VERSION 5.8 ;
BUSBITCHARS "[]" ;
DIVIDERCHAR "/" ;
UNITS
    DATABASE MICRONS 1000 ;
END UNITS

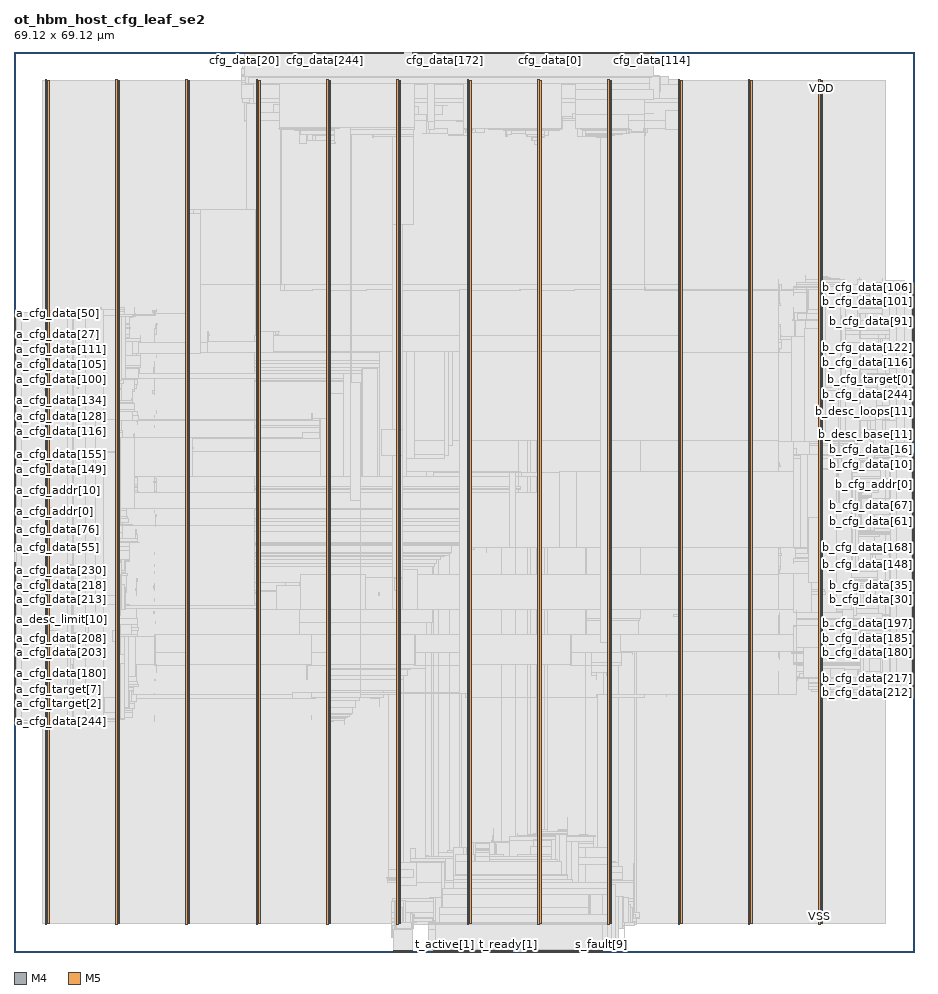
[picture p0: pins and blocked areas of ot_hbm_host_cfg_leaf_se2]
MACRO ot_hbm_host_cfg_leaf_se2
  FOREIGN ot_hbm_host_cfg_leaf_se2 0 0 ;
  CLASS BLOCK ;
  SIZE 69.12 BY 69.12 ;
  PIN a_cfg_addr[0]
    DIRECTION OUTPUT ;
    USE SIGNAL ;
    PORT
      LAYER M4 ;
        RECT  0 33.84 0.084 33.864 ;
    END
  END a_cfg_addr[0]
  PIN a_cfg_addr[10]
    DIRECTION OUTPUT ;
    USE SIGNAL ;
    PORT
      LAYER M4 ;
        RECT  0 34.8 0.084 34.824 ;
    END
  END a_cfg_addr[10]
  PIN a_cfg_addr[11]
    DIRECTION OUTPUT ;
    USE SIGNAL ;
    PORT
      LAYER M4 ;
        RECT  0 34.896 0.084 34.92 ;
    END
  END a_cfg_addr[11]
  PIN a_cfg_addr[1]
    DIRECTION OUTPUT ;
    USE SIGNAL ;
    PORT
      LAYER M4 ;
        RECT  0 33.936 0.084 33.96 ;
    END
  END a_cfg_addr[1]
  PIN a_cfg_addr[2]
    DIRECTION OUTPUT ;
    USE SIGNAL ;
    PORT
      LAYER M4 ;
        RECT  0 34.032 0.084 34.056 ;
    END
  END a_cfg_addr[2]
  PIN a_cfg_addr[3]
    DIRECTION OUTPUT ;
    USE SIGNAL ;
    PORT
      LAYER M4 ;
        RECT  0 34.128 0.084 34.152 ;
    END
  END a_cfg_addr[3]
  PIN a_cfg_addr[4]
    DIRECTION OUTPUT ;
    USE SIGNAL ;
    PORT
      LAYER M4 ;
        RECT  0 34.224 0.084 34.248 ;
    END
  END a_cfg_addr[4]
  PIN a_cfg_addr[5]
    DIRECTION OUTPUT ;
    USE SIGNAL ;
    PORT
      LAYER M4 ;
        RECT  0 34.32 0.084 34.344 ;
    END
  END a_cfg_addr[5]
  PIN a_cfg_addr[6]
    DIRECTION OUTPUT ;
    USE SIGNAL ;
    PORT
      LAYER M4 ;
        RECT  0 34.416 0.084 34.44 ;
    END
  END a_cfg_addr[6]
  PIN a_cfg_addr[7]
    DIRECTION OUTPUT ;
    USE SIGNAL ;
    PORT
      LAYER M4 ;
        RECT  0 34.512 0.084 34.536 ;
    END
  END a_cfg_addr[7]
  PIN a_cfg_addr[8]
    DIRECTION OUTPUT ;
    USE SIGNAL ;
    PORT
      LAYER M4 ;
        RECT  0 34.608 0.084 34.632 ;
    END
  END a_cfg_addr[8]
  PIN a_cfg_addr[9]
    DIRECTION OUTPUT ;
    USE SIGNAL ;
    PORT
      LAYER M4 ;
        RECT  0 34.704 0.084 34.728 ;
    END
  END a_cfg_addr[9]
  PIN a_cfg_data[0]
    DIRECTION OUTPUT ;
    USE SIGNAL ;
    PORT
      LAYER M4 ;
        RECT  0 34.992 0.084 35.016 ;
    END
  END a_cfg_data[0]
  PIN a_cfg_data[100]
    DIRECTION OUTPUT ;
    USE SIGNAL ;
    PORT
      LAYER M4 ;
        RECT  0 44.592 0.084 44.616 ;
    END
  END a_cfg_data[100]
  PIN a_cfg_data[101]
    DIRECTION OUTPUT ;
    USE SIGNAL ;
    PORT
      LAYER M4 ;
        RECT  0 44.688 0.084 44.712 ;
    END
  END a_cfg_data[101]
  PIN a_cfg_data[102]
    DIRECTION OUTPUT ;
    USE SIGNAL ;
    PORT
      LAYER M4 ;
        RECT  0 44.784 0.084 44.808 ;
    END
  END a_cfg_data[102]
  PIN a_cfg_data[103]
    DIRECTION OUTPUT ;
    USE SIGNAL ;
    PORT
      LAYER M4 ;
        RECT  0 44.88 0.084 44.904 ;
    END
  END a_cfg_data[103]
  PIN a_cfg_data[104]
    DIRECTION OUTPUT ;
    USE SIGNAL ;
    PORT
      LAYER M4 ;
        RECT  0 44.976 0.084 45 ;
    END
  END a_cfg_data[104]
  PIN a_cfg_data[105]
    DIRECTION OUTPUT ;
    USE SIGNAL ;
    PORT
      LAYER M4 ;
        RECT  0 45.072 0.084 45.096 ;
    END
  END a_cfg_data[105]
  PIN a_cfg_data[106]
    DIRECTION OUTPUT ;
    USE SIGNAL ;
    PORT
      LAYER M4 ;
        RECT  0 45.168 0.084 45.192 ;
    END
  END a_cfg_data[106]
  PIN a_cfg_data[107]
    DIRECTION OUTPUT ;
    USE SIGNAL ;
    PORT
      LAYER M4 ;
        RECT  0 45.264 0.084 45.288 ;
    END
  END a_cfg_data[107]
  PIN a_cfg_data[108]
    DIRECTION OUTPUT ;
    USE SIGNAL ;
    PORT
      LAYER M4 ;
        RECT  0 45.36 0.084 45.384 ;
    END
  END a_cfg_data[108]
  PIN a_cfg_data[109]
    DIRECTION OUTPUT ;
    USE SIGNAL ;
    PORT
      LAYER M4 ;
        RECT  0 45.456 0.084 45.48 ;
    END
  END a_cfg_data[109]
  PIN a_cfg_data[10]
    DIRECTION OUTPUT ;
    USE SIGNAL ;
    PORT
      LAYER M4 ;
        RECT  0 35.952 0.084 35.976 ;
    END
  END a_cfg_data[10]
  PIN a_cfg_data[110]
    DIRECTION OUTPUT ;
    USE SIGNAL ;
    PORT
      LAYER M4 ;
        RECT  0 45.552 0.084 45.576 ;
    END
  END a_cfg_data[110]
  PIN a_cfg_data[111]
    DIRECTION OUTPUT ;
    USE SIGNAL ;
    PORT
      LAYER M4 ;
        RECT  0 45.648 0.084 45.672 ;
    END
  END a_cfg_data[111]
  PIN a_cfg_data[112]
    DIRECTION OUTPUT ;
    USE SIGNAL ;
    PORT
      LAYER M4 ;
        RECT  0 45.744 0.084 45.768 ;
    END
  END a_cfg_data[112]
  PIN a_cfg_data[113]
    DIRECTION OUTPUT ;
    USE SIGNAL ;
    PORT
      LAYER M4 ;
        RECT  0 45.84 0.084 45.864 ;
    END
  END a_cfg_data[113]
  PIN a_cfg_data[114]
    DIRECTION OUTPUT ;
    USE SIGNAL ;
    PORT
      LAYER M4 ;
        RECT  0 45.936 0.084 45.96 ;
    END
  END a_cfg_data[114]
  PIN a_cfg_data[115]
    DIRECTION OUTPUT ;
    USE SIGNAL ;
    PORT
      LAYER M4 ;
        RECT  0 46.032 0.084 46.056 ;
    END
  END a_cfg_data[115]
  PIN a_cfg_data[116]
    DIRECTION OUTPUT ;
    USE SIGNAL ;
    PORT
      LAYER M4 ;
        RECT  0 39.984 0.084 40.008 ;
    END
  END a_cfg_data[116]
  PIN a_cfg_data[117]
    DIRECTION OUTPUT ;
    USE SIGNAL ;
    PORT
      LAYER M4 ;
        RECT  0 40.08 0.084 40.104 ;
    END
  END a_cfg_data[117]
  PIN a_cfg_data[118]
    DIRECTION OUTPUT ;
    USE SIGNAL ;
    PORT
      LAYER M4 ;
        RECT  0 40.176 0.084 40.2 ;
    END
  END a_cfg_data[118]
  PIN a_cfg_data[119]
    DIRECTION OUTPUT ;
    USE SIGNAL ;
    PORT
      LAYER M4 ;
        RECT  0 40.272 0.084 40.296 ;
    END
  END a_cfg_data[119]
  PIN a_cfg_data[11]
    DIRECTION OUTPUT ;
    USE SIGNAL ;
    PORT
      LAYER M4 ;
        RECT  0 36.048 0.084 36.072 ;
    END
  END a_cfg_data[11]
  PIN a_cfg_data[120]
    DIRECTION OUTPUT ;
    USE SIGNAL ;
    PORT
      LAYER M4 ;
        RECT  0 40.368 0.084 40.392 ;
    END
  END a_cfg_data[120]
  PIN a_cfg_data[121]
    DIRECTION OUTPUT ;
    USE SIGNAL ;
    PORT
      LAYER M4 ;
        RECT  0 40.464 0.084 40.488 ;
    END
  END a_cfg_data[121]
  PIN a_cfg_data[122]
    DIRECTION OUTPUT ;
    USE SIGNAL ;
    PORT
      LAYER M4 ;
        RECT  0 40.56 0.084 40.584 ;
    END
  END a_cfg_data[122]
  PIN a_cfg_data[123]
    DIRECTION OUTPUT ;
    USE SIGNAL ;
    PORT
      LAYER M4 ;
        RECT  0 40.656 0.084 40.68 ;
    END
  END a_cfg_data[123]
  PIN a_cfg_data[124]
    DIRECTION OUTPUT ;
    USE SIGNAL ;
    PORT
      LAYER M4 ;
        RECT  0 40.752 0.084 40.776 ;
    END
  END a_cfg_data[124]
  PIN a_cfg_data[125]
    DIRECTION OUTPUT ;
    USE SIGNAL ;
    PORT
      LAYER M4 ;
        RECT  0 40.848 0.084 40.872 ;
    END
  END a_cfg_data[125]
  PIN a_cfg_data[126]
    DIRECTION OUTPUT ;
    USE SIGNAL ;
    PORT
      LAYER M4 ;
        RECT  0 40.944 0.084 40.968 ;
    END
  END a_cfg_data[126]
  PIN a_cfg_data[127]
    DIRECTION OUTPUT ;
    USE SIGNAL ;
    PORT
      LAYER M4 ;
        RECT  0 41.04 0.084 41.064 ;
    END
  END a_cfg_data[127]
  PIN a_cfg_data[128]
    DIRECTION OUTPUT ;
    USE SIGNAL ;
    PORT
      LAYER M4 ;
        RECT  0 41.136 0.084 41.16 ;
    END
  END a_cfg_data[128]
  PIN a_cfg_data[129]
    DIRECTION OUTPUT ;
    USE SIGNAL ;
    PORT
      LAYER M4 ;
        RECT  0 41.232 0.084 41.256 ;
    END
  END a_cfg_data[129]
  PIN a_cfg_data[12]
    DIRECTION OUTPUT ;
    USE SIGNAL ;
    PORT
      LAYER M4 ;
        RECT  0 36.144 0.084 36.168 ;
    END
  END a_cfg_data[12]
  PIN a_cfg_data[130]
    DIRECTION OUTPUT ;
    USE SIGNAL ;
    PORT
      LAYER M4 ;
        RECT  0 41.328 0.084 41.352 ;
    END
  END a_cfg_data[130]
  PIN a_cfg_data[131]
    DIRECTION OUTPUT ;
    USE SIGNAL ;
    PORT
      LAYER M4 ;
        RECT  0 41.424 0.084 41.448 ;
    END
  END a_cfg_data[131]
  PIN a_cfg_data[132]
    DIRECTION OUTPUT ;
    USE SIGNAL ;
    PORT
      LAYER M4 ;
        RECT  0 41.52 0.084 41.544 ;
    END
  END a_cfg_data[132]
  PIN a_cfg_data[133]
    DIRECTION OUTPUT ;
    USE SIGNAL ;
    PORT
      LAYER M4 ;
        RECT  0 41.616 0.084 41.64 ;
    END
  END a_cfg_data[133]
  PIN a_cfg_data[134]
    DIRECTION OUTPUT ;
    USE SIGNAL ;
    PORT
      LAYER M4 ;
        RECT  0 41.712 0.084 41.736 ;
    END
  END a_cfg_data[134]
  PIN a_cfg_data[135]
    DIRECTION OUTPUT ;
    USE SIGNAL ;
    PORT
      LAYER M4 ;
        RECT  0 41.808 0.084 41.832 ;
    END
  END a_cfg_data[135]
  PIN a_cfg_data[136]
    DIRECTION OUTPUT ;
    USE SIGNAL ;
    PORT
      LAYER M4 ;
        RECT  0 41.904 0.084 41.928 ;
    END
  END a_cfg_data[136]
  PIN a_cfg_data[137]
    DIRECTION OUTPUT ;
    USE SIGNAL ;
    PORT
      LAYER M4 ;
        RECT  0 42 0.084 42.024 ;
    END
  END a_cfg_data[137]
  PIN a_cfg_data[138]
    DIRECTION OUTPUT ;
    USE SIGNAL ;
    PORT
      LAYER M4 ;
        RECT  0 42.096 0.084 42.12 ;
    END
  END a_cfg_data[138]
  PIN a_cfg_data[139]
    DIRECTION OUTPUT ;
    USE SIGNAL ;
    PORT
      LAYER M4 ;
        RECT  0 42.192 0.084 42.216 ;
    END
  END a_cfg_data[139]
  PIN a_cfg_data[13]
    DIRECTION OUTPUT ;
    USE SIGNAL ;
    PORT
      LAYER M4 ;
        RECT  0 36.24 0.084 36.264 ;
    END
  END a_cfg_data[13]
  PIN a_cfg_data[140]
    DIRECTION OUTPUT ;
    USE SIGNAL ;
    PORT
      LAYER M4 ;
        RECT  0 42.288 0.084 42.312 ;
    END
  END a_cfg_data[140]
  PIN a_cfg_data[141]
    DIRECTION OUTPUT ;
    USE SIGNAL ;
    PORT
      LAYER M4 ;
        RECT  0 42.384 0.084 42.408 ;
    END
  END a_cfg_data[141]
  PIN a_cfg_data[142]
    DIRECTION OUTPUT ;
    USE SIGNAL ;
    PORT
      LAYER M4 ;
        RECT  0 42.48 0.084 42.504 ;
    END
  END a_cfg_data[142]
  PIN a_cfg_data[143]
    DIRECTION OUTPUT ;
    USE SIGNAL ;
    PORT
      LAYER M4 ;
        RECT  0 42.576 0.084 42.6 ;
    END
  END a_cfg_data[143]
  PIN a_cfg_data[144]
    DIRECTION OUTPUT ;
    USE SIGNAL ;
    PORT
      LAYER M4 ;
        RECT  0 42.672 0.084 42.696 ;
    END
  END a_cfg_data[144]
  PIN a_cfg_data[145]
    DIRECTION OUTPUT ;
    USE SIGNAL ;
    PORT
      LAYER M4 ;
        RECT  0 42.768 0.084 42.792 ;
    END
  END a_cfg_data[145]
  PIN a_cfg_data[146]
    DIRECTION OUTPUT ;
    USE SIGNAL ;
    PORT
      LAYER M4 ;
        RECT  0 42.864 0.084 42.888 ;
    END
  END a_cfg_data[146]
  PIN a_cfg_data[147]
    DIRECTION OUTPUT ;
    USE SIGNAL ;
    PORT
      LAYER M4 ;
        RECT  0 42.96 0.084 42.984 ;
    END
  END a_cfg_data[147]
  PIN a_cfg_data[148]
    DIRECTION OUTPUT ;
    USE SIGNAL ;
    PORT
      LAYER M4 ;
        RECT  0 36.912 0.084 36.936 ;
    END
  END a_cfg_data[148]
  PIN a_cfg_data[149]
    DIRECTION OUTPUT ;
    USE SIGNAL ;
    PORT
      LAYER M4 ;
        RECT  0 37.008 0.084 37.032 ;
    END
  END a_cfg_data[149]
  PIN a_cfg_data[14]
    DIRECTION OUTPUT ;
    USE SIGNAL ;
    PORT
      LAYER M4 ;
        RECT  0 36.336 0.084 36.36 ;
    END
  END a_cfg_data[14]
  PIN a_cfg_data[150]
    DIRECTION OUTPUT ;
    USE SIGNAL ;
    PORT
      LAYER M4 ;
        RECT  0 37.104 0.084 37.128 ;
    END
  END a_cfg_data[150]
  PIN a_cfg_data[151]
    DIRECTION OUTPUT ;
    USE SIGNAL ;
    PORT
      LAYER M4 ;
        RECT  0 37.2 0.084 37.224 ;
    END
  END a_cfg_data[151]
  PIN a_cfg_data[152]
    DIRECTION OUTPUT ;
    USE SIGNAL ;
    PORT
      LAYER M4 ;
        RECT  0 37.296 0.084 37.32 ;
    END
  END a_cfg_data[152]
  PIN a_cfg_data[153]
    DIRECTION OUTPUT ;
    USE SIGNAL ;
    PORT
      LAYER M4 ;
        RECT  0 37.392 0.084 37.416 ;
    END
  END a_cfg_data[153]
  PIN a_cfg_data[154]
    DIRECTION OUTPUT ;
    USE SIGNAL ;
    PORT
      LAYER M4 ;
        RECT  0 37.488 0.084 37.512 ;
    END
  END a_cfg_data[154]
  PIN a_cfg_data[155]
    DIRECTION OUTPUT ;
    USE SIGNAL ;
    PORT
      LAYER M4 ;
        RECT  0 37.584 0.084 37.608 ;
    END
  END a_cfg_data[155]
  PIN a_cfg_data[156]
    DIRECTION OUTPUT ;
    USE SIGNAL ;
    PORT
      LAYER M4 ;
        RECT  0 37.68 0.084 37.704 ;
    END
  END a_cfg_data[156]
  PIN a_cfg_data[157]
    DIRECTION OUTPUT ;
    USE SIGNAL ;
    PORT
      LAYER M4 ;
        RECT  0 37.776 0.084 37.8 ;
    END
  END a_cfg_data[157]
  PIN a_cfg_data[158]
    DIRECTION OUTPUT ;
    USE SIGNAL ;
    PORT
      LAYER M4 ;
        RECT  0 37.872 0.084 37.896 ;
    END
  END a_cfg_data[158]
  PIN a_cfg_data[159]
    DIRECTION OUTPUT ;
    USE SIGNAL ;
    PORT
      LAYER M4 ;
        RECT  0 37.968 0.084 37.992 ;
    END
  END a_cfg_data[159]
  PIN a_cfg_data[15]
    DIRECTION OUTPUT ;
    USE SIGNAL ;
    PORT
      LAYER M4 ;
        RECT  0 36.432 0.084 36.456 ;
    END
  END a_cfg_data[15]
  PIN a_cfg_data[160]
    DIRECTION OUTPUT ;
    USE SIGNAL ;
    PORT
      LAYER M4 ;
        RECT  0 38.064 0.084 38.088 ;
    END
  END a_cfg_data[160]
  PIN a_cfg_data[161]
    DIRECTION OUTPUT ;
    USE SIGNAL ;
    PORT
      LAYER M4 ;
        RECT  0 38.16 0.084 38.184 ;
    END
  END a_cfg_data[161]
  PIN a_cfg_data[162]
    DIRECTION OUTPUT ;
    USE SIGNAL ;
    PORT
      LAYER M4 ;
        RECT  0 38.256 0.084 38.28 ;
    END
  END a_cfg_data[162]
  PIN a_cfg_data[163]
    DIRECTION OUTPUT ;
    USE SIGNAL ;
    PORT
      LAYER M4 ;
        RECT  0 38.352 0.084 38.376 ;
    END
  END a_cfg_data[163]
  PIN a_cfg_data[164]
    DIRECTION OUTPUT ;
    USE SIGNAL ;
    PORT
      LAYER M4 ;
        RECT  0 38.448 0.084 38.472 ;
    END
  END a_cfg_data[164]
  PIN a_cfg_data[165]
    DIRECTION OUTPUT ;
    USE SIGNAL ;
    PORT
      LAYER M4 ;
        RECT  0 38.544 0.084 38.568 ;
    END
  END a_cfg_data[165]
  PIN a_cfg_data[166]
    DIRECTION OUTPUT ;
    USE SIGNAL ;
    PORT
      LAYER M4 ;
        RECT  0 38.64 0.084 38.664 ;
    END
  END a_cfg_data[166]
  PIN a_cfg_data[167]
    DIRECTION OUTPUT ;
    USE SIGNAL ;
    PORT
      LAYER M4 ;
        RECT  0 38.736 0.084 38.76 ;
    END
  END a_cfg_data[167]
  PIN a_cfg_data[168]
    DIRECTION OUTPUT ;
    USE SIGNAL ;
    PORT
      LAYER M4 ;
        RECT  0 38.832 0.084 38.856 ;
    END
  END a_cfg_data[168]
  PIN a_cfg_data[169]
    DIRECTION OUTPUT ;
    USE SIGNAL ;
    PORT
      LAYER M4 ;
        RECT  0 38.928 0.084 38.952 ;
    END
  END a_cfg_data[169]
  PIN a_cfg_data[16]
    DIRECTION OUTPUT ;
    USE SIGNAL ;
    PORT
      LAYER M4 ;
        RECT  0 36.528 0.084 36.552 ;
    END
  END a_cfg_data[16]
  PIN a_cfg_data[170]
    DIRECTION OUTPUT ;
    USE SIGNAL ;
    PORT
      LAYER M4 ;
        RECT  0 39.024 0.084 39.048 ;
    END
  END a_cfg_data[170]
  PIN a_cfg_data[171]
    DIRECTION OUTPUT ;
    USE SIGNAL ;
    PORT
      LAYER M4 ;
        RECT  0 39.12 0.084 39.144 ;
    END
  END a_cfg_data[171]
  PIN a_cfg_data[172]
    DIRECTION OUTPUT ;
    USE SIGNAL ;
    PORT
      LAYER M4 ;
        RECT  0 39.216 0.084 39.24 ;
    END
  END a_cfg_data[172]
  PIN a_cfg_data[173]
    DIRECTION OUTPUT ;
    USE SIGNAL ;
    PORT
      LAYER M4 ;
        RECT  0 39.312 0.084 39.336 ;
    END
  END a_cfg_data[173]
  PIN a_cfg_data[174]
    DIRECTION OUTPUT ;
    USE SIGNAL ;
    PORT
      LAYER M4 ;
        RECT  0 39.408 0.084 39.432 ;
    END
  END a_cfg_data[174]
  PIN a_cfg_data[175]
    DIRECTION OUTPUT ;
    USE SIGNAL ;
    PORT
      LAYER M4 ;
        RECT  0 39.504 0.084 39.528 ;
    END
  END a_cfg_data[175]
  PIN a_cfg_data[176]
    DIRECTION OUTPUT ;
    USE SIGNAL ;
    PORT
      LAYER M4 ;
        RECT  0 39.6 0.084 39.624 ;
    END
  END a_cfg_data[176]
  PIN a_cfg_data[177]
    DIRECTION OUTPUT ;
    USE SIGNAL ;
    PORT
      LAYER M4 ;
        RECT  0 39.696 0.084 39.72 ;
    END
  END a_cfg_data[177]
  PIN a_cfg_data[178]
    DIRECTION OUTPUT ;
    USE SIGNAL ;
    PORT
      LAYER M4 ;
        RECT  0 39.792 0.084 39.816 ;
    END
  END a_cfg_data[178]
  PIN a_cfg_data[179]
    DIRECTION OUTPUT ;
    USE SIGNAL ;
    PORT
      LAYER M4 ;
        RECT  0 39.888 0.084 39.912 ;
    END
  END a_cfg_data[179]
  PIN a_cfg_data[17]
    DIRECTION OUTPUT ;
    USE SIGNAL ;
    PORT
      LAYER M4 ;
        RECT  0 36.624 0.084 36.648 ;
    END
  END a_cfg_data[17]
  PIN a_cfg_data[180]
    DIRECTION OUTPUT ;
    USE SIGNAL ;
    PORT
      LAYER M4 ;
        RECT  0 20.784 0.084 20.808 ;
    END
  END a_cfg_data[180]
  PIN a_cfg_data[181]
    DIRECTION OUTPUT ;
    USE SIGNAL ;
    PORT
      LAYER M4 ;
        RECT  0 20.88 0.084 20.904 ;
    END
  END a_cfg_data[181]
  PIN a_cfg_data[182]
    DIRECTION OUTPUT ;
    USE SIGNAL ;
    PORT
      LAYER M4 ;
        RECT  0 20.976 0.084 21 ;
    END
  END a_cfg_data[182]
  PIN a_cfg_data[183]
    DIRECTION OUTPUT ;
    USE SIGNAL ;
    PORT
      LAYER M4 ;
        RECT  0 21.072 0.084 21.096 ;
    END
  END a_cfg_data[183]
  PIN a_cfg_data[184]
    DIRECTION OUTPUT ;
    USE SIGNAL ;
    PORT
      LAYER M4 ;
        RECT  0 21.168 0.084 21.192 ;
    END
  END a_cfg_data[184]
  PIN a_cfg_data[185]
    DIRECTION OUTPUT ;
    USE SIGNAL ;
    PORT
      LAYER M4 ;
        RECT  0 21.264 0.084 21.288 ;
    END
  END a_cfg_data[185]
  PIN a_cfg_data[186]
    DIRECTION OUTPUT ;
    USE SIGNAL ;
    PORT
      LAYER M4 ;
        RECT  0 21.36 0.084 21.384 ;
    END
  END a_cfg_data[186]
  PIN a_cfg_data[187]
    DIRECTION OUTPUT ;
    USE SIGNAL ;
    PORT
      LAYER M4 ;
        RECT  0 21.456 0.084 21.48 ;
    END
  END a_cfg_data[187]
  PIN a_cfg_data[188]
    DIRECTION OUTPUT ;
    USE SIGNAL ;
    PORT
      LAYER M4 ;
        RECT  0 21.552 0.084 21.576 ;
    END
  END a_cfg_data[188]
  PIN a_cfg_data[189]
    DIRECTION OUTPUT ;
    USE SIGNAL ;
    PORT
      LAYER M4 ;
        RECT  0 21.648 0.084 21.672 ;
    END
  END a_cfg_data[189]
  PIN a_cfg_data[18]
    DIRECTION OUTPUT ;
    USE SIGNAL ;
    PORT
      LAYER M4 ;
        RECT  0 36.72 0.084 36.744 ;
    END
  END a_cfg_data[18]
  PIN a_cfg_data[190]
    DIRECTION OUTPUT ;
    USE SIGNAL ;
    PORT
      LAYER M4 ;
        RECT  0 21.744 0.084 21.768 ;
    END
  END a_cfg_data[190]
  PIN a_cfg_data[191]
    DIRECTION OUTPUT ;
    USE SIGNAL ;
    PORT
      LAYER M4 ;
        RECT  0 21.84 0.084 21.864 ;
    END
  END a_cfg_data[191]
  PIN a_cfg_data[192]
    DIRECTION OUTPUT ;
    USE SIGNAL ;
    PORT
      LAYER M4 ;
        RECT  0 21.936 0.084 21.96 ;
    END
  END a_cfg_data[192]
  PIN a_cfg_data[193]
    DIRECTION OUTPUT ;
    USE SIGNAL ;
    PORT
      LAYER M4 ;
        RECT  0 22.032 0.084 22.056 ;
    END
  END a_cfg_data[193]
  PIN a_cfg_data[194]
    DIRECTION OUTPUT ;
    USE SIGNAL ;
    PORT
      LAYER M4 ;
        RECT  0 22.128 0.084 22.152 ;
    END
  END a_cfg_data[194]
  PIN a_cfg_data[195]
    DIRECTION OUTPUT ;
    USE SIGNAL ;
    PORT
      LAYER M4 ;
        RECT  0 22.224 0.084 22.248 ;
    END
  END a_cfg_data[195]
  PIN a_cfg_data[196]
    DIRECTION OUTPUT ;
    USE SIGNAL ;
    PORT
      LAYER M4 ;
        RECT  0 22.32 0.084 22.344 ;
    END
  END a_cfg_data[196]
  PIN a_cfg_data[197]
    DIRECTION OUTPUT ;
    USE SIGNAL ;
    PORT
      LAYER M4 ;
        RECT  0 22.416 0.084 22.44 ;
    END
  END a_cfg_data[197]
  PIN a_cfg_data[198]
    DIRECTION OUTPUT ;
    USE SIGNAL ;
    PORT
      LAYER M4 ;
        RECT  0 22.512 0.084 22.536 ;
    END
  END a_cfg_data[198]
  PIN a_cfg_data[199]
    DIRECTION OUTPUT ;
    USE SIGNAL ;
    PORT
      LAYER M4 ;
        RECT  0 22.608 0.084 22.632 ;
    END
  END a_cfg_data[199]
  PIN a_cfg_data[19]
    DIRECTION OUTPUT ;
    USE SIGNAL ;
    PORT
      LAYER M4 ;
        RECT  0 36.816 0.084 36.84 ;
    END
  END a_cfg_data[19]
  PIN a_cfg_data[1]
    DIRECTION OUTPUT ;
    USE SIGNAL ;
    PORT
      LAYER M4 ;
        RECT  0 35.088 0.084 35.112 ;
    END
  END a_cfg_data[1]
  PIN a_cfg_data[200]
    DIRECTION OUTPUT ;
    USE SIGNAL ;
    PORT
      LAYER M4 ;
        RECT  0 22.704 0.084 22.728 ;
    END
  END a_cfg_data[200]
  PIN a_cfg_data[201]
    DIRECTION OUTPUT ;
    USE SIGNAL ;
    PORT
      LAYER M4 ;
        RECT  0 22.8 0.084 22.824 ;
    END
  END a_cfg_data[201]
  PIN a_cfg_data[202]
    DIRECTION OUTPUT ;
    USE SIGNAL ;
    PORT
      LAYER M4 ;
        RECT  0 22.896 0.084 22.92 ;
    END
  END a_cfg_data[202]
  PIN a_cfg_data[203]
    DIRECTION OUTPUT ;
    USE SIGNAL ;
    PORT
      LAYER M4 ;
        RECT  0 22.992 0.084 23.016 ;
    END
  END a_cfg_data[203]
  PIN a_cfg_data[204]
    DIRECTION OUTPUT ;
    USE SIGNAL ;
    PORT
      LAYER M4 ;
        RECT  0 23.088 0.084 23.112 ;
    END
  END a_cfg_data[204]
  PIN a_cfg_data[205]
    DIRECTION OUTPUT ;
    USE SIGNAL ;
    PORT
      LAYER M4 ;
        RECT  0 23.184 0.084 23.208 ;
    END
  END a_cfg_data[205]
  PIN a_cfg_data[206]
    DIRECTION OUTPUT ;
    USE SIGNAL ;
    PORT
      LAYER M4 ;
        RECT  0 23.28 0.084 23.304 ;
    END
  END a_cfg_data[206]
  PIN a_cfg_data[207]
    DIRECTION OUTPUT ;
    USE SIGNAL ;
    PORT
      LAYER M4 ;
        RECT  0 23.376 0.084 23.4 ;
    END
  END a_cfg_data[207]
  PIN a_cfg_data[208]
    DIRECTION OUTPUT ;
    USE SIGNAL ;
    PORT
      LAYER M4 ;
        RECT  0 23.472 0.084 23.496 ;
    END
  END a_cfg_data[208]
  PIN a_cfg_data[209]
    DIRECTION OUTPUT ;
    USE SIGNAL ;
    PORT
      LAYER M4 ;
        RECT  0 23.568 0.084 23.592 ;
    END
  END a_cfg_data[209]
  PIN a_cfg_data[20]
    DIRECTION OUTPUT ;
    USE SIGNAL ;
    PORT
      LAYER M4 ;
        RECT  0 46.128 0.084 46.152 ;
    END
  END a_cfg_data[20]
  PIN a_cfg_data[210]
    DIRECTION OUTPUT ;
    USE SIGNAL ;
    PORT
      LAYER M4 ;
        RECT  0 23.664 0.084 23.688 ;
    END
  END a_cfg_data[210]
  PIN a_cfg_data[211]
    DIRECTION OUTPUT ;
    USE SIGNAL ;
    PORT
      LAYER M4 ;
        RECT  0 23.76 0.084 23.784 ;
    END
  END a_cfg_data[211]
  PIN a_cfg_data[212]
    DIRECTION OUTPUT ;
    USE SIGNAL ;
    PORT
      LAYER M4 ;
        RECT  0 26.928 0.084 26.952 ;
    END
  END a_cfg_data[212]
  PIN a_cfg_data[213]
    DIRECTION OUTPUT ;
    USE SIGNAL ;
    PORT
      LAYER M4 ;
        RECT  0 27.024 0.084 27.048 ;
    END
  END a_cfg_data[213]
  PIN a_cfg_data[214]
    DIRECTION OUTPUT ;
    USE SIGNAL ;
    PORT
      LAYER M4 ;
        RECT  0 27.12 0.084 27.144 ;
    END
  END a_cfg_data[214]
  PIN a_cfg_data[215]
    DIRECTION OUTPUT ;
    USE SIGNAL ;
    PORT
      LAYER M4 ;
        RECT  0 27.216 0.084 27.24 ;
    END
  END a_cfg_data[215]
  PIN a_cfg_data[216]
    DIRECTION OUTPUT ;
    USE SIGNAL ;
    PORT
      LAYER M4 ;
        RECT  0 27.312 0.084 27.336 ;
    END
  END a_cfg_data[216]
  PIN a_cfg_data[217]
    DIRECTION OUTPUT ;
    USE SIGNAL ;
    PORT
      LAYER M4 ;
        RECT  0 27.408 0.084 27.432 ;
    END
  END a_cfg_data[217]
  PIN a_cfg_data[218]
    DIRECTION OUTPUT ;
    USE SIGNAL ;
    PORT
      LAYER M4 ;
        RECT  0 27.504 0.084 27.528 ;
    END
  END a_cfg_data[218]
  PIN a_cfg_data[219]
    DIRECTION OUTPUT ;
    USE SIGNAL ;
    PORT
      LAYER M4 ;
        RECT  0 27.6 0.084 27.624 ;
    END
  END a_cfg_data[219]
  PIN a_cfg_data[21]
    DIRECTION OUTPUT ;
    USE SIGNAL ;
    PORT
      LAYER M4 ;
        RECT  0 46.224 0.084 46.248 ;
    END
  END a_cfg_data[21]
  PIN a_cfg_data[220]
    DIRECTION OUTPUT ;
    USE SIGNAL ;
    PORT
      LAYER M4 ;
        RECT  0 27.696 0.084 27.72 ;
    END
  END a_cfg_data[220]
  PIN a_cfg_data[221]
    DIRECTION OUTPUT ;
    USE SIGNAL ;
    PORT
      LAYER M4 ;
        RECT  0 27.792 0.084 27.816 ;
    END
  END a_cfg_data[221]
  PIN a_cfg_data[222]
    DIRECTION OUTPUT ;
    USE SIGNAL ;
    PORT
      LAYER M4 ;
        RECT  0 27.888 0.084 27.912 ;
    END
  END a_cfg_data[222]
  PIN a_cfg_data[223]
    DIRECTION OUTPUT ;
    USE SIGNAL ;
    PORT
      LAYER M4 ;
        RECT  0 27.984 0.084 28.008 ;
    END
  END a_cfg_data[223]
  PIN a_cfg_data[224]
    DIRECTION OUTPUT ;
    USE SIGNAL ;
    PORT
      LAYER M4 ;
        RECT  0 28.08 0.084 28.104 ;
    END
  END a_cfg_data[224]
  PIN a_cfg_data[225]
    DIRECTION OUTPUT ;
    USE SIGNAL ;
    PORT
      LAYER M4 ;
        RECT  0 28.176 0.084 28.2 ;
    END
  END a_cfg_data[225]
  PIN a_cfg_data[226]
    DIRECTION OUTPUT ;
    USE SIGNAL ;
    PORT
      LAYER M4 ;
        RECT  0 28.272 0.084 28.296 ;
    END
  END a_cfg_data[226]
  PIN a_cfg_data[227]
    DIRECTION OUTPUT ;
    USE SIGNAL ;
    PORT
      LAYER M4 ;
        RECT  0 28.368 0.084 28.392 ;
    END
  END a_cfg_data[227]
  PIN a_cfg_data[228]
    DIRECTION OUTPUT ;
    USE SIGNAL ;
    PORT
      LAYER M4 ;
        RECT  0 28.464 0.084 28.488 ;
    END
  END a_cfg_data[228]
  PIN a_cfg_data[229]
    DIRECTION OUTPUT ;
    USE SIGNAL ;
    PORT
      LAYER M4 ;
        RECT  0 28.56 0.084 28.584 ;
    END
  END a_cfg_data[229]
  PIN a_cfg_data[22]
    DIRECTION OUTPUT ;
    USE SIGNAL ;
    PORT
      LAYER M4 ;
        RECT  0 46.32 0.084 46.344 ;
    END
  END a_cfg_data[22]
  PIN a_cfg_data[230]
    DIRECTION OUTPUT ;
    USE SIGNAL ;
    PORT
      LAYER M4 ;
        RECT  0 28.656 0.084 28.68 ;
    END
  END a_cfg_data[230]
  PIN a_cfg_data[231]
    DIRECTION OUTPUT ;
    USE SIGNAL ;
    PORT
      LAYER M4 ;
        RECT  0 28.752 0.084 28.776 ;
    END
  END a_cfg_data[231]
  PIN a_cfg_data[232]
    DIRECTION OUTPUT ;
    USE SIGNAL ;
    PORT
      LAYER M4 ;
        RECT  0 28.848 0.084 28.872 ;
    END
  END a_cfg_data[232]
  PIN a_cfg_data[233]
    DIRECTION OUTPUT ;
    USE SIGNAL ;
    PORT
      LAYER M4 ;
        RECT  0 28.944 0.084 28.968 ;
    END
  END a_cfg_data[233]
  PIN a_cfg_data[234]
    DIRECTION OUTPUT ;
    USE SIGNAL ;
    PORT
      LAYER M4 ;
        RECT  0 29.04 0.084 29.064 ;
    END
  END a_cfg_data[234]
  PIN a_cfg_data[235]
    DIRECTION OUTPUT ;
    USE SIGNAL ;
    PORT
      LAYER M4 ;
        RECT  0 29.136 0.084 29.16 ;
    END
  END a_cfg_data[235]
  PIN a_cfg_data[236]
    DIRECTION OUTPUT ;
    USE SIGNAL ;
    PORT
      LAYER M4 ;
        RECT  0 29.232 0.084 29.256 ;
    END
  END a_cfg_data[236]
  PIN a_cfg_data[237]
    DIRECTION OUTPUT ;
    USE SIGNAL ;
    PORT
      LAYER M4 ;
        RECT  0 29.328 0.084 29.352 ;
    END
  END a_cfg_data[237]
  PIN a_cfg_data[238]
    DIRECTION OUTPUT ;
    USE SIGNAL ;
    PORT
      LAYER M4 ;
        RECT  0 29.424 0.084 29.448 ;
    END
  END a_cfg_data[238]
  PIN a_cfg_data[239]
    DIRECTION OUTPUT ;
    USE SIGNAL ;
    PORT
      LAYER M4 ;
        RECT  0 29.52 0.084 29.544 ;
    END
  END a_cfg_data[239]
  PIN a_cfg_data[23]
    DIRECTION OUTPUT ;
    USE SIGNAL ;
    PORT
      LAYER M4 ;
        RECT  0 46.416 0.084 46.44 ;
    END
  END a_cfg_data[23]
  PIN a_cfg_data[240]
    DIRECTION OUTPUT ;
    USE SIGNAL ;
    PORT
      LAYER M4 ;
        RECT  0 29.616 0.084 29.64 ;
    END
  END a_cfg_data[240]
  PIN a_cfg_data[241]
    DIRECTION OUTPUT ;
    USE SIGNAL ;
    PORT
      LAYER M4 ;
        RECT  0 29.712 0.084 29.736 ;
    END
  END a_cfg_data[241]
  PIN a_cfg_data[242]
    DIRECTION OUTPUT ;
    USE SIGNAL ;
    PORT
      LAYER M4 ;
        RECT  0 29.808 0.084 29.832 ;
    END
  END a_cfg_data[242]
  PIN a_cfg_data[243]
    DIRECTION OUTPUT ;
    USE SIGNAL ;
    PORT
      LAYER M4 ;
        RECT  0 29.904 0.084 29.928 ;
    END
  END a_cfg_data[243]
  PIN a_cfg_data[244]
    DIRECTION OUTPUT ;
    USE SIGNAL ;
    PORT
      LAYER M4 ;
        RECT  0 17.712 0.084 17.736 ;
    END
  END a_cfg_data[244]
  PIN a_cfg_data[245]
    DIRECTION OUTPUT ;
    USE SIGNAL ;
    PORT
      LAYER M4 ;
        RECT  0 17.808 0.084 17.832 ;
    END
  END a_cfg_data[245]
  PIN a_cfg_data[246]
    DIRECTION OUTPUT ;
    USE SIGNAL ;
    PORT
      LAYER M4 ;
        RECT  0 17.904 0.084 17.928 ;
    END
  END a_cfg_data[246]
  PIN a_cfg_data[247]
    DIRECTION OUTPUT ;
    USE SIGNAL ;
    PORT
      LAYER M4 ;
        RECT  0 18 0.084 18.024 ;
    END
  END a_cfg_data[247]
  PIN a_cfg_data[248]
    DIRECTION OUTPUT ;
    USE SIGNAL ;
    PORT
      LAYER M4 ;
        RECT  0 18.096 0.084 18.12 ;
    END
  END a_cfg_data[248]
  PIN a_cfg_data[249]
    DIRECTION OUTPUT ;
    USE SIGNAL ;
    PORT
      LAYER M4 ;
        RECT  0 18.192 0.084 18.216 ;
    END
  END a_cfg_data[249]
  PIN a_cfg_data[24]
    DIRECTION OUTPUT ;
    USE SIGNAL ;
    PORT
      LAYER M4 ;
        RECT  0 46.512 0.084 46.536 ;
    END
  END a_cfg_data[24]
  PIN a_cfg_data[250]
    DIRECTION OUTPUT ;
    USE SIGNAL ;
    PORT
      LAYER M4 ;
        RECT  0 18.288 0.084 18.312 ;
    END
  END a_cfg_data[250]
  PIN a_cfg_data[251]
    DIRECTION OUTPUT ;
    USE SIGNAL ;
    PORT
      LAYER M4 ;
        RECT  0 18.384 0.084 18.408 ;
    END
  END a_cfg_data[251]
  PIN a_cfg_data[252]
    DIRECTION OUTPUT ;
    USE SIGNAL ;
    PORT
      LAYER M4 ;
        RECT  0 18.48 0.084 18.504 ;
    END
  END a_cfg_data[252]
  PIN a_cfg_data[253]
    DIRECTION OUTPUT ;
    USE SIGNAL ;
    PORT
      LAYER M4 ;
        RECT  0 18.576 0.084 18.6 ;
    END
  END a_cfg_data[253]
  PIN a_cfg_data[254]
    DIRECTION OUTPUT ;
    USE SIGNAL ;
    PORT
      LAYER M4 ;
        RECT  0 18.672 0.084 18.696 ;
    END
  END a_cfg_data[254]
  PIN a_cfg_data[255]
    DIRECTION OUTPUT ;
    USE SIGNAL ;
    PORT
      LAYER M4 ;
        RECT  0 18.768 0.084 18.792 ;
    END
  END a_cfg_data[255]
  PIN a_cfg_data[25]
    DIRECTION OUTPUT ;
    USE SIGNAL ;
    PORT
      LAYER M4 ;
        RECT  0 46.608 0.084 46.632 ;
    END
  END a_cfg_data[25]
  PIN a_cfg_data[26]
    DIRECTION OUTPUT ;
    USE SIGNAL ;
    PORT
      LAYER M4 ;
        RECT  0 46.704 0.084 46.728 ;
    END
  END a_cfg_data[26]
  PIN a_cfg_data[27]
    DIRECTION OUTPUT ;
    USE SIGNAL ;
    PORT
      LAYER M4 ;
        RECT  0 46.8 0.084 46.824 ;
    END
  END a_cfg_data[27]
  PIN a_cfg_data[28]
    DIRECTION OUTPUT ;
    USE SIGNAL ;
    PORT
      LAYER M4 ;
        RECT  0 46.896 0.084 46.92 ;
    END
  END a_cfg_data[28]
  PIN a_cfg_data[29]
    DIRECTION OUTPUT ;
    USE SIGNAL ;
    PORT
      LAYER M4 ;
        RECT  0 46.992 0.084 47.016 ;
    END
  END a_cfg_data[29]
  PIN a_cfg_data[2]
    DIRECTION OUTPUT ;
    USE SIGNAL ;
    PORT
      LAYER M4 ;
        RECT  0 35.184 0.084 35.208 ;
    END
  END a_cfg_data[2]
  PIN a_cfg_data[30]
    DIRECTION OUTPUT ;
    USE SIGNAL ;
    PORT
      LAYER M4 ;
        RECT  0 47.088 0.084 47.112 ;
    END
  END a_cfg_data[30]
  PIN a_cfg_data[31]
    DIRECTION OUTPUT ;
    USE SIGNAL ;
    PORT
      LAYER M4 ;
        RECT  0 47.184 0.084 47.208 ;
    END
  END a_cfg_data[31]
  PIN a_cfg_data[32]
    DIRECTION OUTPUT ;
    USE SIGNAL ;
    PORT
      LAYER M4 ;
        RECT  0 47.28 0.084 47.304 ;
    END
  END a_cfg_data[32]
  PIN a_cfg_data[33]
    DIRECTION OUTPUT ;
    USE SIGNAL ;
    PORT
      LAYER M4 ;
        RECT  0 47.376 0.084 47.4 ;
    END
  END a_cfg_data[33]
  PIN a_cfg_data[34]
    DIRECTION OUTPUT ;
    USE SIGNAL ;
    PORT
      LAYER M4 ;
        RECT  0 47.472 0.084 47.496 ;
    END
  END a_cfg_data[34]
  PIN a_cfg_data[35]
    DIRECTION OUTPUT ;
    USE SIGNAL ;
    PORT
      LAYER M4 ;
        RECT  0 47.568 0.084 47.592 ;
    END
  END a_cfg_data[35]
  PIN a_cfg_data[36]
    DIRECTION OUTPUT ;
    USE SIGNAL ;
    PORT
      LAYER M4 ;
        RECT  0 47.664 0.084 47.688 ;
    END
  END a_cfg_data[36]
  PIN a_cfg_data[37]
    DIRECTION OUTPUT ;
    USE SIGNAL ;
    PORT
      LAYER M4 ;
        RECT  0 47.76 0.084 47.784 ;
    END
  END a_cfg_data[37]
  PIN a_cfg_data[38]
    DIRECTION OUTPUT ;
    USE SIGNAL ;
    PORT
      LAYER M4 ;
        RECT  0 47.856 0.084 47.88 ;
    END
  END a_cfg_data[38]
  PIN a_cfg_data[39]
    DIRECTION OUTPUT ;
    USE SIGNAL ;
    PORT
      LAYER M4 ;
        RECT  0 47.952 0.084 47.976 ;
    END
  END a_cfg_data[39]
  PIN a_cfg_data[3]
    DIRECTION OUTPUT ;
    USE SIGNAL ;
    PORT
      LAYER M4 ;
        RECT  0 35.28 0.084 35.304 ;
    END
  END a_cfg_data[3]
  PIN a_cfg_data[40]
    DIRECTION OUTPUT ;
    USE SIGNAL ;
    PORT
      LAYER M4 ;
        RECT  0 48.048 0.084 48.072 ;
    END
  END a_cfg_data[40]
  PIN a_cfg_data[41]
    DIRECTION OUTPUT ;
    USE SIGNAL ;
    PORT
      LAYER M4 ;
        RECT  0 48.144 0.084 48.168 ;
    END
  END a_cfg_data[41]
  PIN a_cfg_data[42]
    DIRECTION OUTPUT ;
    USE SIGNAL ;
    PORT
      LAYER M4 ;
        RECT  0 48.24 0.084 48.264 ;
    END
  END a_cfg_data[42]
  PIN a_cfg_data[43]
    DIRECTION OUTPUT ;
    USE SIGNAL ;
    PORT
      LAYER M4 ;
        RECT  0 48.336 0.084 48.36 ;
    END
  END a_cfg_data[43]
  PIN a_cfg_data[44]
    DIRECTION OUTPUT ;
    USE SIGNAL ;
    PORT
      LAYER M4 ;
        RECT  0 48.432 0.084 48.456 ;
    END
  END a_cfg_data[44]
  PIN a_cfg_data[45]
    DIRECTION OUTPUT ;
    USE SIGNAL ;
    PORT
      LAYER M4 ;
        RECT  0 48.528 0.084 48.552 ;
    END
  END a_cfg_data[45]
  PIN a_cfg_data[46]
    DIRECTION OUTPUT ;
    USE SIGNAL ;
    PORT
      LAYER M4 ;
        RECT  0 48.624 0.084 48.648 ;
    END
  END a_cfg_data[46]
  PIN a_cfg_data[47]
    DIRECTION OUTPUT ;
    USE SIGNAL ;
    PORT
      LAYER M4 ;
        RECT  0 48.72 0.084 48.744 ;
    END
  END a_cfg_data[47]
  PIN a_cfg_data[48]
    DIRECTION OUTPUT ;
    USE SIGNAL ;
    PORT
      LAYER M4 ;
        RECT  0 48.816 0.084 48.84 ;
    END
  END a_cfg_data[48]
  PIN a_cfg_data[49]
    DIRECTION OUTPUT ;
    USE SIGNAL ;
    PORT
      LAYER M4 ;
        RECT  0 48.912 0.084 48.936 ;
    END
  END a_cfg_data[49]
  PIN a_cfg_data[4]
    DIRECTION OUTPUT ;
    USE SIGNAL ;
    PORT
      LAYER M4 ;
        RECT  0 35.376 0.084 35.4 ;
    END
  END a_cfg_data[4]
  PIN a_cfg_data[50]
    DIRECTION OUTPUT ;
    USE SIGNAL ;
    PORT
      LAYER M4 ;
        RECT  0 49.008 0.084 49.032 ;
    END
  END a_cfg_data[50]
  PIN a_cfg_data[51]
    DIRECTION OUTPUT ;
    USE SIGNAL ;
    PORT
      LAYER M4 ;
        RECT  0 49.104 0.084 49.128 ;
    END
  END a_cfg_data[51]
  PIN a_cfg_data[52]
    DIRECTION OUTPUT ;
    USE SIGNAL ;
    PORT
      LAYER M4 ;
        RECT  0 30.768 0.084 30.792 ;
    END
  END a_cfg_data[52]
  PIN a_cfg_data[53]
    DIRECTION OUTPUT ;
    USE SIGNAL ;
    PORT
      LAYER M4 ;
        RECT  0 30.864 0.084 30.888 ;
    END
  END a_cfg_data[53]
  PIN a_cfg_data[54]
    DIRECTION OUTPUT ;
    USE SIGNAL ;
    PORT
      LAYER M4 ;
        RECT  0 30.96 0.084 30.984 ;
    END
  END a_cfg_data[54]
  PIN a_cfg_data[55]
    DIRECTION OUTPUT ;
    USE SIGNAL ;
    PORT
      LAYER M4 ;
        RECT  0 31.056 0.084 31.08 ;
    END
  END a_cfg_data[55]
  PIN a_cfg_data[56]
    DIRECTION OUTPUT ;
    USE SIGNAL ;
    PORT
      LAYER M4 ;
        RECT  0 31.152 0.084 31.176 ;
    END
  END a_cfg_data[56]
  PIN a_cfg_data[57]
    DIRECTION OUTPUT ;
    USE SIGNAL ;
    PORT
      LAYER M4 ;
        RECT  0 31.248 0.084 31.272 ;
    END
  END a_cfg_data[57]
  PIN a_cfg_data[58]
    DIRECTION OUTPUT ;
    USE SIGNAL ;
    PORT
      LAYER M4 ;
        RECT  0 31.344 0.084 31.368 ;
    END
  END a_cfg_data[58]
  PIN a_cfg_data[59]
    DIRECTION OUTPUT ;
    USE SIGNAL ;
    PORT
      LAYER M4 ;
        RECT  0 31.44 0.084 31.464 ;
    END
  END a_cfg_data[59]
  PIN a_cfg_data[5]
    DIRECTION OUTPUT ;
    USE SIGNAL ;
    PORT
      LAYER M4 ;
        RECT  0 35.472 0.084 35.496 ;
    END
  END a_cfg_data[5]
  PIN a_cfg_data[60]
    DIRECTION OUTPUT ;
    USE SIGNAL ;
    PORT
      LAYER M4 ;
        RECT  0 31.536 0.084 31.56 ;
    END
  END a_cfg_data[60]
  PIN a_cfg_data[61]
    DIRECTION OUTPUT ;
    USE SIGNAL ;
    PORT
      LAYER M4 ;
        RECT  0 31.632 0.084 31.656 ;
    END
  END a_cfg_data[61]
  PIN a_cfg_data[62]
    DIRECTION OUTPUT ;
    USE SIGNAL ;
    PORT
      LAYER M4 ;
        RECT  0 31.728 0.084 31.752 ;
    END
  END a_cfg_data[62]
  PIN a_cfg_data[63]
    DIRECTION OUTPUT ;
    USE SIGNAL ;
    PORT
      LAYER M4 ;
        RECT  0 31.824 0.084 31.848 ;
    END
  END a_cfg_data[63]
  PIN a_cfg_data[64]
    DIRECTION OUTPUT ;
    USE SIGNAL ;
    PORT
      LAYER M4 ;
        RECT  0 31.92 0.084 31.944 ;
    END
  END a_cfg_data[64]
  PIN a_cfg_data[65]
    DIRECTION OUTPUT ;
    USE SIGNAL ;
    PORT
      LAYER M4 ;
        RECT  0 32.016 0.084 32.04 ;
    END
  END a_cfg_data[65]
  PIN a_cfg_data[66]
    DIRECTION OUTPUT ;
    USE SIGNAL ;
    PORT
      LAYER M4 ;
        RECT  0 32.112 0.084 32.136 ;
    END
  END a_cfg_data[66]
  PIN a_cfg_data[67]
    DIRECTION OUTPUT ;
    USE SIGNAL ;
    PORT
      LAYER M4 ;
        RECT  0 32.208 0.084 32.232 ;
    END
  END a_cfg_data[67]
  PIN a_cfg_data[68]
    DIRECTION OUTPUT ;
    USE SIGNAL ;
    PORT
      LAYER M4 ;
        RECT  0 32.304 0.084 32.328 ;
    END
  END a_cfg_data[68]
  PIN a_cfg_data[69]
    DIRECTION OUTPUT ;
    USE SIGNAL ;
    PORT
      LAYER M4 ;
        RECT  0 32.4 0.084 32.424 ;
    END
  END a_cfg_data[69]
  PIN a_cfg_data[6]
    DIRECTION OUTPUT ;
    USE SIGNAL ;
    PORT
      LAYER M4 ;
        RECT  0 35.568 0.084 35.592 ;
    END
  END a_cfg_data[6]
  PIN a_cfg_data[70]
    DIRECTION OUTPUT ;
    USE SIGNAL ;
    PORT
      LAYER M4 ;
        RECT  0 32.496 0.084 32.52 ;
    END
  END a_cfg_data[70]
  PIN a_cfg_data[71]
    DIRECTION OUTPUT ;
    USE SIGNAL ;
    PORT
      LAYER M4 ;
        RECT  0 32.592 0.084 32.616 ;
    END
  END a_cfg_data[71]
  PIN a_cfg_data[72]
    DIRECTION OUTPUT ;
    USE SIGNAL ;
    PORT
      LAYER M4 ;
        RECT  0 32.688 0.084 32.712 ;
    END
  END a_cfg_data[72]
  PIN a_cfg_data[73]
    DIRECTION OUTPUT ;
    USE SIGNAL ;
    PORT
      LAYER M4 ;
        RECT  0 32.784 0.084 32.808 ;
    END
  END a_cfg_data[73]
  PIN a_cfg_data[74]
    DIRECTION OUTPUT ;
    USE SIGNAL ;
    PORT
      LAYER M4 ;
        RECT  0 32.88 0.084 32.904 ;
    END
  END a_cfg_data[74]
  PIN a_cfg_data[75]
    DIRECTION OUTPUT ;
    USE SIGNAL ;
    PORT
      LAYER M4 ;
        RECT  0 32.976 0.084 33 ;
    END
  END a_cfg_data[75]
  PIN a_cfg_data[76]
    DIRECTION OUTPUT ;
    USE SIGNAL ;
    PORT
      LAYER M4 ;
        RECT  0 33.072 0.084 33.096 ;
    END
  END a_cfg_data[76]
  PIN a_cfg_data[77]
    DIRECTION OUTPUT ;
    USE SIGNAL ;
    PORT
      LAYER M4 ;
        RECT  0 33.168 0.084 33.192 ;
    END
  END a_cfg_data[77]
  PIN a_cfg_data[78]
    DIRECTION OUTPUT ;
    USE SIGNAL ;
    PORT
      LAYER M4 ;
        RECT  0 33.264 0.084 33.288 ;
    END
  END a_cfg_data[78]
  PIN a_cfg_data[79]
    DIRECTION OUTPUT ;
    USE SIGNAL ;
    PORT
      LAYER M4 ;
        RECT  0 33.36 0.084 33.384 ;
    END
  END a_cfg_data[79]
  PIN a_cfg_data[7]
    DIRECTION OUTPUT ;
    USE SIGNAL ;
    PORT
      LAYER M4 ;
        RECT  0 35.664 0.084 35.688 ;
    END
  END a_cfg_data[7]
  PIN a_cfg_data[80]
    DIRECTION OUTPUT ;
    USE SIGNAL ;
    PORT
      LAYER M4 ;
        RECT  0 33.456 0.084 33.48 ;
    END
  END a_cfg_data[80]
  PIN a_cfg_data[81]
    DIRECTION OUTPUT ;
    USE SIGNAL ;
    PORT
      LAYER M4 ;
        RECT  0 33.552 0.084 33.576 ;
    END
  END a_cfg_data[81]
  PIN a_cfg_data[82]
    DIRECTION OUTPUT ;
    USE SIGNAL ;
    PORT
      LAYER M4 ;
        RECT  0 33.648 0.084 33.672 ;
    END
  END a_cfg_data[82]
  PIN a_cfg_data[83]
    DIRECTION OUTPUT ;
    USE SIGNAL ;
    PORT
      LAYER M4 ;
        RECT  0 33.744 0.084 33.768 ;
    END
  END a_cfg_data[83]
  PIN a_cfg_data[84]
    DIRECTION OUTPUT ;
    USE SIGNAL ;
    PORT
      LAYER M4 ;
        RECT  0 43.056 0.084 43.08 ;
    END
  END a_cfg_data[84]
  PIN a_cfg_data[85]
    DIRECTION OUTPUT ;
    USE SIGNAL ;
    PORT
      LAYER M4 ;
        RECT  0 43.152 0.084 43.176 ;
    END
  END a_cfg_data[85]
  PIN a_cfg_data[86]
    DIRECTION OUTPUT ;
    USE SIGNAL ;
    PORT
      LAYER M4 ;
        RECT  0 43.248 0.084 43.272 ;
    END
  END a_cfg_data[86]
  PIN a_cfg_data[87]
    DIRECTION OUTPUT ;
    USE SIGNAL ;
    PORT
      LAYER M4 ;
        RECT  0 43.344 0.084 43.368 ;
    END
  END a_cfg_data[87]
  PIN a_cfg_data[88]
    DIRECTION OUTPUT ;
    USE SIGNAL ;
    PORT
      LAYER M4 ;
        RECT  0 43.44 0.084 43.464 ;
    END
  END a_cfg_data[88]
  PIN a_cfg_data[89]
    DIRECTION OUTPUT ;
    USE SIGNAL ;
    PORT
      LAYER M4 ;
        RECT  0 43.536 0.084 43.56 ;
    END
  END a_cfg_data[89]
  PIN a_cfg_data[8]
    DIRECTION OUTPUT ;
    USE SIGNAL ;
    PORT
      LAYER M4 ;
        RECT  0 35.76 0.084 35.784 ;
    END
  END a_cfg_data[8]
  PIN a_cfg_data[90]
    DIRECTION OUTPUT ;
    USE SIGNAL ;
    PORT
      LAYER M4 ;
        RECT  0 43.632 0.084 43.656 ;
    END
  END a_cfg_data[90]
  PIN a_cfg_data[91]
    DIRECTION OUTPUT ;
    USE SIGNAL ;
    PORT
      LAYER M4 ;
        RECT  0 43.728 0.084 43.752 ;
    END
  END a_cfg_data[91]
  PIN a_cfg_data[92]
    DIRECTION OUTPUT ;
    USE SIGNAL ;
    PORT
      LAYER M4 ;
        RECT  0 43.824 0.084 43.848 ;
    END
  END a_cfg_data[92]
  PIN a_cfg_data[93]
    DIRECTION OUTPUT ;
    USE SIGNAL ;
    PORT
      LAYER M4 ;
        RECT  0 43.92 0.084 43.944 ;
    END
  END a_cfg_data[93]
  PIN a_cfg_data[94]
    DIRECTION OUTPUT ;
    USE SIGNAL ;
    PORT
      LAYER M4 ;
        RECT  0 44.016 0.084 44.04 ;
    END
  END a_cfg_data[94]
  PIN a_cfg_data[95]
    DIRECTION OUTPUT ;
    USE SIGNAL ;
    PORT
      LAYER M4 ;
        RECT  0 44.112 0.084 44.136 ;
    END
  END a_cfg_data[95]
  PIN a_cfg_data[96]
    DIRECTION OUTPUT ;
    USE SIGNAL ;
    PORT
      LAYER M4 ;
        RECT  0 44.208 0.084 44.232 ;
    END
  END a_cfg_data[96]
  PIN a_cfg_data[97]
    DIRECTION OUTPUT ;
    USE SIGNAL ;
    PORT
      LAYER M4 ;
        RECT  0 44.304 0.084 44.328 ;
    END
  END a_cfg_data[97]
  PIN a_cfg_data[98]
    DIRECTION OUTPUT ;
    USE SIGNAL ;
    PORT
      LAYER M4 ;
        RECT  0 44.4 0.084 44.424 ;
    END
  END a_cfg_data[98]
  PIN a_cfg_data[99]
    DIRECTION OUTPUT ;
    USE SIGNAL ;
    PORT
      LAYER M4 ;
        RECT  0 44.496 0.084 44.52 ;
    END
  END a_cfg_data[99]
  PIN a_cfg_data[9]
    DIRECTION OUTPUT ;
    USE SIGNAL ;
    PORT
      LAYER M4 ;
        RECT  0 35.856 0.084 35.88 ;
    END
  END a_cfg_data[9]
  PIN a_cfg_target[0]
    DIRECTION OUTPUT ;
    USE SIGNAL ;
    PORT
      LAYER M4 ;
        RECT  0 18.864 0.084 18.888 ;
    END
  END a_cfg_target[0]
  PIN a_cfg_target[1]
    DIRECTION OUTPUT ;
    USE SIGNAL ;
    PORT
      LAYER M4 ;
        RECT  0 18.96 0.084 18.984 ;
    END
  END a_cfg_target[1]
  PIN a_cfg_target[2]
    DIRECTION OUTPUT ;
    USE SIGNAL ;
    PORT
      LAYER M4 ;
        RECT  0 19.056 0.084 19.08 ;
    END
  END a_cfg_target[2]
  PIN a_cfg_target[3]
    DIRECTION OUTPUT ;
    USE SIGNAL ;
    PORT
      LAYER M4 ;
        RECT  0 19.152 0.084 19.176 ;
    END
  END a_cfg_target[3]
  PIN a_cfg_target[4]
    DIRECTION OUTPUT ;
    USE SIGNAL ;
    PORT
      LAYER M4 ;
        RECT  0 19.248 0.084 19.272 ;
    END
  END a_cfg_target[4]
  PIN a_cfg_target[5]
    DIRECTION OUTPUT ;
    USE SIGNAL ;
    PORT
      LAYER M4 ;
        RECT  0 19.344 0.084 19.368 ;
    END
  END a_cfg_target[5]
  PIN a_cfg_target[6]
    DIRECTION OUTPUT ;
    USE SIGNAL ;
    PORT
      LAYER M4 ;
        RECT  0 19.44 0.084 19.464 ;
    END
  END a_cfg_target[6]
  PIN a_cfg_target[7]
    DIRECTION OUTPUT ;
    USE SIGNAL ;
    PORT
      LAYER M4 ;
        RECT  0 19.536 0.084 19.56 ;
    END
  END a_cfg_target[7]
  PIN a_cfg_v
    DIRECTION OUTPUT ;
    USE SIGNAL ;
    PORT
      LAYER M4 ;
        RECT  0 19.632 0.084 19.656 ;
    END
  END a_cfg_v
  PIN a_desc_base[0]
    DIRECTION OUTPUT ;
    USE SIGNAL ;
    PORT
      LAYER M4 ;
        RECT  0 19.728 0.084 19.752 ;
    END
  END a_desc_base[0]
  PIN a_desc_base[10]
    DIRECTION OUTPUT ;
    USE SIGNAL ;
    PORT
      LAYER M4 ;
        RECT  0 20.688 0.084 20.712 ;
    END
  END a_desc_base[10]
  PIN a_desc_base[11]
    DIRECTION OUTPUT ;
    USE SIGNAL ;
    PORT
      LAYER M4 ;
        RECT  0 23.856 0.084 23.88 ;
    END
  END a_desc_base[11]
  PIN a_desc_base[1]
    DIRECTION OUTPUT ;
    USE SIGNAL ;
    PORT
      LAYER M4 ;
        RECT  0 19.824 0.084 19.848 ;
    END
  END a_desc_base[1]
  PIN a_desc_base[2]
    DIRECTION OUTPUT ;
    USE SIGNAL ;
    PORT
      LAYER M4 ;
        RECT  0 19.92 0.084 19.944 ;
    END
  END a_desc_base[2]
  PIN a_desc_base[3]
    DIRECTION OUTPUT ;
    USE SIGNAL ;
    PORT
      LAYER M4 ;
        RECT  0 20.016 0.084 20.04 ;
    END
  END a_desc_base[3]
  PIN a_desc_base[4]
    DIRECTION OUTPUT ;
    USE SIGNAL ;
    PORT
      LAYER M4 ;
        RECT  0 20.112 0.084 20.136 ;
    END
  END a_desc_base[4]
  PIN a_desc_base[5]
    DIRECTION OUTPUT ;
    USE SIGNAL ;
    PORT
      LAYER M4 ;
        RECT  0 20.208 0.084 20.232 ;
    END
  END a_desc_base[5]
  PIN a_desc_base[6]
    DIRECTION OUTPUT ;
    USE SIGNAL ;
    PORT
      LAYER M4 ;
        RECT  0 20.304 0.084 20.328 ;
    END
  END a_desc_base[6]
  PIN a_desc_base[7]
    DIRECTION OUTPUT ;
    USE SIGNAL ;
    PORT
      LAYER M4 ;
        RECT  0 20.4 0.084 20.424 ;
    END
  END a_desc_base[7]
  PIN a_desc_base[8]
    DIRECTION OUTPUT ;
    USE SIGNAL ;
    PORT
      LAYER M4 ;
        RECT  0 20.496 0.084 20.52 ;
    END
  END a_desc_base[8]
  PIN a_desc_base[9]
    DIRECTION OUTPUT ;
    USE SIGNAL ;
    PORT
      LAYER M4 ;
        RECT  0 20.592 0.084 20.616 ;
    END
  END a_desc_base[9]
  PIN a_desc_limit[0]
    DIRECTION OUTPUT ;
    USE SIGNAL ;
    PORT
      LAYER M4 ;
        RECT  0 23.952 0.084 23.976 ;
    END
  END a_desc_limit[0]
  PIN a_desc_limit[10]
    DIRECTION OUTPUT ;
    USE SIGNAL ;
    PORT
      LAYER M4 ;
        RECT  0 24.912 0.084 24.936 ;
    END
  END a_desc_limit[10]
  PIN a_desc_limit[11]
    DIRECTION OUTPUT ;
    USE SIGNAL ;
    PORT
      LAYER M4 ;
        RECT  0 25.008 0.084 25.032 ;
    END
  END a_desc_limit[11]
  PIN a_desc_limit[12]
    DIRECTION OUTPUT ;
    USE SIGNAL ;
    PORT
      LAYER M4 ;
        RECT  0 25.104 0.084 25.128 ;
    END
  END a_desc_limit[12]
  PIN a_desc_limit[1]
    DIRECTION OUTPUT ;
    USE SIGNAL ;
    PORT
      LAYER M4 ;
        RECT  0 24.048 0.084 24.072 ;
    END
  END a_desc_limit[1]
  PIN a_desc_limit[2]
    DIRECTION OUTPUT ;
    USE SIGNAL ;
    PORT
      LAYER M4 ;
        RECT  0 24.144 0.084 24.168 ;
    END
  END a_desc_limit[2]
  PIN a_desc_limit[3]
    DIRECTION OUTPUT ;
    USE SIGNAL ;
    PORT
      LAYER M4 ;
        RECT  0 24.24 0.084 24.264 ;
    END
  END a_desc_limit[3]
  PIN a_desc_limit[4]
    DIRECTION OUTPUT ;
    USE SIGNAL ;
    PORT
      LAYER M4 ;
        RECT  0 24.336 0.084 24.36 ;
    END
  END a_desc_limit[4]
  PIN a_desc_limit[5]
    DIRECTION OUTPUT ;
    USE SIGNAL ;
    PORT
      LAYER M4 ;
        RECT  0 24.432 0.084 24.456 ;
    END
  END a_desc_limit[5]
  PIN a_desc_limit[6]
    DIRECTION OUTPUT ;
    USE SIGNAL ;
    PORT
      LAYER M4 ;
        RECT  0 24.528 0.084 24.552 ;
    END
  END a_desc_limit[6]
  PIN a_desc_limit[7]
    DIRECTION OUTPUT ;
    USE SIGNAL ;
    PORT
      LAYER M4 ;
        RECT  0 24.624 0.084 24.648 ;
    END
  END a_desc_limit[7]
  PIN a_desc_limit[8]
    DIRECTION OUTPUT ;
    USE SIGNAL ;
    PORT
      LAYER M4 ;
        RECT  0 24.72 0.084 24.744 ;
    END
  END a_desc_limit[8]
  PIN a_desc_limit[9]
    DIRECTION OUTPUT ;
    USE SIGNAL ;
    PORT
      LAYER M4 ;
        RECT  0 24.816 0.084 24.84 ;
    END
  END a_desc_limit[9]
  PIN a_desc_loops[0]
    DIRECTION OUTPUT ;
    USE SIGNAL ;
    PORT
      LAYER M4 ;
        RECT  0 25.2 0.084 25.224 ;
    END
  END a_desc_loops[0]
  PIN a_desc_loops[10]
    DIRECTION OUTPUT ;
    USE SIGNAL ;
    PORT
      LAYER M4 ;
        RECT  0 26.16 0.084 26.184 ;
    END
  END a_desc_loops[10]
  PIN a_desc_loops[11]
    DIRECTION OUTPUT ;
    USE SIGNAL ;
    PORT
      LAYER M4 ;
        RECT  0 26.256 0.084 26.28 ;
    END
  END a_desc_loops[11]
  PIN a_desc_loops[12]
    DIRECTION OUTPUT ;
    USE SIGNAL ;
    PORT
      LAYER M4 ;
        RECT  0 26.352 0.084 26.376 ;
    END
  END a_desc_loops[12]
  PIN a_desc_loops[13]
    DIRECTION OUTPUT ;
    USE SIGNAL ;
    PORT
      LAYER M4 ;
        RECT  0 26.448 0.084 26.472 ;
    END
  END a_desc_loops[13]
  PIN a_desc_loops[14]
    DIRECTION OUTPUT ;
    USE SIGNAL ;
    PORT
      LAYER M4 ;
        RECT  0 26.544 0.084 26.568 ;
    END
  END a_desc_loops[14]
  PIN a_desc_loops[15]
    DIRECTION OUTPUT ;
    USE SIGNAL ;
    PORT
      LAYER M4 ;
        RECT  0 26.64 0.084 26.664 ;
    END
  END a_desc_loops[15]
  PIN a_desc_loops[1]
    DIRECTION OUTPUT ;
    USE SIGNAL ;
    PORT
      LAYER M4 ;
        RECT  0 25.296 0.084 25.32 ;
    END
  END a_desc_loops[1]
  PIN a_desc_loops[2]
    DIRECTION OUTPUT ;
    USE SIGNAL ;
    PORT
      LAYER M4 ;
        RECT  0 25.392 0.084 25.416 ;
    END
  END a_desc_loops[2]
  PIN a_desc_loops[3]
    DIRECTION OUTPUT ;
    USE SIGNAL ;
    PORT
      LAYER M4 ;
        RECT  0 25.488 0.084 25.512 ;
    END
  END a_desc_loops[3]
  PIN a_desc_loops[4]
    DIRECTION OUTPUT ;
    USE SIGNAL ;
    PORT
      LAYER M4 ;
        RECT  0 25.584 0.084 25.608 ;
    END
  END a_desc_loops[4]
  PIN a_desc_loops[5]
    DIRECTION OUTPUT ;
    USE SIGNAL ;
    PORT
      LAYER M4 ;
        RECT  0 25.68 0.084 25.704 ;
    END
  END a_desc_loops[5]
  PIN a_desc_loops[6]
    DIRECTION OUTPUT ;
    USE SIGNAL ;
    PORT
      LAYER M4 ;
        RECT  0 25.776 0.084 25.8 ;
    END
  END a_desc_loops[6]
  PIN a_desc_loops[7]
    DIRECTION OUTPUT ;
    USE SIGNAL ;
    PORT
      LAYER M4 ;
        RECT  0 25.872 0.084 25.896 ;
    END
  END a_desc_loops[7]
  PIN a_desc_loops[8]
    DIRECTION OUTPUT ;
    USE SIGNAL ;
    PORT
      LAYER M4 ;
        RECT  0 25.968 0.084 25.992 ;
    END
  END a_desc_loops[8]
  PIN a_desc_loops[9]
    DIRECTION OUTPUT ;
    USE SIGNAL ;
    PORT
      LAYER M4 ;
        RECT  0 26.064 0.084 26.088 ;
    END
  END a_desc_loops[9]
  PIN a_desc_v
    DIRECTION OUTPUT ;
    USE SIGNAL ;
    PORT
      LAYER M4 ;
        RECT  0 26.736 0.084 26.76 ;
    END
  END a_desc_v
  PIN a_launch_v
    DIRECTION OUTPUT ;
    USE SIGNAL ;
    PORT
      LAYER M4 ;
        RECT  0 26.832 0.084 26.856 ;
    END
  END a_launch_v
  PIN b_cfg_addr[0]
    DIRECTION OUTPUT ;
    USE SIGNAL ;
    PORT
      LAYER M4 ;
        RECT  69.036 35.28 69.12 35.304 ;
    END
  END b_cfg_addr[0]
  PIN b_cfg_addr[10]
    DIRECTION OUTPUT ;
    USE SIGNAL ;
    PORT
      LAYER M4 ;
        RECT  69.036 36.24 69.12 36.264 ;
    END
  END b_cfg_addr[10]
  PIN b_cfg_addr[11]
    DIRECTION OUTPUT ;
    USE SIGNAL ;
    PORT
      LAYER M4 ;
        RECT  69.036 36.336 69.12 36.36 ;
    END
  END b_cfg_addr[11]
  PIN b_cfg_addr[1]
    DIRECTION OUTPUT ;
    USE SIGNAL ;
    PORT
      LAYER M4 ;
        RECT  69.036 35.376 69.12 35.4 ;
    END
  END b_cfg_addr[1]
  PIN b_cfg_addr[2]
    DIRECTION OUTPUT ;
    USE SIGNAL ;
    PORT
      LAYER M4 ;
        RECT  69.036 35.472 69.12 35.496 ;
    END
  END b_cfg_addr[2]
  PIN b_cfg_addr[3]
    DIRECTION OUTPUT ;
    USE SIGNAL ;
    PORT
      LAYER M4 ;
        RECT  69.036 35.568 69.12 35.592 ;
    END
  END b_cfg_addr[3]
  PIN b_cfg_addr[4]
    DIRECTION OUTPUT ;
    USE SIGNAL ;
    PORT
      LAYER M4 ;
        RECT  69.036 35.664 69.12 35.688 ;
    END
  END b_cfg_addr[4]
  PIN b_cfg_addr[5]
    DIRECTION OUTPUT ;
    USE SIGNAL ;
    PORT
      LAYER M4 ;
        RECT  69.036 35.76 69.12 35.784 ;
    END
  END b_cfg_addr[5]
  PIN b_cfg_addr[6]
    DIRECTION OUTPUT ;
    USE SIGNAL ;
    PORT
      LAYER M4 ;
        RECT  69.036 35.856 69.12 35.88 ;
    END
  END b_cfg_addr[6]
  PIN b_cfg_addr[7]
    DIRECTION OUTPUT ;
    USE SIGNAL ;
    PORT
      LAYER M4 ;
        RECT  69.036 35.952 69.12 35.976 ;
    END
  END b_cfg_addr[7]
  PIN b_cfg_addr[8]
    DIRECTION OUTPUT ;
    USE SIGNAL ;
    PORT
      LAYER M4 ;
        RECT  69.036 36.048 69.12 36.072 ;
    END
  END b_cfg_addr[8]
  PIN b_cfg_addr[9]
    DIRECTION OUTPUT ;
    USE SIGNAL ;
    PORT
      LAYER M4 ;
        RECT  69.036 36.144 69.12 36.168 ;
    END
  END b_cfg_addr[9]
  PIN b_cfg_data[0]
    DIRECTION OUTPUT ;
    USE SIGNAL ;
    PORT
      LAYER M4 ;
        RECT  69.036 36.432 69.12 36.456 ;
    END
  END b_cfg_data[0]
  PIN b_cfg_data[100]
    DIRECTION OUTPUT ;
    USE SIGNAL ;
    PORT
      LAYER M4 ;
        RECT  69.036 49.872 69.12 49.896 ;
    END
  END b_cfg_data[100]
  PIN b_cfg_data[101]
    DIRECTION OUTPUT ;
    USE SIGNAL ;
    PORT
      LAYER M4 ;
        RECT  69.036 49.968 69.12 49.992 ;
    END
  END b_cfg_data[101]
  PIN b_cfg_data[102]
    DIRECTION OUTPUT ;
    USE SIGNAL ;
    PORT
      LAYER M4 ;
        RECT  69.036 50.064 69.12 50.088 ;
    END
  END b_cfg_data[102]
  PIN b_cfg_data[103]
    DIRECTION OUTPUT ;
    USE SIGNAL ;
    PORT
      LAYER M4 ;
        RECT  69.036 50.16 69.12 50.184 ;
    END
  END b_cfg_data[103]
  PIN b_cfg_data[104]
    DIRECTION OUTPUT ;
    USE SIGNAL ;
    PORT
      LAYER M4 ;
        RECT  69.036 50.256 69.12 50.28 ;
    END
  END b_cfg_data[104]
  PIN b_cfg_data[105]
    DIRECTION OUTPUT ;
    USE SIGNAL ;
    PORT
      LAYER M4 ;
        RECT  69.036 50.352 69.12 50.376 ;
    END
  END b_cfg_data[105]
  PIN b_cfg_data[106]
    DIRECTION OUTPUT ;
    USE SIGNAL ;
    PORT
      LAYER M4 ;
        RECT  69.036 50.448 69.12 50.472 ;
    END
  END b_cfg_data[106]
  PIN b_cfg_data[107]
    DIRECTION OUTPUT ;
    USE SIGNAL ;
    PORT
      LAYER M4 ;
        RECT  69.036 50.544 69.12 50.568 ;
    END
  END b_cfg_data[107]
  PIN b_cfg_data[108]
    DIRECTION OUTPUT ;
    USE SIGNAL ;
    PORT
      LAYER M4 ;
        RECT  69.036 50.64 69.12 50.664 ;
    END
  END b_cfg_data[108]
  PIN b_cfg_data[109]
    DIRECTION OUTPUT ;
    USE SIGNAL ;
    PORT
      LAYER M4 ;
        RECT  69.036 50.736 69.12 50.76 ;
    END
  END b_cfg_data[109]
  PIN b_cfg_data[10]
    DIRECTION OUTPUT ;
    USE SIGNAL ;
    PORT
      LAYER M4 ;
        RECT  69.036 37.392 69.12 37.416 ;
    END
  END b_cfg_data[10]
  PIN b_cfg_data[110]
    DIRECTION OUTPUT ;
    USE SIGNAL ;
    PORT
      LAYER M4 ;
        RECT  69.036 50.832 69.12 50.856 ;
    END
  END b_cfg_data[110]
  PIN b_cfg_data[111]
    DIRECTION OUTPUT ;
    USE SIGNAL ;
    PORT
      LAYER M4 ;
        RECT  69.036 50.928 69.12 50.952 ;
    END
  END b_cfg_data[111]
  PIN b_cfg_data[112]
    DIRECTION OUTPUT ;
    USE SIGNAL ;
    PORT
      LAYER M4 ;
        RECT  69.036 51.024 69.12 51.048 ;
    END
  END b_cfg_data[112]
  PIN b_cfg_data[113]
    DIRECTION OUTPUT ;
    USE SIGNAL ;
    PORT
      LAYER M4 ;
        RECT  69.036 51.12 69.12 51.144 ;
    END
  END b_cfg_data[113]
  PIN b_cfg_data[114]
    DIRECTION OUTPUT ;
    USE SIGNAL ;
    PORT
      LAYER M4 ;
        RECT  69.036 51.216 69.12 51.24 ;
    END
  END b_cfg_data[114]
  PIN b_cfg_data[115]
    DIRECTION OUTPUT ;
    USE SIGNAL ;
    PORT
      LAYER M4 ;
        RECT  69.036 51.312 69.12 51.336 ;
    END
  END b_cfg_data[115]
  PIN b_cfg_data[116]
    DIRECTION OUTPUT ;
    USE SIGNAL ;
    PORT
      LAYER M4 ;
        RECT  69.036 45.264 69.12 45.288 ;
    END
  END b_cfg_data[116]
  PIN b_cfg_data[117]
    DIRECTION OUTPUT ;
    USE SIGNAL ;
    PORT
      LAYER M4 ;
        RECT  69.036 45.36 69.12 45.384 ;
    END
  END b_cfg_data[117]
  PIN b_cfg_data[118]
    DIRECTION OUTPUT ;
    USE SIGNAL ;
    PORT
      LAYER M4 ;
        RECT  69.036 45.456 69.12 45.48 ;
    END
  END b_cfg_data[118]
  PIN b_cfg_data[119]
    DIRECTION OUTPUT ;
    USE SIGNAL ;
    PORT
      LAYER M4 ;
        RECT  69.036 45.552 69.12 45.576 ;
    END
  END b_cfg_data[119]
  PIN b_cfg_data[11]
    DIRECTION OUTPUT ;
    USE SIGNAL ;
    PORT
      LAYER M4 ;
        RECT  69.036 37.488 69.12 37.512 ;
    END
  END b_cfg_data[11]
  PIN b_cfg_data[120]
    DIRECTION OUTPUT ;
    USE SIGNAL ;
    PORT
      LAYER M4 ;
        RECT  69.036 45.648 69.12 45.672 ;
    END
  END b_cfg_data[120]
  PIN b_cfg_data[121]
    DIRECTION OUTPUT ;
    USE SIGNAL ;
    PORT
      LAYER M4 ;
        RECT  69.036 45.744 69.12 45.768 ;
    END
  END b_cfg_data[121]
  PIN b_cfg_data[122]
    DIRECTION OUTPUT ;
    USE SIGNAL ;
    PORT
      LAYER M4 ;
        RECT  69.036 45.84 69.12 45.864 ;
    END
  END b_cfg_data[122]
  PIN b_cfg_data[123]
    DIRECTION OUTPUT ;
    USE SIGNAL ;
    PORT
      LAYER M4 ;
        RECT  69.036 45.936 69.12 45.96 ;
    END
  END b_cfg_data[123]
  PIN b_cfg_data[124]
    DIRECTION OUTPUT ;
    USE SIGNAL ;
    PORT
      LAYER M4 ;
        RECT  69.036 46.032 69.12 46.056 ;
    END
  END b_cfg_data[124]
  PIN b_cfg_data[125]
    DIRECTION OUTPUT ;
    USE SIGNAL ;
    PORT
      LAYER M4 ;
        RECT  69.036 46.128 69.12 46.152 ;
    END
  END b_cfg_data[125]
  PIN b_cfg_data[126]
    DIRECTION OUTPUT ;
    USE SIGNAL ;
    PORT
      LAYER M4 ;
        RECT  69.036 46.224 69.12 46.248 ;
    END
  END b_cfg_data[126]
  PIN b_cfg_data[127]
    DIRECTION OUTPUT ;
    USE SIGNAL ;
    PORT
      LAYER M4 ;
        RECT  69.036 46.32 69.12 46.344 ;
    END
  END b_cfg_data[127]
  PIN b_cfg_data[128]
    DIRECTION OUTPUT ;
    USE SIGNAL ;
    PORT
      LAYER M4 ;
        RECT  69.036 46.416 69.12 46.44 ;
    END
  END b_cfg_data[128]
  PIN b_cfg_data[129]
    DIRECTION OUTPUT ;
    USE SIGNAL ;
    PORT
      LAYER M4 ;
        RECT  69.036 46.512 69.12 46.536 ;
    END
  END b_cfg_data[129]
  PIN b_cfg_data[12]
    DIRECTION OUTPUT ;
    USE SIGNAL ;
    PORT
      LAYER M4 ;
        RECT  69.036 37.584 69.12 37.608 ;
    END
  END b_cfg_data[12]
  PIN b_cfg_data[130]
    DIRECTION OUTPUT ;
    USE SIGNAL ;
    PORT
      LAYER M4 ;
        RECT  69.036 46.608 69.12 46.632 ;
    END
  END b_cfg_data[130]
  PIN b_cfg_data[131]
    DIRECTION OUTPUT ;
    USE SIGNAL ;
    PORT
      LAYER M4 ;
        RECT  69.036 46.704 69.12 46.728 ;
    END
  END b_cfg_data[131]
  PIN b_cfg_data[132]
    DIRECTION OUTPUT ;
    USE SIGNAL ;
    PORT
      LAYER M4 ;
        RECT  69.036 46.8 69.12 46.824 ;
    END
  END b_cfg_data[132]
  PIN b_cfg_data[133]
    DIRECTION OUTPUT ;
    USE SIGNAL ;
    PORT
      LAYER M4 ;
        RECT  69.036 46.896 69.12 46.92 ;
    END
  END b_cfg_data[133]
  PIN b_cfg_data[134]
    DIRECTION OUTPUT ;
    USE SIGNAL ;
    PORT
      LAYER M4 ;
        RECT  69.036 46.992 69.12 47.016 ;
    END
  END b_cfg_data[134]
  PIN b_cfg_data[135]
    DIRECTION OUTPUT ;
    USE SIGNAL ;
    PORT
      LAYER M4 ;
        RECT  69.036 47.088 69.12 47.112 ;
    END
  END b_cfg_data[135]
  PIN b_cfg_data[136]
    DIRECTION OUTPUT ;
    USE SIGNAL ;
    PORT
      LAYER M4 ;
        RECT  69.036 47.184 69.12 47.208 ;
    END
  END b_cfg_data[136]
  PIN b_cfg_data[137]
    DIRECTION OUTPUT ;
    USE SIGNAL ;
    PORT
      LAYER M4 ;
        RECT  69.036 47.28 69.12 47.304 ;
    END
  END b_cfg_data[137]
  PIN b_cfg_data[138]
    DIRECTION OUTPUT ;
    USE SIGNAL ;
    PORT
      LAYER M4 ;
        RECT  69.036 47.376 69.12 47.4 ;
    END
  END b_cfg_data[138]
  PIN b_cfg_data[139]
    DIRECTION OUTPUT ;
    USE SIGNAL ;
    PORT
      LAYER M4 ;
        RECT  69.036 47.472 69.12 47.496 ;
    END
  END b_cfg_data[139]
  PIN b_cfg_data[13]
    DIRECTION OUTPUT ;
    USE SIGNAL ;
    PORT
      LAYER M4 ;
        RECT  69.036 37.68 69.12 37.704 ;
    END
  END b_cfg_data[13]
  PIN b_cfg_data[140]
    DIRECTION OUTPUT ;
    USE SIGNAL ;
    PORT
      LAYER M4 ;
        RECT  69.036 47.568 69.12 47.592 ;
    END
  END b_cfg_data[140]
  PIN b_cfg_data[141]
    DIRECTION OUTPUT ;
    USE SIGNAL ;
    PORT
      LAYER M4 ;
        RECT  69.036 47.664 69.12 47.688 ;
    END
  END b_cfg_data[141]
  PIN b_cfg_data[142]
    DIRECTION OUTPUT ;
    USE SIGNAL ;
    PORT
      LAYER M4 ;
        RECT  69.036 47.76 69.12 47.784 ;
    END
  END b_cfg_data[142]
  PIN b_cfg_data[143]
    DIRECTION OUTPUT ;
    USE SIGNAL ;
    PORT
      LAYER M4 ;
        RECT  69.036 47.856 69.12 47.88 ;
    END
  END b_cfg_data[143]
  PIN b_cfg_data[144]
    DIRECTION OUTPUT ;
    USE SIGNAL ;
    PORT
      LAYER M4 ;
        RECT  69.036 47.952 69.12 47.976 ;
    END
  END b_cfg_data[144]
  PIN b_cfg_data[145]
    DIRECTION OUTPUT ;
    USE SIGNAL ;
    PORT
      LAYER M4 ;
        RECT  69.036 48.048 69.12 48.072 ;
    END
  END b_cfg_data[145]
  PIN b_cfg_data[146]
    DIRECTION OUTPUT ;
    USE SIGNAL ;
    PORT
      LAYER M4 ;
        RECT  69.036 48.144 69.12 48.168 ;
    END
  END b_cfg_data[146]
  PIN b_cfg_data[147]
    DIRECTION OUTPUT ;
    USE SIGNAL ;
    PORT
      LAYER M4 ;
        RECT  69.036 48.24 69.12 48.264 ;
    END
  END b_cfg_data[147]
  PIN b_cfg_data[148]
    DIRECTION OUTPUT ;
    USE SIGNAL ;
    PORT
      LAYER M4 ;
        RECT  69.036 29.136 69.12 29.16 ;
    END
  END b_cfg_data[148]
  PIN b_cfg_data[149]
    DIRECTION OUTPUT ;
    USE SIGNAL ;
    PORT
      LAYER M4 ;
        RECT  69.036 29.232 69.12 29.256 ;
    END
  END b_cfg_data[149]
  PIN b_cfg_data[14]
    DIRECTION OUTPUT ;
    USE SIGNAL ;
    PORT
      LAYER M4 ;
        RECT  69.036 37.776 69.12 37.8 ;
    END
  END b_cfg_data[14]
  PIN b_cfg_data[150]
    DIRECTION OUTPUT ;
    USE SIGNAL ;
    PORT
      LAYER M4 ;
        RECT  69.036 29.328 69.12 29.352 ;
    END
  END b_cfg_data[150]
  PIN b_cfg_data[151]
    DIRECTION OUTPUT ;
    USE SIGNAL ;
    PORT
      LAYER M4 ;
        RECT  69.036 29.424 69.12 29.448 ;
    END
  END b_cfg_data[151]
  PIN b_cfg_data[152]
    DIRECTION OUTPUT ;
    USE SIGNAL ;
    PORT
      LAYER M4 ;
        RECT  69.036 29.52 69.12 29.544 ;
    END
  END b_cfg_data[152]
  PIN b_cfg_data[153]
    DIRECTION OUTPUT ;
    USE SIGNAL ;
    PORT
      LAYER M4 ;
        RECT  69.036 29.616 69.12 29.64 ;
    END
  END b_cfg_data[153]
  PIN b_cfg_data[154]
    DIRECTION OUTPUT ;
    USE SIGNAL ;
    PORT
      LAYER M4 ;
        RECT  69.036 29.712 69.12 29.736 ;
    END
  END b_cfg_data[154]
  PIN b_cfg_data[155]
    DIRECTION OUTPUT ;
    USE SIGNAL ;
    PORT
      LAYER M4 ;
        RECT  69.036 29.808 69.12 29.832 ;
    END
  END b_cfg_data[155]
  PIN b_cfg_data[156]
    DIRECTION OUTPUT ;
    USE SIGNAL ;
    PORT
      LAYER M4 ;
        RECT  69.036 29.904 69.12 29.928 ;
    END
  END b_cfg_data[156]
  PIN b_cfg_data[157]
    DIRECTION OUTPUT ;
    USE SIGNAL ;
    PORT
      LAYER M4 ;
        RECT  69.036 30 69.12 30.024 ;
    END
  END b_cfg_data[157]
  PIN b_cfg_data[158]
    DIRECTION OUTPUT ;
    USE SIGNAL ;
    PORT
      LAYER M4 ;
        RECT  69.036 30.096 69.12 30.12 ;
    END
  END b_cfg_data[158]
  PIN b_cfg_data[159]
    DIRECTION OUTPUT ;
    USE SIGNAL ;
    PORT
      LAYER M4 ;
        RECT  69.036 30.192 69.12 30.216 ;
    END
  END b_cfg_data[159]
  PIN b_cfg_data[15]
    DIRECTION OUTPUT ;
    USE SIGNAL ;
    PORT
      LAYER M4 ;
        RECT  69.036 37.872 69.12 37.896 ;
    END
  END b_cfg_data[15]
  PIN b_cfg_data[160]
    DIRECTION OUTPUT ;
    USE SIGNAL ;
    PORT
      LAYER M4 ;
        RECT  69.036 30.288 69.12 30.312 ;
    END
  END b_cfg_data[160]
  PIN b_cfg_data[161]
    DIRECTION OUTPUT ;
    USE SIGNAL ;
    PORT
      LAYER M4 ;
        RECT  69.036 30.384 69.12 30.408 ;
    END
  END b_cfg_data[161]
  PIN b_cfg_data[162]
    DIRECTION OUTPUT ;
    USE SIGNAL ;
    PORT
      LAYER M4 ;
        RECT  69.036 30.48 69.12 30.504 ;
    END
  END b_cfg_data[162]
  PIN b_cfg_data[163]
    DIRECTION OUTPUT ;
    USE SIGNAL ;
    PORT
      LAYER M4 ;
        RECT  69.036 30.576 69.12 30.6 ;
    END
  END b_cfg_data[163]
  PIN b_cfg_data[164]
    DIRECTION OUTPUT ;
    USE SIGNAL ;
    PORT
      LAYER M4 ;
        RECT  69.036 30.672 69.12 30.696 ;
    END
  END b_cfg_data[164]
  PIN b_cfg_data[165]
    DIRECTION OUTPUT ;
    USE SIGNAL ;
    PORT
      LAYER M4 ;
        RECT  69.036 30.768 69.12 30.792 ;
    END
  END b_cfg_data[165]
  PIN b_cfg_data[166]
    DIRECTION OUTPUT ;
    USE SIGNAL ;
    PORT
      LAYER M4 ;
        RECT  69.036 30.864 69.12 30.888 ;
    END
  END b_cfg_data[166]
  PIN b_cfg_data[167]
    DIRECTION OUTPUT ;
    USE SIGNAL ;
    PORT
      LAYER M4 ;
        RECT  69.036 30.96 69.12 30.984 ;
    END
  END b_cfg_data[167]
  PIN b_cfg_data[168]
    DIRECTION OUTPUT ;
    USE SIGNAL ;
    PORT
      LAYER M4 ;
        RECT  69.036 31.056 69.12 31.08 ;
    END
  END b_cfg_data[168]
  PIN b_cfg_data[169]
    DIRECTION OUTPUT ;
    USE SIGNAL ;
    PORT
      LAYER M4 ;
        RECT  69.036 31.152 69.12 31.176 ;
    END
  END b_cfg_data[169]
  PIN b_cfg_data[16]
    DIRECTION OUTPUT ;
    USE SIGNAL ;
    PORT
      LAYER M4 ;
        RECT  69.036 37.968 69.12 37.992 ;
    END
  END b_cfg_data[16]
  PIN b_cfg_data[170]
    DIRECTION OUTPUT ;
    USE SIGNAL ;
    PORT
      LAYER M4 ;
        RECT  69.036 31.248 69.12 31.272 ;
    END
  END b_cfg_data[170]
  PIN b_cfg_data[171]
    DIRECTION OUTPUT ;
    USE SIGNAL ;
    PORT
      LAYER M4 ;
        RECT  69.036 31.344 69.12 31.368 ;
    END
  END b_cfg_data[171]
  PIN b_cfg_data[172]
    DIRECTION OUTPUT ;
    USE SIGNAL ;
    PORT
      LAYER M4 ;
        RECT  69.036 31.44 69.12 31.464 ;
    END
  END b_cfg_data[172]
  PIN b_cfg_data[173]
    DIRECTION OUTPUT ;
    USE SIGNAL ;
    PORT
      LAYER M4 ;
        RECT  69.036 31.536 69.12 31.56 ;
    END
  END b_cfg_data[173]
  PIN b_cfg_data[174]
    DIRECTION OUTPUT ;
    USE SIGNAL ;
    PORT
      LAYER M4 ;
        RECT  69.036 31.632 69.12 31.656 ;
    END
  END b_cfg_data[174]
  PIN b_cfg_data[175]
    DIRECTION OUTPUT ;
    USE SIGNAL ;
    PORT
      LAYER M4 ;
        RECT  69.036 31.728 69.12 31.752 ;
    END
  END b_cfg_data[175]
  PIN b_cfg_data[176]
    DIRECTION OUTPUT ;
    USE SIGNAL ;
    PORT
      LAYER M4 ;
        RECT  69.036 31.824 69.12 31.848 ;
    END
  END b_cfg_data[176]
  PIN b_cfg_data[177]
    DIRECTION OUTPUT ;
    USE SIGNAL ;
    PORT
      LAYER M4 ;
        RECT  69.036 31.92 69.12 31.944 ;
    END
  END b_cfg_data[177]
  PIN b_cfg_data[178]
    DIRECTION OUTPUT ;
    USE SIGNAL ;
    PORT
      LAYER M4 ;
        RECT  69.036 32.016 69.12 32.04 ;
    END
  END b_cfg_data[178]
  PIN b_cfg_data[179]
    DIRECTION OUTPUT ;
    USE SIGNAL ;
    PORT
      LAYER M4 ;
        RECT  69.036 32.112 69.12 32.136 ;
    END
  END b_cfg_data[179]
  PIN b_cfg_data[17]
    DIRECTION OUTPUT ;
    USE SIGNAL ;
    PORT
      LAYER M4 ;
        RECT  69.036 38.064 69.12 38.088 ;
    END
  END b_cfg_data[17]
  PIN b_cfg_data[180]
    DIRECTION OUTPUT ;
    USE SIGNAL ;
    PORT
      LAYER M4 ;
        RECT  69.036 22.992 69.12 23.016 ;
    END
  END b_cfg_data[180]
  PIN b_cfg_data[181]
    DIRECTION OUTPUT ;
    USE SIGNAL ;
    PORT
      LAYER M4 ;
        RECT  69.036 23.088 69.12 23.112 ;
    END
  END b_cfg_data[181]
  PIN b_cfg_data[182]
    DIRECTION OUTPUT ;
    USE SIGNAL ;
    PORT
      LAYER M4 ;
        RECT  69.036 23.184 69.12 23.208 ;
    END
  END b_cfg_data[182]
  PIN b_cfg_data[183]
    DIRECTION OUTPUT ;
    USE SIGNAL ;
    PORT
      LAYER M4 ;
        RECT  69.036 23.28 69.12 23.304 ;
    END
  END b_cfg_data[183]
  PIN b_cfg_data[184]
    DIRECTION OUTPUT ;
    USE SIGNAL ;
    PORT
      LAYER M4 ;
        RECT  69.036 23.376 69.12 23.4 ;
    END
  END b_cfg_data[184]
  PIN b_cfg_data[185]
    DIRECTION OUTPUT ;
    USE SIGNAL ;
    PORT
      LAYER M4 ;
        RECT  69.036 23.472 69.12 23.496 ;
    END
  END b_cfg_data[185]
  PIN b_cfg_data[186]
    DIRECTION OUTPUT ;
    USE SIGNAL ;
    PORT
      LAYER M4 ;
        RECT  69.036 23.568 69.12 23.592 ;
    END
  END b_cfg_data[186]
  PIN b_cfg_data[187]
    DIRECTION OUTPUT ;
    USE SIGNAL ;
    PORT
      LAYER M4 ;
        RECT  69.036 23.664 69.12 23.688 ;
    END
  END b_cfg_data[187]
  PIN b_cfg_data[188]
    DIRECTION OUTPUT ;
    USE SIGNAL ;
    PORT
      LAYER M4 ;
        RECT  69.036 23.76 69.12 23.784 ;
    END
  END b_cfg_data[188]
  PIN b_cfg_data[189]
    DIRECTION OUTPUT ;
    USE SIGNAL ;
    PORT
      LAYER M4 ;
        RECT  69.036 23.856 69.12 23.88 ;
    END
  END b_cfg_data[189]
  PIN b_cfg_data[18]
    DIRECTION OUTPUT ;
    USE SIGNAL ;
    PORT
      LAYER M4 ;
        RECT  69.036 38.16 69.12 38.184 ;
    END
  END b_cfg_data[18]
  PIN b_cfg_data[190]
    DIRECTION OUTPUT ;
    USE SIGNAL ;
    PORT
      LAYER M4 ;
        RECT  69.036 23.952 69.12 23.976 ;
    END
  END b_cfg_data[190]
  PIN b_cfg_data[191]
    DIRECTION OUTPUT ;
    USE SIGNAL ;
    PORT
      LAYER M4 ;
        RECT  69.036 24.048 69.12 24.072 ;
    END
  END b_cfg_data[191]
  PIN b_cfg_data[192]
    DIRECTION OUTPUT ;
    USE SIGNAL ;
    PORT
      LAYER M4 ;
        RECT  69.036 24.144 69.12 24.168 ;
    END
  END b_cfg_data[192]
  PIN b_cfg_data[193]
    DIRECTION OUTPUT ;
    USE SIGNAL ;
    PORT
      LAYER M4 ;
        RECT  69.036 24.24 69.12 24.264 ;
    END
  END b_cfg_data[193]
  PIN b_cfg_data[194]
    DIRECTION OUTPUT ;
    USE SIGNAL ;
    PORT
      LAYER M4 ;
        RECT  69.036 24.336 69.12 24.36 ;
    END
  END b_cfg_data[194]
  PIN b_cfg_data[195]
    DIRECTION OUTPUT ;
    USE SIGNAL ;
    PORT
      LAYER M4 ;
        RECT  69.036 24.432 69.12 24.456 ;
    END
  END b_cfg_data[195]
  PIN b_cfg_data[196]
    DIRECTION OUTPUT ;
    USE SIGNAL ;
    PORT
      LAYER M4 ;
        RECT  69.036 24.528 69.12 24.552 ;
    END
  END b_cfg_data[196]
  PIN b_cfg_data[197]
    DIRECTION OUTPUT ;
    USE SIGNAL ;
    PORT
      LAYER M4 ;
        RECT  69.036 24.624 69.12 24.648 ;
    END
  END b_cfg_data[197]
  PIN b_cfg_data[198]
    DIRECTION OUTPUT ;
    USE SIGNAL ;
    PORT
      LAYER M4 ;
        RECT  69.036 24.72 69.12 24.744 ;
    END
  END b_cfg_data[198]
  PIN b_cfg_data[199]
    DIRECTION OUTPUT ;
    USE SIGNAL ;
    PORT
      LAYER M4 ;
        RECT  69.036 24.816 69.12 24.84 ;
    END
  END b_cfg_data[199]
  PIN b_cfg_data[19]
    DIRECTION OUTPUT ;
    USE SIGNAL ;
    PORT
      LAYER M4 ;
        RECT  69.036 38.256 69.12 38.28 ;
    END
  END b_cfg_data[19]
  PIN b_cfg_data[1]
    DIRECTION OUTPUT ;
    USE SIGNAL ;
    PORT
      LAYER M4 ;
        RECT  69.036 36.528 69.12 36.552 ;
    END
  END b_cfg_data[1]
  PIN b_cfg_data[200]
    DIRECTION OUTPUT ;
    USE SIGNAL ;
    PORT
      LAYER M4 ;
        RECT  69.036 24.912 69.12 24.936 ;
    END
  END b_cfg_data[200]
  PIN b_cfg_data[201]
    DIRECTION OUTPUT ;
    USE SIGNAL ;
    PORT
      LAYER M4 ;
        RECT  69.036 25.008 69.12 25.032 ;
    END
  END b_cfg_data[201]
  PIN b_cfg_data[202]
    DIRECTION OUTPUT ;
    USE SIGNAL ;
    PORT
      LAYER M4 ;
        RECT  69.036 25.104 69.12 25.128 ;
    END
  END b_cfg_data[202]
  PIN b_cfg_data[203]
    DIRECTION OUTPUT ;
    USE SIGNAL ;
    PORT
      LAYER M4 ;
        RECT  69.036 25.2 69.12 25.224 ;
    END
  END b_cfg_data[203]
  PIN b_cfg_data[204]
    DIRECTION OUTPUT ;
    USE SIGNAL ;
    PORT
      LAYER M4 ;
        RECT  69.036 25.296 69.12 25.32 ;
    END
  END b_cfg_data[204]
  PIN b_cfg_data[205]
    DIRECTION OUTPUT ;
    USE SIGNAL ;
    PORT
      LAYER M4 ;
        RECT  69.036 25.392 69.12 25.416 ;
    END
  END b_cfg_data[205]
  PIN b_cfg_data[206]
    DIRECTION OUTPUT ;
    USE SIGNAL ;
    PORT
      LAYER M4 ;
        RECT  69.036 25.488 69.12 25.512 ;
    END
  END b_cfg_data[206]
  PIN b_cfg_data[207]
    DIRECTION OUTPUT ;
    USE SIGNAL ;
    PORT
      LAYER M4 ;
        RECT  69.036 25.584 69.12 25.608 ;
    END
  END b_cfg_data[207]
  PIN b_cfg_data[208]
    DIRECTION OUTPUT ;
    USE SIGNAL ;
    PORT
      LAYER M4 ;
        RECT  69.036 25.68 69.12 25.704 ;
    END
  END b_cfg_data[208]
  PIN b_cfg_data[209]
    DIRECTION OUTPUT ;
    USE SIGNAL ;
    PORT
      LAYER M4 ;
        RECT  69.036 25.776 69.12 25.8 ;
    END
  END b_cfg_data[209]
  PIN b_cfg_data[20]
    DIRECTION OUTPUT ;
    USE SIGNAL ;
    PORT
      LAYER M4 ;
        RECT  69.036 26.064 69.12 26.088 ;
    END
  END b_cfg_data[20]
  PIN b_cfg_data[210]
    DIRECTION OUTPUT ;
    USE SIGNAL ;
    PORT
      LAYER M4 ;
        RECT  69.036 25.872 69.12 25.896 ;
    END
  END b_cfg_data[210]
  PIN b_cfg_data[211]
    DIRECTION OUTPUT ;
    USE SIGNAL ;
    PORT
      LAYER M4 ;
        RECT  69.036 25.968 69.12 25.992 ;
    END
  END b_cfg_data[211]
  PIN b_cfg_data[212]
    DIRECTION OUTPUT ;
    USE SIGNAL ;
    PORT
      LAYER M4 ;
        RECT  69.036 19.92 69.12 19.944 ;
    END
  END b_cfg_data[212]
  PIN b_cfg_data[213]
    DIRECTION OUTPUT ;
    USE SIGNAL ;
    PORT
      LAYER M4 ;
        RECT  69.036 20.016 69.12 20.04 ;
    END
  END b_cfg_data[213]
  PIN b_cfg_data[214]
    DIRECTION OUTPUT ;
    USE SIGNAL ;
    PORT
      LAYER M4 ;
        RECT  69.036 20.112 69.12 20.136 ;
    END
  END b_cfg_data[214]
  PIN b_cfg_data[215]
    DIRECTION OUTPUT ;
    USE SIGNAL ;
    PORT
      LAYER M4 ;
        RECT  69.036 20.208 69.12 20.232 ;
    END
  END b_cfg_data[215]
  PIN b_cfg_data[216]
    DIRECTION OUTPUT ;
    USE SIGNAL ;
    PORT
      LAYER M4 ;
        RECT  69.036 20.304 69.12 20.328 ;
    END
  END b_cfg_data[216]
  PIN b_cfg_data[217]
    DIRECTION OUTPUT ;
    USE SIGNAL ;
    PORT
      LAYER M4 ;
        RECT  69.036 20.4 69.12 20.424 ;
    END
  END b_cfg_data[217]
  PIN b_cfg_data[218]
    DIRECTION OUTPUT ;
    USE SIGNAL ;
    PORT
      LAYER M4 ;
        RECT  69.036 20.496 69.12 20.52 ;
    END
  END b_cfg_data[218]
  PIN b_cfg_data[219]
    DIRECTION OUTPUT ;
    USE SIGNAL ;
    PORT
      LAYER M4 ;
        RECT  69.036 20.592 69.12 20.616 ;
    END
  END b_cfg_data[219]
  PIN b_cfg_data[21]
    DIRECTION OUTPUT ;
    USE SIGNAL ;
    PORT
      LAYER M4 ;
        RECT  69.036 26.16 69.12 26.184 ;
    END
  END b_cfg_data[21]
  PIN b_cfg_data[220]
    DIRECTION OUTPUT ;
    USE SIGNAL ;
    PORT
      LAYER M4 ;
        RECT  69.036 20.688 69.12 20.712 ;
    END
  END b_cfg_data[220]
  PIN b_cfg_data[221]
    DIRECTION OUTPUT ;
    USE SIGNAL ;
    PORT
      LAYER M4 ;
        RECT  69.036 20.784 69.12 20.808 ;
    END
  END b_cfg_data[221]
  PIN b_cfg_data[222]
    DIRECTION OUTPUT ;
    USE SIGNAL ;
    PORT
      LAYER M4 ;
        RECT  69.036 20.88 69.12 20.904 ;
    END
  END b_cfg_data[222]
  PIN b_cfg_data[223]
    DIRECTION OUTPUT ;
    USE SIGNAL ;
    PORT
      LAYER M4 ;
        RECT  69.036 20.976 69.12 21 ;
    END
  END b_cfg_data[223]
  PIN b_cfg_data[224]
    DIRECTION OUTPUT ;
    USE SIGNAL ;
    PORT
      LAYER M4 ;
        RECT  69.036 21.072 69.12 21.096 ;
    END
  END b_cfg_data[224]
  PIN b_cfg_data[225]
    DIRECTION OUTPUT ;
    USE SIGNAL ;
    PORT
      LAYER M4 ;
        RECT  69.036 21.168 69.12 21.192 ;
    END
  END b_cfg_data[225]
  PIN b_cfg_data[226]
    DIRECTION OUTPUT ;
    USE SIGNAL ;
    PORT
      LAYER M4 ;
        RECT  69.036 21.264 69.12 21.288 ;
    END
  END b_cfg_data[226]
  PIN b_cfg_data[227]
    DIRECTION OUTPUT ;
    USE SIGNAL ;
    PORT
      LAYER M4 ;
        RECT  69.036 21.36 69.12 21.384 ;
    END
  END b_cfg_data[227]
  PIN b_cfg_data[228]
    DIRECTION OUTPUT ;
    USE SIGNAL ;
    PORT
      LAYER M4 ;
        RECT  69.036 21.456 69.12 21.48 ;
    END
  END b_cfg_data[228]
  PIN b_cfg_data[229]
    DIRECTION OUTPUT ;
    USE SIGNAL ;
    PORT
      LAYER M4 ;
        RECT  69.036 21.552 69.12 21.576 ;
    END
  END b_cfg_data[229]
  PIN b_cfg_data[22]
    DIRECTION OUTPUT ;
    USE SIGNAL ;
    PORT
      LAYER M4 ;
        RECT  69.036 26.256 69.12 26.28 ;
    END
  END b_cfg_data[22]
  PIN b_cfg_data[230]
    DIRECTION OUTPUT ;
    USE SIGNAL ;
    PORT
      LAYER M4 ;
        RECT  69.036 21.648 69.12 21.672 ;
    END
  END b_cfg_data[230]
  PIN b_cfg_data[231]
    DIRECTION OUTPUT ;
    USE SIGNAL ;
    PORT
      LAYER M4 ;
        RECT  69.036 21.744 69.12 21.768 ;
    END
  END b_cfg_data[231]
  PIN b_cfg_data[232]
    DIRECTION OUTPUT ;
    USE SIGNAL ;
    PORT
      LAYER M4 ;
        RECT  69.036 21.84 69.12 21.864 ;
    END
  END b_cfg_data[232]
  PIN b_cfg_data[233]
    DIRECTION OUTPUT ;
    USE SIGNAL ;
    PORT
      LAYER M4 ;
        RECT  69.036 21.936 69.12 21.96 ;
    END
  END b_cfg_data[233]
  PIN b_cfg_data[234]
    DIRECTION OUTPUT ;
    USE SIGNAL ;
    PORT
      LAYER M4 ;
        RECT  69.036 22.032 69.12 22.056 ;
    END
  END b_cfg_data[234]
  PIN b_cfg_data[235]
    DIRECTION OUTPUT ;
    USE SIGNAL ;
    PORT
      LAYER M4 ;
        RECT  69.036 22.128 69.12 22.152 ;
    END
  END b_cfg_data[235]
  PIN b_cfg_data[236]
    DIRECTION OUTPUT ;
    USE SIGNAL ;
    PORT
      LAYER M4 ;
        RECT  69.036 22.224 69.12 22.248 ;
    END
  END b_cfg_data[236]
  PIN b_cfg_data[237]
    DIRECTION OUTPUT ;
    USE SIGNAL ;
    PORT
      LAYER M4 ;
        RECT  69.036 22.32 69.12 22.344 ;
    END
  END b_cfg_data[237]
  PIN b_cfg_data[238]
    DIRECTION OUTPUT ;
    USE SIGNAL ;
    PORT
      LAYER M4 ;
        RECT  69.036 22.416 69.12 22.44 ;
    END
  END b_cfg_data[238]
  PIN b_cfg_data[239]
    DIRECTION OUTPUT ;
    USE SIGNAL ;
    PORT
      LAYER M4 ;
        RECT  69.036 22.512 69.12 22.536 ;
    END
  END b_cfg_data[239]
  PIN b_cfg_data[23]
    DIRECTION OUTPUT ;
    USE SIGNAL ;
    PORT
      LAYER M4 ;
        RECT  69.036 26.352 69.12 26.376 ;
    END
  END b_cfg_data[23]
  PIN b_cfg_data[240]
    DIRECTION OUTPUT ;
    USE SIGNAL ;
    PORT
      LAYER M4 ;
        RECT  69.036 22.608 69.12 22.632 ;
    END
  END b_cfg_data[240]
  PIN b_cfg_data[241]
    DIRECTION OUTPUT ;
    USE SIGNAL ;
    PORT
      LAYER M4 ;
        RECT  69.036 22.704 69.12 22.728 ;
    END
  END b_cfg_data[241]
  PIN b_cfg_data[242]
    DIRECTION OUTPUT ;
    USE SIGNAL ;
    PORT
      LAYER M4 ;
        RECT  69.036 22.8 69.12 22.824 ;
    END
  END b_cfg_data[242]
  PIN b_cfg_data[243]
    DIRECTION OUTPUT ;
    USE SIGNAL ;
    PORT
      LAYER M4 ;
        RECT  69.036 22.896 69.12 22.92 ;
    END
  END b_cfg_data[243]
  PIN b_cfg_data[244]
    DIRECTION OUTPUT ;
    USE SIGNAL ;
    PORT
      LAYER M4 ;
        RECT  69.036 42.192 69.12 42.216 ;
    END
  END b_cfg_data[244]
  PIN b_cfg_data[245]
    DIRECTION OUTPUT ;
    USE SIGNAL ;
    PORT
      LAYER M4 ;
        RECT  69.036 42.288 69.12 42.312 ;
    END
  END b_cfg_data[245]
  PIN b_cfg_data[246]
    DIRECTION OUTPUT ;
    USE SIGNAL ;
    PORT
      LAYER M4 ;
        RECT  69.036 42.384 69.12 42.408 ;
    END
  END b_cfg_data[246]
  PIN b_cfg_data[247]
    DIRECTION OUTPUT ;
    USE SIGNAL ;
    PORT
      LAYER M4 ;
        RECT  69.036 42.48 69.12 42.504 ;
    END
  END b_cfg_data[247]
  PIN b_cfg_data[248]
    DIRECTION OUTPUT ;
    USE SIGNAL ;
    PORT
      LAYER M4 ;
        RECT  69.036 42.576 69.12 42.6 ;
    END
  END b_cfg_data[248]
  PIN b_cfg_data[249]
    DIRECTION OUTPUT ;
    USE SIGNAL ;
    PORT
      LAYER M4 ;
        RECT  69.036 42.672 69.12 42.696 ;
    END
  END b_cfg_data[249]
  PIN b_cfg_data[24]
    DIRECTION OUTPUT ;
    USE SIGNAL ;
    PORT
      LAYER M4 ;
        RECT  69.036 26.448 69.12 26.472 ;
    END
  END b_cfg_data[24]
  PIN b_cfg_data[250]
    DIRECTION OUTPUT ;
    USE SIGNAL ;
    PORT
      LAYER M4 ;
        RECT  69.036 42.768 69.12 42.792 ;
    END
  END b_cfg_data[250]
  PIN b_cfg_data[251]
    DIRECTION OUTPUT ;
    USE SIGNAL ;
    PORT
      LAYER M4 ;
        RECT  69.036 42.864 69.12 42.888 ;
    END
  END b_cfg_data[251]
  PIN b_cfg_data[252]
    DIRECTION OUTPUT ;
    USE SIGNAL ;
    PORT
      LAYER M4 ;
        RECT  69.036 42.96 69.12 42.984 ;
    END
  END b_cfg_data[252]
  PIN b_cfg_data[253]
    DIRECTION OUTPUT ;
    USE SIGNAL ;
    PORT
      LAYER M4 ;
        RECT  69.036 43.056 69.12 43.08 ;
    END
  END b_cfg_data[253]
  PIN b_cfg_data[254]
    DIRECTION OUTPUT ;
    USE SIGNAL ;
    PORT
      LAYER M4 ;
        RECT  69.036 43.152 69.12 43.176 ;
    END
  END b_cfg_data[254]
  PIN b_cfg_data[255]
    DIRECTION OUTPUT ;
    USE SIGNAL ;
    PORT
      LAYER M4 ;
        RECT  69.036 43.248 69.12 43.272 ;
    END
  END b_cfg_data[255]
  PIN b_cfg_data[25]
    DIRECTION OUTPUT ;
    USE SIGNAL ;
    PORT
      LAYER M4 ;
        RECT  69.036 26.544 69.12 26.568 ;
    END
  END b_cfg_data[25]
  PIN b_cfg_data[26]
    DIRECTION OUTPUT ;
    USE SIGNAL ;
    PORT
      LAYER M4 ;
        RECT  69.036 26.64 69.12 26.664 ;
    END
  END b_cfg_data[26]
  PIN b_cfg_data[27]
    DIRECTION OUTPUT ;
    USE SIGNAL ;
    PORT
      LAYER M4 ;
        RECT  69.036 26.736 69.12 26.76 ;
    END
  END b_cfg_data[27]
  PIN b_cfg_data[28]
    DIRECTION OUTPUT ;
    USE SIGNAL ;
    PORT
      LAYER M4 ;
        RECT  69.036 26.832 69.12 26.856 ;
    END
  END b_cfg_data[28]
  PIN b_cfg_data[29]
    DIRECTION OUTPUT ;
    USE SIGNAL ;
    PORT
      LAYER M4 ;
        RECT  69.036 26.928 69.12 26.952 ;
    END
  END b_cfg_data[29]
  PIN b_cfg_data[2]
    DIRECTION OUTPUT ;
    USE SIGNAL ;
    PORT
      LAYER M4 ;
        RECT  69.036 36.624 69.12 36.648 ;
    END
  END b_cfg_data[2]
  PIN b_cfg_data[30]
    DIRECTION OUTPUT ;
    USE SIGNAL ;
    PORT
      LAYER M4 ;
        RECT  69.036 27.024 69.12 27.048 ;
    END
  END b_cfg_data[30]
  PIN b_cfg_data[31]
    DIRECTION OUTPUT ;
    USE SIGNAL ;
    PORT
      LAYER M4 ;
        RECT  69.036 27.12 69.12 27.144 ;
    END
  END b_cfg_data[31]
  PIN b_cfg_data[32]
    DIRECTION OUTPUT ;
    USE SIGNAL ;
    PORT
      LAYER M4 ;
        RECT  69.036 27.216 69.12 27.24 ;
    END
  END b_cfg_data[32]
  PIN b_cfg_data[33]
    DIRECTION OUTPUT ;
    USE SIGNAL ;
    PORT
      LAYER M4 ;
        RECT  69.036 27.312 69.12 27.336 ;
    END
  END b_cfg_data[33]
  PIN b_cfg_data[34]
    DIRECTION OUTPUT ;
    USE SIGNAL ;
    PORT
      LAYER M4 ;
        RECT  69.036 27.408 69.12 27.432 ;
    END
  END b_cfg_data[34]
  PIN b_cfg_data[35]
    DIRECTION OUTPUT ;
    USE SIGNAL ;
    PORT
      LAYER M4 ;
        RECT  69.036 27.504 69.12 27.528 ;
    END
  END b_cfg_data[35]
  PIN b_cfg_data[36]
    DIRECTION OUTPUT ;
    USE SIGNAL ;
    PORT
      LAYER M4 ;
        RECT  69.036 27.6 69.12 27.624 ;
    END
  END b_cfg_data[36]
  PIN b_cfg_data[37]
    DIRECTION OUTPUT ;
    USE SIGNAL ;
    PORT
      LAYER M4 ;
        RECT  69.036 27.696 69.12 27.72 ;
    END
  END b_cfg_data[37]
  PIN b_cfg_data[38]
    DIRECTION OUTPUT ;
    USE SIGNAL ;
    PORT
      LAYER M4 ;
        RECT  69.036 27.792 69.12 27.816 ;
    END
  END b_cfg_data[38]
  PIN b_cfg_data[39]
    DIRECTION OUTPUT ;
    USE SIGNAL ;
    PORT
      LAYER M4 ;
        RECT  69.036 27.888 69.12 27.912 ;
    END
  END b_cfg_data[39]
  PIN b_cfg_data[3]
    DIRECTION OUTPUT ;
    USE SIGNAL ;
    PORT
      LAYER M4 ;
        RECT  69.036 36.72 69.12 36.744 ;
    END
  END b_cfg_data[3]
  PIN b_cfg_data[40]
    DIRECTION OUTPUT ;
    USE SIGNAL ;
    PORT
      LAYER M4 ;
        RECT  69.036 27.984 69.12 28.008 ;
    END
  END b_cfg_data[40]
  PIN b_cfg_data[41]
    DIRECTION OUTPUT ;
    USE SIGNAL ;
    PORT
      LAYER M4 ;
        RECT  69.036 28.08 69.12 28.104 ;
    END
  END b_cfg_data[41]
  PIN b_cfg_data[42]
    DIRECTION OUTPUT ;
    USE SIGNAL ;
    PORT
      LAYER M4 ;
        RECT  69.036 28.176 69.12 28.2 ;
    END
  END b_cfg_data[42]
  PIN b_cfg_data[43]
    DIRECTION OUTPUT ;
    USE SIGNAL ;
    PORT
      LAYER M4 ;
        RECT  69.036 28.272 69.12 28.296 ;
    END
  END b_cfg_data[43]
  PIN b_cfg_data[44]
    DIRECTION OUTPUT ;
    USE SIGNAL ;
    PORT
      LAYER M4 ;
        RECT  69.036 28.368 69.12 28.392 ;
    END
  END b_cfg_data[44]
  PIN b_cfg_data[45]
    DIRECTION OUTPUT ;
    USE SIGNAL ;
    PORT
      LAYER M4 ;
        RECT  69.036 28.464 69.12 28.488 ;
    END
  END b_cfg_data[45]
  PIN b_cfg_data[46]
    DIRECTION OUTPUT ;
    USE SIGNAL ;
    PORT
      LAYER M4 ;
        RECT  69.036 28.56 69.12 28.584 ;
    END
  END b_cfg_data[46]
  PIN b_cfg_data[47]
    DIRECTION OUTPUT ;
    USE SIGNAL ;
    PORT
      LAYER M4 ;
        RECT  69.036 28.656 69.12 28.68 ;
    END
  END b_cfg_data[47]
  PIN b_cfg_data[48]
    DIRECTION OUTPUT ;
    USE SIGNAL ;
    PORT
      LAYER M4 ;
        RECT  69.036 28.752 69.12 28.776 ;
    END
  END b_cfg_data[48]
  PIN b_cfg_data[49]
    DIRECTION OUTPUT ;
    USE SIGNAL ;
    PORT
      LAYER M4 ;
        RECT  69.036 28.848 69.12 28.872 ;
    END
  END b_cfg_data[49]
  PIN b_cfg_data[4]
    DIRECTION OUTPUT ;
    USE SIGNAL ;
    PORT
      LAYER M4 ;
        RECT  69.036 36.816 69.12 36.84 ;
    END
  END b_cfg_data[4]
  PIN b_cfg_data[50]
    DIRECTION OUTPUT ;
    USE SIGNAL ;
    PORT
      LAYER M4 ;
        RECT  69.036 28.944 69.12 28.968 ;
    END
  END b_cfg_data[50]
  PIN b_cfg_data[51]
    DIRECTION OUTPUT ;
    USE SIGNAL ;
    PORT
      LAYER M4 ;
        RECT  69.036 29.04 69.12 29.064 ;
    END
  END b_cfg_data[51]
  PIN b_cfg_data[52]
    DIRECTION OUTPUT ;
    USE SIGNAL ;
    PORT
      LAYER M4 ;
        RECT  69.036 32.208 69.12 32.232 ;
    END
  END b_cfg_data[52]
  PIN b_cfg_data[53]
    DIRECTION OUTPUT ;
    USE SIGNAL ;
    PORT
      LAYER M4 ;
        RECT  69.036 32.304 69.12 32.328 ;
    END
  END b_cfg_data[53]
  PIN b_cfg_data[54]
    DIRECTION OUTPUT ;
    USE SIGNAL ;
    PORT
      LAYER M4 ;
        RECT  69.036 32.4 69.12 32.424 ;
    END
  END b_cfg_data[54]
  PIN b_cfg_data[55]
    DIRECTION OUTPUT ;
    USE SIGNAL ;
    PORT
      LAYER M4 ;
        RECT  69.036 32.496 69.12 32.52 ;
    END
  END b_cfg_data[55]
  PIN b_cfg_data[56]
    DIRECTION OUTPUT ;
    USE SIGNAL ;
    PORT
      LAYER M4 ;
        RECT  69.036 32.592 69.12 32.616 ;
    END
  END b_cfg_data[56]
  PIN b_cfg_data[57]
    DIRECTION OUTPUT ;
    USE SIGNAL ;
    PORT
      LAYER M4 ;
        RECT  69.036 32.688 69.12 32.712 ;
    END
  END b_cfg_data[57]
  PIN b_cfg_data[58]
    DIRECTION OUTPUT ;
    USE SIGNAL ;
    PORT
      LAYER M4 ;
        RECT  69.036 32.784 69.12 32.808 ;
    END
  END b_cfg_data[58]
  PIN b_cfg_data[59]
    DIRECTION OUTPUT ;
    USE SIGNAL ;
    PORT
      LAYER M4 ;
        RECT  69.036 32.88 69.12 32.904 ;
    END
  END b_cfg_data[59]
  PIN b_cfg_data[5]
    DIRECTION OUTPUT ;
    USE SIGNAL ;
    PORT
      LAYER M4 ;
        RECT  69.036 36.912 69.12 36.936 ;
    END
  END b_cfg_data[5]
  PIN b_cfg_data[60]
    DIRECTION OUTPUT ;
    USE SIGNAL ;
    PORT
      LAYER M4 ;
        RECT  69.036 32.976 69.12 33 ;
    END
  END b_cfg_data[60]
  PIN b_cfg_data[61]
    DIRECTION OUTPUT ;
    USE SIGNAL ;
    PORT
      LAYER M4 ;
        RECT  69.036 33.072 69.12 33.096 ;
    END
  END b_cfg_data[61]
  PIN b_cfg_data[62]
    DIRECTION OUTPUT ;
    USE SIGNAL ;
    PORT
      LAYER M4 ;
        RECT  69.036 33.168 69.12 33.192 ;
    END
  END b_cfg_data[62]
  PIN b_cfg_data[63]
    DIRECTION OUTPUT ;
    USE SIGNAL ;
    PORT
      LAYER M4 ;
        RECT  69.036 33.264 69.12 33.288 ;
    END
  END b_cfg_data[63]
  PIN b_cfg_data[64]
    DIRECTION OUTPUT ;
    USE SIGNAL ;
    PORT
      LAYER M4 ;
        RECT  69.036 33.36 69.12 33.384 ;
    END
  END b_cfg_data[64]
  PIN b_cfg_data[65]
    DIRECTION OUTPUT ;
    USE SIGNAL ;
    PORT
      LAYER M4 ;
        RECT  69.036 33.456 69.12 33.48 ;
    END
  END b_cfg_data[65]
  PIN b_cfg_data[66]
    DIRECTION OUTPUT ;
    USE SIGNAL ;
    PORT
      LAYER M4 ;
        RECT  69.036 33.552 69.12 33.576 ;
    END
  END b_cfg_data[66]
  PIN b_cfg_data[67]
    DIRECTION OUTPUT ;
    USE SIGNAL ;
    PORT
      LAYER M4 ;
        RECT  69.036 33.648 69.12 33.672 ;
    END
  END b_cfg_data[67]
  PIN b_cfg_data[68]
    DIRECTION OUTPUT ;
    USE SIGNAL ;
    PORT
      LAYER M4 ;
        RECT  69.036 33.744 69.12 33.768 ;
    END
  END b_cfg_data[68]
  PIN b_cfg_data[69]
    DIRECTION OUTPUT ;
    USE SIGNAL ;
    PORT
      LAYER M4 ;
        RECT  69.036 33.84 69.12 33.864 ;
    END
  END b_cfg_data[69]
  PIN b_cfg_data[6]
    DIRECTION OUTPUT ;
    USE SIGNAL ;
    PORT
      LAYER M4 ;
        RECT  69.036 37.008 69.12 37.032 ;
    END
  END b_cfg_data[6]
  PIN b_cfg_data[70]
    DIRECTION OUTPUT ;
    USE SIGNAL ;
    PORT
      LAYER M4 ;
        RECT  69.036 33.936 69.12 33.96 ;
    END
  END b_cfg_data[70]
  PIN b_cfg_data[71]
    DIRECTION OUTPUT ;
    USE SIGNAL ;
    PORT
      LAYER M4 ;
        RECT  69.036 34.032 69.12 34.056 ;
    END
  END b_cfg_data[71]
  PIN b_cfg_data[72]
    DIRECTION OUTPUT ;
    USE SIGNAL ;
    PORT
      LAYER M4 ;
        RECT  69.036 34.128 69.12 34.152 ;
    END
  END b_cfg_data[72]
  PIN b_cfg_data[73]
    DIRECTION OUTPUT ;
    USE SIGNAL ;
    PORT
      LAYER M4 ;
        RECT  69.036 34.224 69.12 34.248 ;
    END
  END b_cfg_data[73]
  PIN b_cfg_data[74]
    DIRECTION OUTPUT ;
    USE SIGNAL ;
    PORT
      LAYER M4 ;
        RECT  69.036 34.32 69.12 34.344 ;
    END
  END b_cfg_data[74]
  PIN b_cfg_data[75]
    DIRECTION OUTPUT ;
    USE SIGNAL ;
    PORT
      LAYER M4 ;
        RECT  69.036 34.416 69.12 34.44 ;
    END
  END b_cfg_data[75]
  PIN b_cfg_data[76]
    DIRECTION OUTPUT ;
    USE SIGNAL ;
    PORT
      LAYER M4 ;
        RECT  69.036 34.512 69.12 34.536 ;
    END
  END b_cfg_data[76]
  PIN b_cfg_data[77]
    DIRECTION OUTPUT ;
    USE SIGNAL ;
    PORT
      LAYER M4 ;
        RECT  69.036 34.608 69.12 34.632 ;
    END
  END b_cfg_data[77]
  PIN b_cfg_data[78]
    DIRECTION OUTPUT ;
    USE SIGNAL ;
    PORT
      LAYER M4 ;
        RECT  69.036 34.704 69.12 34.728 ;
    END
  END b_cfg_data[78]
  PIN b_cfg_data[79]
    DIRECTION OUTPUT ;
    USE SIGNAL ;
    PORT
      LAYER M4 ;
        RECT  69.036 34.8 69.12 34.824 ;
    END
  END b_cfg_data[79]
  PIN b_cfg_data[7]
    DIRECTION OUTPUT ;
    USE SIGNAL ;
    PORT
      LAYER M4 ;
        RECT  69.036 37.104 69.12 37.128 ;
    END
  END b_cfg_data[7]
  PIN b_cfg_data[80]
    DIRECTION OUTPUT ;
    USE SIGNAL ;
    PORT
      LAYER M4 ;
        RECT  69.036 34.896 69.12 34.92 ;
    END
  END b_cfg_data[80]
  PIN b_cfg_data[81]
    DIRECTION OUTPUT ;
    USE SIGNAL ;
    PORT
      LAYER M4 ;
        RECT  69.036 34.992 69.12 35.016 ;
    END
  END b_cfg_data[81]
  PIN b_cfg_data[82]
    DIRECTION OUTPUT ;
    USE SIGNAL ;
    PORT
      LAYER M4 ;
        RECT  69.036 35.088 69.12 35.112 ;
    END
  END b_cfg_data[82]
  PIN b_cfg_data[83]
    DIRECTION OUTPUT ;
    USE SIGNAL ;
    PORT
      LAYER M4 ;
        RECT  69.036 35.184 69.12 35.208 ;
    END
  END b_cfg_data[83]
  PIN b_cfg_data[84]
    DIRECTION OUTPUT ;
    USE SIGNAL ;
    PORT
      LAYER M4 ;
        RECT  69.036 48.336 69.12 48.36 ;
    END
  END b_cfg_data[84]
  PIN b_cfg_data[85]
    DIRECTION OUTPUT ;
    USE SIGNAL ;
    PORT
      LAYER M4 ;
        RECT  69.036 48.432 69.12 48.456 ;
    END
  END b_cfg_data[85]
  PIN b_cfg_data[86]
    DIRECTION OUTPUT ;
    USE SIGNAL ;
    PORT
      LAYER M4 ;
        RECT  69.036 48.528 69.12 48.552 ;
    END
  END b_cfg_data[86]
  PIN b_cfg_data[87]
    DIRECTION OUTPUT ;
    USE SIGNAL ;
    PORT
      LAYER M4 ;
        RECT  69.036 48.624 69.12 48.648 ;
    END
  END b_cfg_data[87]
  PIN b_cfg_data[88]
    DIRECTION OUTPUT ;
    USE SIGNAL ;
    PORT
      LAYER M4 ;
        RECT  69.036 48.72 69.12 48.744 ;
    END
  END b_cfg_data[88]
  PIN b_cfg_data[89]
    DIRECTION OUTPUT ;
    USE SIGNAL ;
    PORT
      LAYER M4 ;
        RECT  69.036 48.816 69.12 48.84 ;
    END
  END b_cfg_data[89]
  PIN b_cfg_data[8]
    DIRECTION OUTPUT ;
    USE SIGNAL ;
    PORT
      LAYER M4 ;
        RECT  69.036 37.2 69.12 37.224 ;
    END
  END b_cfg_data[8]
  PIN b_cfg_data[90]
    DIRECTION OUTPUT ;
    USE SIGNAL ;
    PORT
      LAYER M4 ;
        RECT  69.036 48.912 69.12 48.936 ;
    END
  END b_cfg_data[90]
  PIN b_cfg_data[91]
    DIRECTION OUTPUT ;
    USE SIGNAL ;
    PORT
      LAYER M4 ;
        RECT  69.036 49.008 69.12 49.032 ;
    END
  END b_cfg_data[91]
  PIN b_cfg_data[92]
    DIRECTION OUTPUT ;
    USE SIGNAL ;
    PORT
      LAYER M4 ;
        RECT  69.036 49.104 69.12 49.128 ;
    END
  END b_cfg_data[92]
  PIN b_cfg_data[93]
    DIRECTION OUTPUT ;
    USE SIGNAL ;
    PORT
      LAYER M4 ;
        RECT  69.036 49.2 69.12 49.224 ;
    END
  END b_cfg_data[93]
  PIN b_cfg_data[94]
    DIRECTION OUTPUT ;
    USE SIGNAL ;
    PORT
      LAYER M4 ;
        RECT  69.036 49.296 69.12 49.32 ;
    END
  END b_cfg_data[94]
  PIN b_cfg_data[95]
    DIRECTION OUTPUT ;
    USE SIGNAL ;
    PORT
      LAYER M4 ;
        RECT  69.036 49.392 69.12 49.416 ;
    END
  END b_cfg_data[95]
  PIN b_cfg_data[96]
    DIRECTION OUTPUT ;
    USE SIGNAL ;
    PORT
      LAYER M4 ;
        RECT  69.036 49.488 69.12 49.512 ;
    END
  END b_cfg_data[96]
  PIN b_cfg_data[97]
    DIRECTION OUTPUT ;
    USE SIGNAL ;
    PORT
      LAYER M4 ;
        RECT  69.036 49.584 69.12 49.608 ;
    END
  END b_cfg_data[97]
  PIN b_cfg_data[98]
    DIRECTION OUTPUT ;
    USE SIGNAL ;
    PORT
      LAYER M4 ;
        RECT  69.036 49.68 69.12 49.704 ;
    END
  END b_cfg_data[98]
  PIN b_cfg_data[99]
    DIRECTION OUTPUT ;
    USE SIGNAL ;
    PORT
      LAYER M4 ;
        RECT  69.036 49.776 69.12 49.8 ;
    END
  END b_cfg_data[99]
  PIN b_cfg_data[9]
    DIRECTION OUTPUT ;
    USE SIGNAL ;
    PORT
      LAYER M4 ;
        RECT  69.036 37.296 69.12 37.32 ;
    END
  END b_cfg_data[9]
  PIN b_cfg_target[0]
    DIRECTION OUTPUT ;
    USE SIGNAL ;
    PORT
      LAYER M4 ;
        RECT  69.036 43.344 69.12 43.368 ;
    END
  END b_cfg_target[0]
  PIN b_cfg_target[1]
    DIRECTION OUTPUT ;
    USE SIGNAL ;
    PORT
      LAYER M4 ;
        RECT  69.036 43.44 69.12 43.464 ;
    END
  END b_cfg_target[1]
  PIN b_cfg_target[2]
    DIRECTION OUTPUT ;
    USE SIGNAL ;
    PORT
      LAYER M4 ;
        RECT  69.036 43.536 69.12 43.56 ;
    END
  END b_cfg_target[2]
  PIN b_cfg_target[3]
    DIRECTION OUTPUT ;
    USE SIGNAL ;
    PORT
      LAYER M4 ;
        RECT  69.036 43.632 69.12 43.656 ;
    END
  END b_cfg_target[3]
  PIN b_cfg_target[4]
    DIRECTION OUTPUT ;
    USE SIGNAL ;
    PORT
      LAYER M4 ;
        RECT  69.036 43.728 69.12 43.752 ;
    END
  END b_cfg_target[4]
  PIN b_cfg_target[5]
    DIRECTION OUTPUT ;
    USE SIGNAL ;
    PORT
      LAYER M4 ;
        RECT  69.036 43.824 69.12 43.848 ;
    END
  END b_cfg_target[5]
  PIN b_cfg_target[6]
    DIRECTION OUTPUT ;
    USE SIGNAL ;
    PORT
      LAYER M4 ;
        RECT  69.036 43.92 69.12 43.944 ;
    END
  END b_cfg_target[6]
  PIN b_cfg_target[7]
    DIRECTION OUTPUT ;
    USE SIGNAL ;
    PORT
      LAYER M4 ;
        RECT  69.036 44.016 69.12 44.04 ;
    END
  END b_cfg_target[7]
  PIN b_cfg_v
    DIRECTION OUTPUT ;
    USE SIGNAL ;
    PORT
      LAYER M4 ;
        RECT  69.036 44.112 69.12 44.136 ;
    END
  END b_cfg_v
  PIN b_desc_base[0]
    DIRECTION OUTPUT ;
    USE SIGNAL ;
    PORT
      LAYER M4 ;
        RECT  69.036 44.208 69.12 44.232 ;
    END
  END b_desc_base[0]
  PIN b_desc_base[10]
    DIRECTION OUTPUT ;
    USE SIGNAL ;
    PORT
      LAYER M4 ;
        RECT  69.036 45.168 69.12 45.192 ;
    END
  END b_desc_base[10]
  PIN b_desc_base[11]
    DIRECTION OUTPUT ;
    USE SIGNAL ;
    PORT
      LAYER M4 ;
        RECT  69.036 39.12 69.12 39.144 ;
    END
  END b_desc_base[11]
  PIN b_desc_base[1]
    DIRECTION OUTPUT ;
    USE SIGNAL ;
    PORT
      LAYER M4 ;
        RECT  69.036 44.304 69.12 44.328 ;
    END
  END b_desc_base[1]
  PIN b_desc_base[2]
    DIRECTION OUTPUT ;
    USE SIGNAL ;
    PORT
      LAYER M4 ;
        RECT  69.036 44.4 69.12 44.424 ;
    END
  END b_desc_base[2]
  PIN b_desc_base[3]
    DIRECTION OUTPUT ;
    USE SIGNAL ;
    PORT
      LAYER M4 ;
        RECT  69.036 44.496 69.12 44.52 ;
    END
  END b_desc_base[3]
  PIN b_desc_base[4]
    DIRECTION OUTPUT ;
    USE SIGNAL ;
    PORT
      LAYER M4 ;
        RECT  69.036 44.592 69.12 44.616 ;
    END
  END b_desc_base[4]
  PIN b_desc_base[5]
    DIRECTION OUTPUT ;
    USE SIGNAL ;
    PORT
      LAYER M4 ;
        RECT  69.036 44.688 69.12 44.712 ;
    END
  END b_desc_base[5]
  PIN b_desc_base[6]
    DIRECTION OUTPUT ;
    USE SIGNAL ;
    PORT
      LAYER M4 ;
        RECT  69.036 44.784 69.12 44.808 ;
    END
  END b_desc_base[6]
  PIN b_desc_base[7]
    DIRECTION OUTPUT ;
    USE SIGNAL ;
    PORT
      LAYER M4 ;
        RECT  69.036 44.88 69.12 44.904 ;
    END
  END b_desc_base[7]
  PIN b_desc_base[8]
    DIRECTION OUTPUT ;
    USE SIGNAL ;
    PORT
      LAYER M4 ;
        RECT  69.036 44.976 69.12 45 ;
    END
  END b_desc_base[8]
  PIN b_desc_base[9]
    DIRECTION OUTPUT ;
    USE SIGNAL ;
    PORT
      LAYER M4 ;
        RECT  69.036 45.072 69.12 45.096 ;
    END
  END b_desc_base[9]
  PIN b_desc_limit[0]
    DIRECTION OUTPUT ;
    USE SIGNAL ;
    PORT
      LAYER M4 ;
        RECT  69.036 39.216 69.12 39.24 ;
    END
  END b_desc_limit[0]
  PIN b_desc_limit[10]
    DIRECTION OUTPUT ;
    USE SIGNAL ;
    PORT
      LAYER M4 ;
        RECT  69.036 40.176 69.12 40.2 ;
    END
  END b_desc_limit[10]
  PIN b_desc_limit[11]
    DIRECTION OUTPUT ;
    USE SIGNAL ;
    PORT
      LAYER M4 ;
        RECT  69.036 40.272 69.12 40.296 ;
    END
  END b_desc_limit[11]
  PIN b_desc_limit[12]
    DIRECTION OUTPUT ;
    USE SIGNAL ;
    PORT
      LAYER M4 ;
        RECT  69.036 40.368 69.12 40.392 ;
    END
  END b_desc_limit[12]
  PIN b_desc_limit[1]
    DIRECTION OUTPUT ;
    USE SIGNAL ;
    PORT
      LAYER M4 ;
        RECT  69.036 39.312 69.12 39.336 ;
    END
  END b_desc_limit[1]
  PIN b_desc_limit[2]
    DIRECTION OUTPUT ;
    USE SIGNAL ;
    PORT
      LAYER M4 ;
        RECT  69.036 39.408 69.12 39.432 ;
    END
  END b_desc_limit[2]
  PIN b_desc_limit[3]
    DIRECTION OUTPUT ;
    USE SIGNAL ;
    PORT
      LAYER M4 ;
        RECT  69.036 39.504 69.12 39.528 ;
    END
  END b_desc_limit[3]
  PIN b_desc_limit[4]
    DIRECTION OUTPUT ;
    USE SIGNAL ;
    PORT
      LAYER M4 ;
        RECT  69.036 39.6 69.12 39.624 ;
    END
  END b_desc_limit[4]
  PIN b_desc_limit[5]
    DIRECTION OUTPUT ;
    USE SIGNAL ;
    PORT
      LAYER M4 ;
        RECT  69.036 39.696 69.12 39.72 ;
    END
  END b_desc_limit[5]
  PIN b_desc_limit[6]
    DIRECTION OUTPUT ;
    USE SIGNAL ;
    PORT
      LAYER M4 ;
        RECT  69.036 39.792 69.12 39.816 ;
    END
  END b_desc_limit[6]
  PIN b_desc_limit[7]
    DIRECTION OUTPUT ;
    USE SIGNAL ;
    PORT
      LAYER M4 ;
        RECT  69.036 39.888 69.12 39.912 ;
    END
  END b_desc_limit[7]
  PIN b_desc_limit[8]
    DIRECTION OUTPUT ;
    USE SIGNAL ;
    PORT
      LAYER M4 ;
        RECT  69.036 39.984 69.12 40.008 ;
    END
  END b_desc_limit[8]
  PIN b_desc_limit[9]
    DIRECTION OUTPUT ;
    USE SIGNAL ;
    PORT
      LAYER M4 ;
        RECT  69.036 40.08 69.12 40.104 ;
    END
  END b_desc_limit[9]
  PIN b_desc_loops[0]
    DIRECTION OUTPUT ;
    USE SIGNAL ;
    PORT
      LAYER M4 ;
        RECT  69.036 40.464 69.12 40.488 ;
    END
  END b_desc_loops[0]
  PIN b_desc_loops[10]
    DIRECTION OUTPUT ;
    USE SIGNAL ;
    PORT
      LAYER M4 ;
        RECT  69.036 41.424 69.12 41.448 ;
    END
  END b_desc_loops[10]
  PIN b_desc_loops[11]
    DIRECTION OUTPUT ;
    USE SIGNAL ;
    PORT
      LAYER M4 ;
        RECT  69.036 41.52 69.12 41.544 ;
    END
  END b_desc_loops[11]
  PIN b_desc_loops[12]
    DIRECTION OUTPUT ;
    USE SIGNAL ;
    PORT
      LAYER M4 ;
        RECT  69.036 41.616 69.12 41.64 ;
    END
  END b_desc_loops[12]
  PIN b_desc_loops[13]
    DIRECTION OUTPUT ;
    USE SIGNAL ;
    PORT
      LAYER M4 ;
        RECT  69.036 41.712 69.12 41.736 ;
    END
  END b_desc_loops[13]
  PIN b_desc_loops[14]
    DIRECTION OUTPUT ;
    USE SIGNAL ;
    PORT
      LAYER M4 ;
        RECT  69.036 41.808 69.12 41.832 ;
    END
  END b_desc_loops[14]
  PIN b_desc_loops[15]
    DIRECTION OUTPUT ;
    USE SIGNAL ;
    PORT
      LAYER M4 ;
        RECT  69.036 41.904 69.12 41.928 ;
    END
  END b_desc_loops[15]
  PIN b_desc_loops[1]
    DIRECTION OUTPUT ;
    USE SIGNAL ;
    PORT
      LAYER M4 ;
        RECT  69.036 40.56 69.12 40.584 ;
    END
  END b_desc_loops[1]
  PIN b_desc_loops[2]
    DIRECTION OUTPUT ;
    USE SIGNAL ;
    PORT
      LAYER M4 ;
        RECT  69.036 40.656 69.12 40.68 ;
    END
  END b_desc_loops[2]
  PIN b_desc_loops[3]
    DIRECTION OUTPUT ;
    USE SIGNAL ;
    PORT
      LAYER M4 ;
        RECT  69.036 40.752 69.12 40.776 ;
    END
  END b_desc_loops[3]
  PIN b_desc_loops[4]
    DIRECTION OUTPUT ;
    USE SIGNAL ;
    PORT
      LAYER M4 ;
        RECT  69.036 40.848 69.12 40.872 ;
    END
  END b_desc_loops[4]
  PIN b_desc_loops[5]
    DIRECTION OUTPUT ;
    USE SIGNAL ;
    PORT
      LAYER M4 ;
        RECT  69.036 40.944 69.12 40.968 ;
    END
  END b_desc_loops[5]
  PIN b_desc_loops[6]
    DIRECTION OUTPUT ;
    USE SIGNAL ;
    PORT
      LAYER M4 ;
        RECT  69.036 41.04 69.12 41.064 ;
    END
  END b_desc_loops[6]
  PIN b_desc_loops[7]
    DIRECTION OUTPUT ;
    USE SIGNAL ;
    PORT
      LAYER M4 ;
        RECT  69.036 41.136 69.12 41.16 ;
    END
  END b_desc_loops[7]
  PIN b_desc_loops[8]
    DIRECTION OUTPUT ;
    USE SIGNAL ;
    PORT
      LAYER M4 ;
        RECT  69.036 41.232 69.12 41.256 ;
    END
  END b_desc_loops[8]
  PIN b_desc_loops[9]
    DIRECTION OUTPUT ;
    USE SIGNAL ;
    PORT
      LAYER M4 ;
        RECT  69.036 41.328 69.12 41.352 ;
    END
  END b_desc_loops[9]
  PIN b_desc_v
    DIRECTION OUTPUT ;
    USE SIGNAL ;
    PORT
      LAYER M4 ;
        RECT  69.036 42 69.12 42.024 ;
    END
  END b_desc_v
  PIN b_launch_v
    DIRECTION OUTPUT ;
    USE SIGNAL ;
    PORT
      LAYER M4 ;
        RECT  69.036 42.096 69.12 42.12 ;
    END
  END b_launch_v
  PIN cfg_addr[0]
    DIRECTION INPUT ;
    USE SIGNAL ;
    PORT
      LAYER M5 ;
        RECT  39.984 69.036 40.008 69.12 ;
    END
  END cfg_addr[0]
  PIN cfg_addr[10]
    DIRECTION INPUT ;
    USE SIGNAL ;
    PORT
      LAYER M5 ;
        RECT  40.944 69.036 40.968 69.12 ;
    END
  END cfg_addr[10]
  PIN cfg_addr[11]
    DIRECTION INPUT ;
    USE SIGNAL ;
    PORT
      LAYER M5 ;
        RECT  41.04 69.036 41.064 69.12 ;
    END
  END cfg_addr[11]
  PIN cfg_addr[1]
    DIRECTION INPUT ;
    USE SIGNAL ;
    PORT
      LAYER M5 ;
        RECT  40.08 69.036 40.104 69.12 ;
    END
  END cfg_addr[1]
  PIN cfg_addr[2]
    DIRECTION INPUT ;
    USE SIGNAL ;
    PORT
      LAYER M5 ;
        RECT  40.176 69.036 40.2 69.12 ;
    END
  END cfg_addr[2]
  PIN cfg_addr[3]
    DIRECTION INPUT ;
    USE SIGNAL ;
    PORT
      LAYER M5 ;
        RECT  40.272 69.036 40.296 69.12 ;
    END
  END cfg_addr[3]
  PIN cfg_addr[4]
    DIRECTION INPUT ;
    USE SIGNAL ;
    PORT
      LAYER M5 ;
        RECT  40.368 69.036 40.392 69.12 ;
    END
  END cfg_addr[4]
  PIN cfg_addr[5]
    DIRECTION INPUT ;
    USE SIGNAL ;
    PORT
      LAYER M5 ;
        RECT  40.464 69.036 40.488 69.12 ;
    END
  END cfg_addr[5]
  PIN cfg_addr[6]
    DIRECTION INPUT ;
    USE SIGNAL ;
    PORT
      LAYER M5 ;
        RECT  40.56 69.036 40.584 69.12 ;
    END
  END cfg_addr[6]
  PIN cfg_addr[7]
    DIRECTION INPUT ;
    USE SIGNAL ;
    PORT
      LAYER M5 ;
        RECT  40.656 69.036 40.68 69.12 ;
    END
  END cfg_addr[7]
  PIN cfg_addr[8]
    DIRECTION INPUT ;
    USE SIGNAL ;
    PORT
      LAYER M5 ;
        RECT  40.752 69.036 40.776 69.12 ;
    END
  END cfg_addr[8]
  PIN cfg_addr[9]
    DIRECTION INPUT ;
    USE SIGNAL ;
    PORT
      LAYER M5 ;
        RECT  40.848 69.036 40.872 69.12 ;
    END
  END cfg_addr[9]
  PIN cfg_data[0]
    DIRECTION INPUT ;
    USE SIGNAL ;
    PORT
      LAYER M5 ;
        RECT  41.136 69.036 41.16 69.12 ;
    END
  END cfg_data[0]
  PIN cfg_data[100]
    DIRECTION INPUT ;
    USE SIGNAL ;
    PORT
      LAYER M5 ;
        RECT  47.664 69.036 47.688 69.12 ;
    END
  END cfg_data[100]
  PIN cfg_data[101]
    DIRECTION INPUT ;
    USE SIGNAL ;
    PORT
      LAYER M5 ;
        RECT  47.76 69.036 47.784 69.12 ;
    END
  END cfg_data[101]
  PIN cfg_data[102]
    DIRECTION INPUT ;
    USE SIGNAL ;
    PORT
      LAYER M5 ;
        RECT  47.856 69.036 47.88 69.12 ;
    END
  END cfg_data[102]
  PIN cfg_data[103]
    DIRECTION INPUT ;
    USE SIGNAL ;
    PORT
      LAYER M5 ;
        RECT  47.952 69.036 47.976 69.12 ;
    END
  END cfg_data[103]
  PIN cfg_data[104]
    DIRECTION INPUT ;
    USE SIGNAL ;
    PORT
      LAYER M5 ;
        RECT  48.048 69.036 48.072 69.12 ;
    END
  END cfg_data[104]
  PIN cfg_data[105]
    DIRECTION INPUT ;
    USE SIGNAL ;
    PORT
      LAYER M5 ;
        RECT  48.144 69.036 48.168 69.12 ;
    END
  END cfg_data[105]
  PIN cfg_data[106]
    DIRECTION INPUT ;
    USE SIGNAL ;
    PORT
      LAYER M5 ;
        RECT  48.24 69.036 48.264 69.12 ;
    END
  END cfg_data[106]
  PIN cfg_data[107]
    DIRECTION INPUT ;
    USE SIGNAL ;
    PORT
      LAYER M5 ;
        RECT  48.336 69.036 48.36 69.12 ;
    END
  END cfg_data[107]
  PIN cfg_data[108]
    DIRECTION INPUT ;
    USE SIGNAL ;
    PORT
      LAYER M5 ;
        RECT  48.432 69.036 48.456 69.12 ;
    END
  END cfg_data[108]
  PIN cfg_data[109]
    DIRECTION INPUT ;
    USE SIGNAL ;
    PORT
      LAYER M5 ;
        RECT  48.528 69.036 48.552 69.12 ;
    END
  END cfg_data[109]
  PIN cfg_data[10]
    DIRECTION INPUT ;
    USE SIGNAL ;
    PORT
      LAYER M5 ;
        RECT  42.096 69.036 42.12 69.12 ;
    END
  END cfg_data[10]
  PIN cfg_data[110]
    DIRECTION INPUT ;
    USE SIGNAL ;
    PORT
      LAYER M5 ;
        RECT  48.624 69.036 48.648 69.12 ;
    END
  END cfg_data[110]
  PIN cfg_data[111]
    DIRECTION INPUT ;
    USE SIGNAL ;
    PORT
      LAYER M5 ;
        RECT  48.72 69.036 48.744 69.12 ;
    END
  END cfg_data[111]
  PIN cfg_data[112]
    DIRECTION INPUT ;
    USE SIGNAL ;
    PORT
      LAYER M5 ;
        RECT  48.816 69.036 48.84 69.12 ;
    END
  END cfg_data[112]
  PIN cfg_data[113]
    DIRECTION INPUT ;
    USE SIGNAL ;
    PORT
      LAYER M5 ;
        RECT  48.912 69.036 48.936 69.12 ;
    END
  END cfg_data[113]
  PIN cfg_data[114]
    DIRECTION INPUT ;
    USE SIGNAL ;
    PORT
      LAYER M5 ;
        RECT  49.008 69.036 49.032 69.12 ;
    END
  END cfg_data[114]
  PIN cfg_data[115]
    DIRECTION INPUT ;
    USE SIGNAL ;
    PORT
      LAYER M5 ;
        RECT  49.104 69.036 49.128 69.12 ;
    END
  END cfg_data[115]
  PIN cfg_data[116]
    DIRECTION INPUT ;
    USE SIGNAL ;
    PORT
      LAYER M5 ;
        RECT  36.912 69.036 36.936 69.12 ;
    END
  END cfg_data[116]
  PIN cfg_data[117]
    DIRECTION INPUT ;
    USE SIGNAL ;
    PORT
      LAYER M5 ;
        RECT  37.008 69.036 37.032 69.12 ;
    END
  END cfg_data[117]
  PIN cfg_data[118]
    DIRECTION INPUT ;
    USE SIGNAL ;
    PORT
      LAYER M5 ;
        RECT  37.104 69.036 37.128 69.12 ;
    END
  END cfg_data[118]
  PIN cfg_data[119]
    DIRECTION INPUT ;
    USE SIGNAL ;
    PORT
      LAYER M5 ;
        RECT  37.2 69.036 37.224 69.12 ;
    END
  END cfg_data[119]
  PIN cfg_data[11]
    DIRECTION INPUT ;
    USE SIGNAL ;
    PORT
      LAYER M5 ;
        RECT  42.192 69.036 42.216 69.12 ;
    END
  END cfg_data[11]
  PIN cfg_data[120]
    DIRECTION INPUT ;
    USE SIGNAL ;
    PORT
      LAYER M5 ;
        RECT  37.296 69.036 37.32 69.12 ;
    END
  END cfg_data[120]
  PIN cfg_data[121]
    DIRECTION INPUT ;
    USE SIGNAL ;
    PORT
      LAYER M5 ;
        RECT  37.392 69.036 37.416 69.12 ;
    END
  END cfg_data[121]
  PIN cfg_data[122]
    DIRECTION INPUT ;
    USE SIGNAL ;
    PORT
      LAYER M5 ;
        RECT  37.488 69.036 37.512 69.12 ;
    END
  END cfg_data[122]
  PIN cfg_data[123]
    DIRECTION INPUT ;
    USE SIGNAL ;
    PORT
      LAYER M5 ;
        RECT  37.584 69.036 37.608 69.12 ;
    END
  END cfg_data[123]
  PIN cfg_data[124]
    DIRECTION INPUT ;
    USE SIGNAL ;
    PORT
      LAYER M5 ;
        RECT  37.68 69.036 37.704 69.12 ;
    END
  END cfg_data[124]
  PIN cfg_data[125]
    DIRECTION INPUT ;
    USE SIGNAL ;
    PORT
      LAYER M5 ;
        RECT  37.776 69.036 37.8 69.12 ;
    END
  END cfg_data[125]
  PIN cfg_data[126]
    DIRECTION INPUT ;
    USE SIGNAL ;
    PORT
      LAYER M5 ;
        RECT  37.872 69.036 37.896 69.12 ;
    END
  END cfg_data[126]
  PIN cfg_data[127]
    DIRECTION INPUT ;
    USE SIGNAL ;
    PORT
      LAYER M5 ;
        RECT  37.968 69.036 37.992 69.12 ;
    END
  END cfg_data[127]
  PIN cfg_data[128]
    DIRECTION INPUT ;
    USE SIGNAL ;
    PORT
      LAYER M5 ;
        RECT  38.064 69.036 38.088 69.12 ;
    END
  END cfg_data[128]
  PIN cfg_data[129]
    DIRECTION INPUT ;
    USE SIGNAL ;
    PORT
      LAYER M5 ;
        RECT  38.16 69.036 38.184 69.12 ;
    END
  END cfg_data[129]
  PIN cfg_data[12]
    DIRECTION INPUT ;
    USE SIGNAL ;
    PORT
      LAYER M5 ;
        RECT  42.288 69.036 42.312 69.12 ;
    END
  END cfg_data[12]
  PIN cfg_data[130]
    DIRECTION INPUT ;
    USE SIGNAL ;
    PORT
      LAYER M5 ;
        RECT  38.256 69.036 38.28 69.12 ;
    END
  END cfg_data[130]
  PIN cfg_data[131]
    DIRECTION INPUT ;
    USE SIGNAL ;
    PORT
      LAYER M5 ;
        RECT  38.352 69.036 38.376 69.12 ;
    END
  END cfg_data[131]
  PIN cfg_data[132]
    DIRECTION INPUT ;
    USE SIGNAL ;
    PORT
      LAYER M5 ;
        RECT  38.448 69.036 38.472 69.12 ;
    END
  END cfg_data[132]
  PIN cfg_data[133]
    DIRECTION INPUT ;
    USE SIGNAL ;
    PORT
      LAYER M5 ;
        RECT  38.544 69.036 38.568 69.12 ;
    END
  END cfg_data[133]
  PIN cfg_data[134]
    DIRECTION INPUT ;
    USE SIGNAL ;
    PORT
      LAYER M5 ;
        RECT  38.64 69.036 38.664 69.12 ;
    END
  END cfg_data[134]
  PIN cfg_data[135]
    DIRECTION INPUT ;
    USE SIGNAL ;
    PORT
      LAYER M5 ;
        RECT  38.736 69.036 38.76 69.12 ;
    END
  END cfg_data[135]
  PIN cfg_data[136]
    DIRECTION INPUT ;
    USE SIGNAL ;
    PORT
      LAYER M5 ;
        RECT  38.832 69.036 38.856 69.12 ;
    END
  END cfg_data[136]
  PIN cfg_data[137]
    DIRECTION INPUT ;
    USE SIGNAL ;
    PORT
      LAYER M5 ;
        RECT  38.928 69.036 38.952 69.12 ;
    END
  END cfg_data[137]
  PIN cfg_data[138]
    DIRECTION INPUT ;
    USE SIGNAL ;
    PORT
      LAYER M5 ;
        RECT  39.024 69.036 39.048 69.12 ;
    END
  END cfg_data[138]
  PIN cfg_data[139]
    DIRECTION INPUT ;
    USE SIGNAL ;
    PORT
      LAYER M5 ;
        RECT  39.12 69.036 39.144 69.12 ;
    END
  END cfg_data[139]
  PIN cfg_data[13]
    DIRECTION INPUT ;
    USE SIGNAL ;
    PORT
      LAYER M5 ;
        RECT  42.384 69.036 42.408 69.12 ;
    END
  END cfg_data[13]
  PIN cfg_data[140]
    DIRECTION INPUT ;
    USE SIGNAL ;
    PORT
      LAYER M5 ;
        RECT  39.216 69.036 39.24 69.12 ;
    END
  END cfg_data[140]
  PIN cfg_data[141]
    DIRECTION INPUT ;
    USE SIGNAL ;
    PORT
      LAYER M5 ;
        RECT  39.312 69.036 39.336 69.12 ;
    END
  END cfg_data[141]
  PIN cfg_data[142]
    DIRECTION INPUT ;
    USE SIGNAL ;
    PORT
      LAYER M5 ;
        RECT  39.408 69.036 39.432 69.12 ;
    END
  END cfg_data[142]
  PIN cfg_data[143]
    DIRECTION INPUT ;
    USE SIGNAL ;
    PORT
      LAYER M5 ;
        RECT  39.504 69.036 39.528 69.12 ;
    END
  END cfg_data[143]
  PIN cfg_data[144]
    DIRECTION INPUT ;
    USE SIGNAL ;
    PORT
      LAYER M5 ;
        RECT  39.6 69.036 39.624 69.12 ;
    END
  END cfg_data[144]
  PIN cfg_data[145]
    DIRECTION INPUT ;
    USE SIGNAL ;
    PORT
      LAYER M5 ;
        RECT  39.696 69.036 39.72 69.12 ;
    END
  END cfg_data[145]
  PIN cfg_data[146]
    DIRECTION INPUT ;
    USE SIGNAL ;
    PORT
      LAYER M5 ;
        RECT  39.792 69.036 39.816 69.12 ;
    END
  END cfg_data[146]
  PIN cfg_data[147]
    DIRECTION INPUT ;
    USE SIGNAL ;
    PORT
      LAYER M5 ;
        RECT  39.888 69.036 39.912 69.12 ;
    END
  END cfg_data[147]
  PIN cfg_data[148]
    DIRECTION INPUT ;
    USE SIGNAL ;
    PORT
      LAYER M5 ;
        RECT  30.768 69.036 30.792 69.12 ;
    END
  END cfg_data[148]
  PIN cfg_data[149]
    DIRECTION INPUT ;
    USE SIGNAL ;
    PORT
      LAYER M5 ;
        RECT  30.864 69.036 30.888 69.12 ;
    END
  END cfg_data[149]
  PIN cfg_data[14]
    DIRECTION INPUT ;
    USE SIGNAL ;
    PORT
      LAYER M5 ;
        RECT  42.48 69.036 42.504 69.12 ;
    END
  END cfg_data[14]
  PIN cfg_data[150]
    DIRECTION INPUT ;
    USE SIGNAL ;
    PORT
      LAYER M5 ;
        RECT  30.96 69.036 30.984 69.12 ;
    END
  END cfg_data[150]
  PIN cfg_data[151]
    DIRECTION INPUT ;
    USE SIGNAL ;
    PORT
      LAYER M5 ;
        RECT  31.056 69.036 31.08 69.12 ;
    END
  END cfg_data[151]
  PIN cfg_data[152]
    DIRECTION INPUT ;
    USE SIGNAL ;
    PORT
      LAYER M5 ;
        RECT  31.152 69.036 31.176 69.12 ;
    END
  END cfg_data[152]
  PIN cfg_data[153]
    DIRECTION INPUT ;
    USE SIGNAL ;
    PORT
      LAYER M5 ;
        RECT  31.248 69.036 31.272 69.12 ;
    END
  END cfg_data[153]
  PIN cfg_data[154]
    DIRECTION INPUT ;
    USE SIGNAL ;
    PORT
      LAYER M5 ;
        RECT  31.344 69.036 31.368 69.12 ;
    END
  END cfg_data[154]
  PIN cfg_data[155]
    DIRECTION INPUT ;
    USE SIGNAL ;
    PORT
      LAYER M5 ;
        RECT  31.44 69.036 31.464 69.12 ;
    END
  END cfg_data[155]
  PIN cfg_data[156]
    DIRECTION INPUT ;
    USE SIGNAL ;
    PORT
      LAYER M5 ;
        RECT  31.536 69.036 31.56 69.12 ;
    END
  END cfg_data[156]
  PIN cfg_data[157]
    DIRECTION INPUT ;
    USE SIGNAL ;
    PORT
      LAYER M5 ;
        RECT  31.632 69.036 31.656 69.12 ;
    END
  END cfg_data[157]
  PIN cfg_data[158]
    DIRECTION INPUT ;
    USE SIGNAL ;
    PORT
      LAYER M5 ;
        RECT  31.728 69.036 31.752 69.12 ;
    END
  END cfg_data[158]
  PIN cfg_data[159]
    DIRECTION INPUT ;
    USE SIGNAL ;
    PORT
      LAYER M5 ;
        RECT  31.824 69.036 31.848 69.12 ;
    END
  END cfg_data[159]
  PIN cfg_data[15]
    DIRECTION INPUT ;
    USE SIGNAL ;
    PORT
      LAYER M5 ;
        RECT  42.576 69.036 42.6 69.12 ;
    END
  END cfg_data[15]
  PIN cfg_data[160]
    DIRECTION INPUT ;
    USE SIGNAL ;
    PORT
      LAYER M5 ;
        RECT  31.92 69.036 31.944 69.12 ;
    END
  END cfg_data[160]
  PIN cfg_data[161]
    DIRECTION INPUT ;
    USE SIGNAL ;
    PORT
      LAYER M5 ;
        RECT  32.016 69.036 32.04 69.12 ;
    END
  END cfg_data[161]
  PIN cfg_data[162]
    DIRECTION INPUT ;
    USE SIGNAL ;
    PORT
      LAYER M5 ;
        RECT  32.112 69.036 32.136 69.12 ;
    END
  END cfg_data[162]
  PIN cfg_data[163]
    DIRECTION INPUT ;
    USE SIGNAL ;
    PORT
      LAYER M5 ;
        RECT  32.208 69.036 32.232 69.12 ;
    END
  END cfg_data[163]
  PIN cfg_data[164]
    DIRECTION INPUT ;
    USE SIGNAL ;
    PORT
      LAYER M5 ;
        RECT  32.304 69.036 32.328 69.12 ;
    END
  END cfg_data[164]
  PIN cfg_data[165]
    DIRECTION INPUT ;
    USE SIGNAL ;
    PORT
      LAYER M5 ;
        RECT  32.4 69.036 32.424 69.12 ;
    END
  END cfg_data[165]
  PIN cfg_data[166]
    DIRECTION INPUT ;
    USE SIGNAL ;
    PORT
      LAYER M5 ;
        RECT  32.496 69.036 32.52 69.12 ;
    END
  END cfg_data[166]
  PIN cfg_data[167]
    DIRECTION INPUT ;
    USE SIGNAL ;
    PORT
      LAYER M5 ;
        RECT  32.592 69.036 32.616 69.12 ;
    END
  END cfg_data[167]
  PIN cfg_data[168]
    DIRECTION INPUT ;
    USE SIGNAL ;
    PORT
      LAYER M5 ;
        RECT  32.688 69.036 32.712 69.12 ;
    END
  END cfg_data[168]
  PIN cfg_data[169]
    DIRECTION INPUT ;
    USE SIGNAL ;
    PORT
      LAYER M5 ;
        RECT  32.784 69.036 32.808 69.12 ;
    END
  END cfg_data[169]
  PIN cfg_data[16]
    DIRECTION INPUT ;
    USE SIGNAL ;
    PORT
      LAYER M5 ;
        RECT  42.672 69.036 42.696 69.12 ;
    END
  END cfg_data[16]
  PIN cfg_data[170]
    DIRECTION INPUT ;
    USE SIGNAL ;
    PORT
      LAYER M5 ;
        RECT  32.88 69.036 32.904 69.12 ;
    END
  END cfg_data[170]
  PIN cfg_data[171]
    DIRECTION INPUT ;
    USE SIGNAL ;
    PORT
      LAYER M5 ;
        RECT  32.976 69.036 33 69.12 ;
    END
  END cfg_data[171]
  PIN cfg_data[172]
    DIRECTION INPUT ;
    USE SIGNAL ;
    PORT
      LAYER M5 ;
        RECT  33.072 69.036 33.096 69.12 ;
    END
  END cfg_data[172]
  PIN cfg_data[173]
    DIRECTION INPUT ;
    USE SIGNAL ;
    PORT
      LAYER M5 ;
        RECT  33.168 69.036 33.192 69.12 ;
    END
  END cfg_data[173]
  PIN cfg_data[174]
    DIRECTION INPUT ;
    USE SIGNAL ;
    PORT
      LAYER M5 ;
        RECT  33.264 69.036 33.288 69.12 ;
    END
  END cfg_data[174]
  PIN cfg_data[175]
    DIRECTION INPUT ;
    USE SIGNAL ;
    PORT
      LAYER M5 ;
        RECT  33.36 69.036 33.384 69.12 ;
    END
  END cfg_data[175]
  PIN cfg_data[176]
    DIRECTION INPUT ;
    USE SIGNAL ;
    PORT
      LAYER M5 ;
        RECT  33.456 69.036 33.48 69.12 ;
    END
  END cfg_data[176]
  PIN cfg_data[177]
    DIRECTION INPUT ;
    USE SIGNAL ;
    PORT
      LAYER M5 ;
        RECT  33.552 69.036 33.576 69.12 ;
    END
  END cfg_data[177]
  PIN cfg_data[178]
    DIRECTION INPUT ;
    USE SIGNAL ;
    PORT
      LAYER M5 ;
        RECT  33.648 69.036 33.672 69.12 ;
    END
  END cfg_data[178]
  PIN cfg_data[179]
    DIRECTION INPUT ;
    USE SIGNAL ;
    PORT
      LAYER M5 ;
        RECT  33.744 69.036 33.768 69.12 ;
    END
  END cfg_data[179]
  PIN cfg_data[17]
    DIRECTION INPUT ;
    USE SIGNAL ;
    PORT
      LAYER M5 ;
        RECT  42.768 69.036 42.792 69.12 ;
    END
  END cfg_data[17]
  PIN cfg_data[180]
    DIRECTION INPUT ;
    USE SIGNAL ;
    PORT
      LAYER M5 ;
        RECT  43.056 69.036 43.08 69.12 ;
    END
  END cfg_data[180]
  PIN cfg_data[181]
    DIRECTION INPUT ;
    USE SIGNAL ;
    PORT
      LAYER M5 ;
        RECT  43.152 69.036 43.176 69.12 ;
    END
  END cfg_data[181]
  PIN cfg_data[182]
    DIRECTION INPUT ;
    USE SIGNAL ;
    PORT
      LAYER M5 ;
        RECT  43.248 69.036 43.272 69.12 ;
    END
  END cfg_data[182]
  PIN cfg_data[183]
    DIRECTION INPUT ;
    USE SIGNAL ;
    PORT
      LAYER M5 ;
        RECT  43.344 69.036 43.368 69.12 ;
    END
  END cfg_data[183]
  PIN cfg_data[184]
    DIRECTION INPUT ;
    USE SIGNAL ;
    PORT
      LAYER M5 ;
        RECT  43.44 69.036 43.464 69.12 ;
    END
  END cfg_data[184]
  PIN cfg_data[185]
    DIRECTION INPUT ;
    USE SIGNAL ;
    PORT
      LAYER M5 ;
        RECT  43.536 69.036 43.56 69.12 ;
    END
  END cfg_data[185]
  PIN cfg_data[186]
    DIRECTION INPUT ;
    USE SIGNAL ;
    PORT
      LAYER M5 ;
        RECT  43.632 69.036 43.656 69.12 ;
    END
  END cfg_data[186]
  PIN cfg_data[187]
    DIRECTION INPUT ;
    USE SIGNAL ;
    PORT
      LAYER M5 ;
        RECT  43.728 69.036 43.752 69.12 ;
    END
  END cfg_data[187]
  PIN cfg_data[188]
    DIRECTION INPUT ;
    USE SIGNAL ;
    PORT
      LAYER M5 ;
        RECT  43.824 69.036 43.848 69.12 ;
    END
  END cfg_data[188]
  PIN cfg_data[189]
    DIRECTION INPUT ;
    USE SIGNAL ;
    PORT
      LAYER M5 ;
        RECT  43.92 69.036 43.944 69.12 ;
    END
  END cfg_data[189]
  PIN cfg_data[18]
    DIRECTION INPUT ;
    USE SIGNAL ;
    PORT
      LAYER M5 ;
        RECT  42.864 69.036 42.888 69.12 ;
    END
  END cfg_data[18]
  PIN cfg_data[190]
    DIRECTION INPUT ;
    USE SIGNAL ;
    PORT
      LAYER M5 ;
        RECT  44.016 69.036 44.04 69.12 ;
    END
  END cfg_data[190]
  PIN cfg_data[191]
    DIRECTION INPUT ;
    USE SIGNAL ;
    PORT
      LAYER M5 ;
        RECT  44.112 69.036 44.136 69.12 ;
    END
  END cfg_data[191]
  PIN cfg_data[192]
    DIRECTION INPUT ;
    USE SIGNAL ;
    PORT
      LAYER M5 ;
        RECT  44.208 69.036 44.232 69.12 ;
    END
  END cfg_data[192]
  PIN cfg_data[193]
    DIRECTION INPUT ;
    USE SIGNAL ;
    PORT
      LAYER M5 ;
        RECT  44.304 69.036 44.328 69.12 ;
    END
  END cfg_data[193]
  PIN cfg_data[194]
    DIRECTION INPUT ;
    USE SIGNAL ;
    PORT
      LAYER M5 ;
        RECT  44.4 69.036 44.424 69.12 ;
    END
  END cfg_data[194]
  PIN cfg_data[195]
    DIRECTION INPUT ;
    USE SIGNAL ;
    PORT
      LAYER M5 ;
        RECT  44.496 69.036 44.52 69.12 ;
    END
  END cfg_data[195]
  PIN cfg_data[196]
    DIRECTION INPUT ;
    USE SIGNAL ;
    PORT
      LAYER M5 ;
        RECT  44.592 69.036 44.616 69.12 ;
    END
  END cfg_data[196]
  PIN cfg_data[197]
    DIRECTION INPUT ;
    USE SIGNAL ;
    PORT
      LAYER M5 ;
        RECT  44.688 69.036 44.712 69.12 ;
    END
  END cfg_data[197]
  PIN cfg_data[198]
    DIRECTION INPUT ;
    USE SIGNAL ;
    PORT
      LAYER M5 ;
        RECT  44.784 69.036 44.808 69.12 ;
    END
  END cfg_data[198]
  PIN cfg_data[199]
    DIRECTION INPUT ;
    USE SIGNAL ;
    PORT
      LAYER M5 ;
        RECT  44.88 69.036 44.904 69.12 ;
    END
  END cfg_data[199]
  PIN cfg_data[19]
    DIRECTION INPUT ;
    USE SIGNAL ;
    PORT
      LAYER M5 ;
        RECT  42.96 69.036 42.984 69.12 ;
    END
  END cfg_data[19]
  PIN cfg_data[1]
    DIRECTION INPUT ;
    USE SIGNAL ;
    PORT
      LAYER M5 ;
        RECT  41.232 69.036 41.256 69.12 ;
    END
  END cfg_data[1]
  PIN cfg_data[200]
    DIRECTION INPUT ;
    USE SIGNAL ;
    PORT
      LAYER M5 ;
        RECT  44.976 69.036 45 69.12 ;
    END
  END cfg_data[200]
  PIN cfg_data[201]
    DIRECTION INPUT ;
    USE SIGNAL ;
    PORT
      LAYER M5 ;
        RECT  45.072 69.036 45.096 69.12 ;
    END
  END cfg_data[201]
  PIN cfg_data[202]
    DIRECTION INPUT ;
    USE SIGNAL ;
    PORT
      LAYER M5 ;
        RECT  45.168 69.036 45.192 69.12 ;
    END
  END cfg_data[202]
  PIN cfg_data[203]
    DIRECTION INPUT ;
    USE SIGNAL ;
    PORT
      LAYER M5 ;
        RECT  45.264 69.036 45.288 69.12 ;
    END
  END cfg_data[203]
  PIN cfg_data[204]
    DIRECTION INPUT ;
    USE SIGNAL ;
    PORT
      LAYER M5 ;
        RECT  45.36 69.036 45.384 69.12 ;
    END
  END cfg_data[204]
  PIN cfg_data[205]
    DIRECTION INPUT ;
    USE SIGNAL ;
    PORT
      LAYER M5 ;
        RECT  45.456 69.036 45.48 69.12 ;
    END
  END cfg_data[205]
  PIN cfg_data[206]
    DIRECTION INPUT ;
    USE SIGNAL ;
    PORT
      LAYER M5 ;
        RECT  45.552 69.036 45.576 69.12 ;
    END
  END cfg_data[206]
  PIN cfg_data[207]
    DIRECTION INPUT ;
    USE SIGNAL ;
    PORT
      LAYER M5 ;
        RECT  45.648 69.036 45.672 69.12 ;
    END
  END cfg_data[207]
  PIN cfg_data[208]
    DIRECTION INPUT ;
    USE SIGNAL ;
    PORT
      LAYER M5 ;
        RECT  45.744 69.036 45.768 69.12 ;
    END
  END cfg_data[208]
  PIN cfg_data[209]
    DIRECTION INPUT ;
    USE SIGNAL ;
    PORT
      LAYER M5 ;
        RECT  45.84 69.036 45.864 69.12 ;
    END
  END cfg_data[209]
  PIN cfg_data[20]
    DIRECTION INPUT ;
    USE SIGNAL ;
    PORT
      LAYER M5 ;
        RECT  17.712 69.036 17.736 69.12 ;
    END
  END cfg_data[20]
  PIN cfg_data[210]
    DIRECTION INPUT ;
    USE SIGNAL ;
    PORT
      LAYER M5 ;
        RECT  45.936 69.036 45.96 69.12 ;
    END
  END cfg_data[210]
  PIN cfg_data[211]
    DIRECTION INPUT ;
    USE SIGNAL ;
    PORT
      LAYER M5 ;
        RECT  46.032 69.036 46.056 69.12 ;
    END
  END cfg_data[211]
  PIN cfg_data[212]
    DIRECTION INPUT ;
    USE SIGNAL ;
    PORT
      LAYER M5 ;
        RECT  26.928 69.036 26.952 69.12 ;
    END
  END cfg_data[212]
  PIN cfg_data[213]
    DIRECTION INPUT ;
    USE SIGNAL ;
    PORT
      LAYER M5 ;
        RECT  27.024 69.036 27.048 69.12 ;
    END
  END cfg_data[213]
  PIN cfg_data[214]
    DIRECTION INPUT ;
    USE SIGNAL ;
    PORT
      LAYER M5 ;
        RECT  27.12 69.036 27.144 69.12 ;
    END
  END cfg_data[214]
  PIN cfg_data[215]
    DIRECTION INPUT ;
    USE SIGNAL ;
    PORT
      LAYER M5 ;
        RECT  27.216 69.036 27.24 69.12 ;
    END
  END cfg_data[215]
  PIN cfg_data[216]
    DIRECTION INPUT ;
    USE SIGNAL ;
    PORT
      LAYER M5 ;
        RECT  27.312 69.036 27.336 69.12 ;
    END
  END cfg_data[216]
  PIN cfg_data[217]
    DIRECTION INPUT ;
    USE SIGNAL ;
    PORT
      LAYER M5 ;
        RECT  27.408 69.036 27.432 69.12 ;
    END
  END cfg_data[217]
  PIN cfg_data[218]
    DIRECTION INPUT ;
    USE SIGNAL ;
    PORT
      LAYER M5 ;
        RECT  27.504 69.036 27.528 69.12 ;
    END
  END cfg_data[218]
  PIN cfg_data[219]
    DIRECTION INPUT ;
    USE SIGNAL ;
    PORT
      LAYER M5 ;
        RECT  27.6 69.036 27.624 69.12 ;
    END
  END cfg_data[219]
  PIN cfg_data[21]
    DIRECTION INPUT ;
    USE SIGNAL ;
    PORT
      LAYER M5 ;
        RECT  17.808 69.036 17.832 69.12 ;
    END
  END cfg_data[21]
  PIN cfg_data[220]
    DIRECTION INPUT ;
    USE SIGNAL ;
    PORT
      LAYER M5 ;
        RECT  27.696 69.036 27.72 69.12 ;
    END
  END cfg_data[220]
  PIN cfg_data[221]
    DIRECTION INPUT ;
    USE SIGNAL ;
    PORT
      LAYER M5 ;
        RECT  27.792 69.036 27.816 69.12 ;
    END
  END cfg_data[221]
  PIN cfg_data[222]
    DIRECTION INPUT ;
    USE SIGNAL ;
    PORT
      LAYER M5 ;
        RECT  27.888 69.036 27.912 69.12 ;
    END
  END cfg_data[222]
  PIN cfg_data[223]
    DIRECTION INPUT ;
    USE SIGNAL ;
    PORT
      LAYER M5 ;
        RECT  27.984 69.036 28.008 69.12 ;
    END
  END cfg_data[223]
  PIN cfg_data[224]
    DIRECTION INPUT ;
    USE SIGNAL ;
    PORT
      LAYER M5 ;
        RECT  28.08 69.036 28.104 69.12 ;
    END
  END cfg_data[224]
  PIN cfg_data[225]
    DIRECTION INPUT ;
    USE SIGNAL ;
    PORT
      LAYER M5 ;
        RECT  28.176 69.036 28.2 69.12 ;
    END
  END cfg_data[225]
  PIN cfg_data[226]
    DIRECTION INPUT ;
    USE SIGNAL ;
    PORT
      LAYER M5 ;
        RECT  28.272 69.036 28.296 69.12 ;
    END
  END cfg_data[226]
  PIN cfg_data[227]
    DIRECTION INPUT ;
    USE SIGNAL ;
    PORT
      LAYER M5 ;
        RECT  28.368 69.036 28.392 69.12 ;
    END
  END cfg_data[227]
  PIN cfg_data[228]
    DIRECTION INPUT ;
    USE SIGNAL ;
    PORT
      LAYER M5 ;
        RECT  28.464 69.036 28.488 69.12 ;
    END
  END cfg_data[228]
  PIN cfg_data[229]
    DIRECTION INPUT ;
    USE SIGNAL ;
    PORT
      LAYER M5 ;
        RECT  28.56 69.036 28.584 69.12 ;
    END
  END cfg_data[229]
  PIN cfg_data[22]
    DIRECTION INPUT ;
    USE SIGNAL ;
    PORT
      LAYER M5 ;
        RECT  17.904 69.036 17.928 69.12 ;
    END
  END cfg_data[22]
  PIN cfg_data[230]
    DIRECTION INPUT ;
    USE SIGNAL ;
    PORT
      LAYER M5 ;
        RECT  28.656 69.036 28.68 69.12 ;
    END
  END cfg_data[230]
  PIN cfg_data[231]
    DIRECTION INPUT ;
    USE SIGNAL ;
    PORT
      LAYER M5 ;
        RECT  28.752 69.036 28.776 69.12 ;
    END
  END cfg_data[231]
  PIN cfg_data[232]
    DIRECTION INPUT ;
    USE SIGNAL ;
    PORT
      LAYER M5 ;
        RECT  28.848 69.036 28.872 69.12 ;
    END
  END cfg_data[232]
  PIN cfg_data[233]
    DIRECTION INPUT ;
    USE SIGNAL ;
    PORT
      LAYER M5 ;
        RECT  28.944 69.036 28.968 69.12 ;
    END
  END cfg_data[233]
  PIN cfg_data[234]
    DIRECTION INPUT ;
    USE SIGNAL ;
    PORT
      LAYER M5 ;
        RECT  29.04 69.036 29.064 69.12 ;
    END
  END cfg_data[234]
  PIN cfg_data[235]
    DIRECTION INPUT ;
    USE SIGNAL ;
    PORT
      LAYER M5 ;
        RECT  29.136 69.036 29.16 69.12 ;
    END
  END cfg_data[235]
  PIN cfg_data[236]
    DIRECTION INPUT ;
    USE SIGNAL ;
    PORT
      LAYER M5 ;
        RECT  29.232 69.036 29.256 69.12 ;
    END
  END cfg_data[236]
  PIN cfg_data[237]
    DIRECTION INPUT ;
    USE SIGNAL ;
    PORT
      LAYER M5 ;
        RECT  29.328 69.036 29.352 69.12 ;
    END
  END cfg_data[237]
  PIN cfg_data[238]
    DIRECTION INPUT ;
    USE SIGNAL ;
    PORT
      LAYER M5 ;
        RECT  29.424 69.036 29.448 69.12 ;
    END
  END cfg_data[238]
  PIN cfg_data[239]
    DIRECTION INPUT ;
    USE SIGNAL ;
    PORT
      LAYER M5 ;
        RECT  29.52 69.036 29.544 69.12 ;
    END
  END cfg_data[239]
  PIN cfg_data[23]
    DIRECTION INPUT ;
    USE SIGNAL ;
    PORT
      LAYER M5 ;
        RECT  18 69.036 18.024 69.12 ;
    END
  END cfg_data[23]
  PIN cfg_data[240]
    DIRECTION INPUT ;
    USE SIGNAL ;
    PORT
      LAYER M5 ;
        RECT  29.616 69.036 29.64 69.12 ;
    END
  END cfg_data[240]
  PIN cfg_data[241]
    DIRECTION INPUT ;
    USE SIGNAL ;
    PORT
      LAYER M5 ;
        RECT  29.712 69.036 29.736 69.12 ;
    END
  END cfg_data[241]
  PIN cfg_data[242]
    DIRECTION INPUT ;
    USE SIGNAL ;
    PORT
      LAYER M5 ;
        RECT  29.808 69.036 29.832 69.12 ;
    END
  END cfg_data[242]
  PIN cfg_data[243]
    DIRECTION INPUT ;
    USE SIGNAL ;
    PORT
      LAYER M5 ;
        RECT  29.904 69.036 29.928 69.12 ;
    END
  END cfg_data[243]
  PIN cfg_data[244]
    DIRECTION INPUT ;
    USE SIGNAL ;
    PORT
      LAYER M5 ;
        RECT  23.856 69.036 23.88 69.12 ;
    END
  END cfg_data[244]
  PIN cfg_data[245]
    DIRECTION INPUT ;
    USE SIGNAL ;
    PORT
      LAYER M5 ;
        RECT  23.952 69.036 23.976 69.12 ;
    END
  END cfg_data[245]
  PIN cfg_data[246]
    DIRECTION INPUT ;
    USE SIGNAL ;
    PORT
      LAYER M5 ;
        RECT  24.048 69.036 24.072 69.12 ;
    END
  END cfg_data[246]
  PIN cfg_data[247]
    DIRECTION INPUT ;
    USE SIGNAL ;
    PORT
      LAYER M5 ;
        RECT  24.144 69.036 24.168 69.12 ;
    END
  END cfg_data[247]
  PIN cfg_data[248]
    DIRECTION INPUT ;
    USE SIGNAL ;
    PORT
      LAYER M5 ;
        RECT  24.24 69.036 24.264 69.12 ;
    END
  END cfg_data[248]
  PIN cfg_data[249]
    DIRECTION INPUT ;
    USE SIGNAL ;
    PORT
      LAYER M5 ;
        RECT  24.336 69.036 24.36 69.12 ;
    END
  END cfg_data[249]
  PIN cfg_data[24]
    DIRECTION INPUT ;
    USE SIGNAL ;
    PORT
      LAYER M5 ;
        RECT  18.096 69.036 18.12 69.12 ;
    END
  END cfg_data[24]
  PIN cfg_data[250]
    DIRECTION INPUT ;
    USE SIGNAL ;
    PORT
      LAYER M5 ;
        RECT  24.432 69.036 24.456 69.12 ;
    END
  END cfg_data[250]
  PIN cfg_data[251]
    DIRECTION INPUT ;
    USE SIGNAL ;
    PORT
      LAYER M5 ;
        RECT  24.528 69.036 24.552 69.12 ;
    END
  END cfg_data[251]
  PIN cfg_data[252]
    DIRECTION INPUT ;
    USE SIGNAL ;
    PORT
      LAYER M5 ;
        RECT  24.624 69.036 24.648 69.12 ;
    END
  END cfg_data[252]
  PIN cfg_data[253]
    DIRECTION INPUT ;
    USE SIGNAL ;
    PORT
      LAYER M5 ;
        RECT  24.72 69.036 24.744 69.12 ;
    END
  END cfg_data[253]
  PIN cfg_data[254]
    DIRECTION INPUT ;
    USE SIGNAL ;
    PORT
      LAYER M5 ;
        RECT  24.816 69.036 24.84 69.12 ;
    END
  END cfg_data[254]
  PIN cfg_data[255]
    DIRECTION INPUT ;
    USE SIGNAL ;
    PORT
      LAYER M5 ;
        RECT  24.912 69.036 24.936 69.12 ;
    END
  END cfg_data[255]
  PIN cfg_data[25]
    DIRECTION INPUT ;
    USE SIGNAL ;
    PORT
      LAYER M5 ;
        RECT  18.192 69.036 18.216 69.12 ;
    END
  END cfg_data[25]
  PIN cfg_data[26]
    DIRECTION INPUT ;
    USE SIGNAL ;
    PORT
      LAYER M5 ;
        RECT  18.288 69.036 18.312 69.12 ;
    END
  END cfg_data[26]
  PIN cfg_data[27]
    DIRECTION INPUT ;
    USE SIGNAL ;
    PORT
      LAYER M5 ;
        RECT  18.384 69.036 18.408 69.12 ;
    END
  END cfg_data[27]
  PIN cfg_data[28]
    DIRECTION INPUT ;
    USE SIGNAL ;
    PORT
      LAYER M5 ;
        RECT  18.48 69.036 18.504 69.12 ;
    END
  END cfg_data[28]
  PIN cfg_data[29]
    DIRECTION INPUT ;
    USE SIGNAL ;
    PORT
      LAYER M5 ;
        RECT  18.576 69.036 18.6 69.12 ;
    END
  END cfg_data[29]
  PIN cfg_data[2]
    DIRECTION INPUT ;
    USE SIGNAL ;
    PORT
      LAYER M5 ;
        RECT  41.328 69.036 41.352 69.12 ;
    END
  END cfg_data[2]
  PIN cfg_data[30]
    DIRECTION INPUT ;
    USE SIGNAL ;
    PORT
      LAYER M5 ;
        RECT  18.672 69.036 18.696 69.12 ;
    END
  END cfg_data[30]
  PIN cfg_data[31]
    DIRECTION INPUT ;
    USE SIGNAL ;
    PORT
      LAYER M5 ;
        RECT  18.768 69.036 18.792 69.12 ;
    END
  END cfg_data[31]
  PIN cfg_data[32]
    DIRECTION INPUT ;
    USE SIGNAL ;
    PORT
      LAYER M5 ;
        RECT  18.864 69.036 18.888 69.12 ;
    END
  END cfg_data[32]
  PIN cfg_data[33]
    DIRECTION INPUT ;
    USE SIGNAL ;
    PORT
      LAYER M5 ;
        RECT  18.96 69.036 18.984 69.12 ;
    END
  END cfg_data[33]
  PIN cfg_data[34]
    DIRECTION INPUT ;
    USE SIGNAL ;
    PORT
      LAYER M5 ;
        RECT  19.056 69.036 19.08 69.12 ;
    END
  END cfg_data[34]
  PIN cfg_data[35]
    DIRECTION INPUT ;
    USE SIGNAL ;
    PORT
      LAYER M5 ;
        RECT  19.152 69.036 19.176 69.12 ;
    END
  END cfg_data[35]
  PIN cfg_data[36]
    DIRECTION INPUT ;
    USE SIGNAL ;
    PORT
      LAYER M5 ;
        RECT  19.248 69.036 19.272 69.12 ;
    END
  END cfg_data[36]
  PIN cfg_data[37]
    DIRECTION INPUT ;
    USE SIGNAL ;
    PORT
      LAYER M5 ;
        RECT  19.344 69.036 19.368 69.12 ;
    END
  END cfg_data[37]
  PIN cfg_data[38]
    DIRECTION INPUT ;
    USE SIGNAL ;
    PORT
      LAYER M5 ;
        RECT  19.44 69.036 19.464 69.12 ;
    END
  END cfg_data[38]
  PIN cfg_data[39]
    DIRECTION INPUT ;
    USE SIGNAL ;
    PORT
      LAYER M5 ;
        RECT  19.536 69.036 19.56 69.12 ;
    END
  END cfg_data[39]
  PIN cfg_data[3]
    DIRECTION INPUT ;
    USE SIGNAL ;
    PORT
      LAYER M5 ;
        RECT  41.424 69.036 41.448 69.12 ;
    END
  END cfg_data[3]
  PIN cfg_data[40]
    DIRECTION INPUT ;
    USE SIGNAL ;
    PORT
      LAYER M5 ;
        RECT  19.632 69.036 19.656 69.12 ;
    END
  END cfg_data[40]
  PIN cfg_data[41]
    DIRECTION INPUT ;
    USE SIGNAL ;
    PORT
      LAYER M5 ;
        RECT  19.728 69.036 19.752 69.12 ;
    END
  END cfg_data[41]
  PIN cfg_data[42]
    DIRECTION INPUT ;
    USE SIGNAL ;
    PORT
      LAYER M5 ;
        RECT  19.824 69.036 19.848 69.12 ;
    END
  END cfg_data[42]
  PIN cfg_data[43]
    DIRECTION INPUT ;
    USE SIGNAL ;
    PORT
      LAYER M5 ;
        RECT  19.92 69.036 19.944 69.12 ;
    END
  END cfg_data[43]
  PIN cfg_data[44]
    DIRECTION INPUT ;
    USE SIGNAL ;
    PORT
      LAYER M5 ;
        RECT  20.016 69.036 20.04 69.12 ;
    END
  END cfg_data[44]
  PIN cfg_data[45]
    DIRECTION INPUT ;
    USE SIGNAL ;
    PORT
      LAYER M5 ;
        RECT  20.112 69.036 20.136 69.12 ;
    END
  END cfg_data[45]
  PIN cfg_data[46]
    DIRECTION INPUT ;
    USE SIGNAL ;
    PORT
      LAYER M5 ;
        RECT  20.208 69.036 20.232 69.12 ;
    END
  END cfg_data[46]
  PIN cfg_data[47]
    DIRECTION INPUT ;
    USE SIGNAL ;
    PORT
      LAYER M5 ;
        RECT  20.304 69.036 20.328 69.12 ;
    END
  END cfg_data[47]
  PIN cfg_data[48]
    DIRECTION INPUT ;
    USE SIGNAL ;
    PORT
      LAYER M5 ;
        RECT  20.4 69.036 20.424 69.12 ;
    END
  END cfg_data[48]
  PIN cfg_data[49]
    DIRECTION INPUT ;
    USE SIGNAL ;
    PORT
      LAYER M5 ;
        RECT  20.496 69.036 20.52 69.12 ;
    END
  END cfg_data[49]
  PIN cfg_data[4]
    DIRECTION INPUT ;
    USE SIGNAL ;
    PORT
      LAYER M5 ;
        RECT  41.52 69.036 41.544 69.12 ;
    END
  END cfg_data[4]
  PIN cfg_data[50]
    DIRECTION INPUT ;
    USE SIGNAL ;
    PORT
      LAYER M5 ;
        RECT  20.592 69.036 20.616 69.12 ;
    END
  END cfg_data[50]
  PIN cfg_data[51]
    DIRECTION INPUT ;
    USE SIGNAL ;
    PORT
      LAYER M5 ;
        RECT  20.688 69.036 20.712 69.12 ;
    END
  END cfg_data[51]
  PIN cfg_data[52]
    DIRECTION INPUT ;
    USE SIGNAL ;
    PORT
      LAYER M5 ;
        RECT  33.84 69.036 33.864 69.12 ;
    END
  END cfg_data[52]
  PIN cfg_data[53]
    DIRECTION INPUT ;
    USE SIGNAL ;
    PORT
      LAYER M5 ;
        RECT  33.936 69.036 33.96 69.12 ;
    END
  END cfg_data[53]
  PIN cfg_data[54]
    DIRECTION INPUT ;
    USE SIGNAL ;
    PORT
      LAYER M5 ;
        RECT  34.032 69.036 34.056 69.12 ;
    END
  END cfg_data[54]
  PIN cfg_data[55]
    DIRECTION INPUT ;
    USE SIGNAL ;
    PORT
      LAYER M5 ;
        RECT  34.128 69.036 34.152 69.12 ;
    END
  END cfg_data[55]
  PIN cfg_data[56]
    DIRECTION INPUT ;
    USE SIGNAL ;
    PORT
      LAYER M5 ;
        RECT  34.224 69.036 34.248 69.12 ;
    END
  END cfg_data[56]
  PIN cfg_data[57]
    DIRECTION INPUT ;
    USE SIGNAL ;
    PORT
      LAYER M5 ;
        RECT  34.32 69.036 34.344 69.12 ;
    END
  END cfg_data[57]
  PIN cfg_data[58]
    DIRECTION INPUT ;
    USE SIGNAL ;
    PORT
      LAYER M5 ;
        RECT  34.416 69.036 34.44 69.12 ;
    END
  END cfg_data[58]
  PIN cfg_data[59]
    DIRECTION INPUT ;
    USE SIGNAL ;
    PORT
      LAYER M5 ;
        RECT  34.512 69.036 34.536 69.12 ;
    END
  END cfg_data[59]
  PIN cfg_data[5]
    DIRECTION INPUT ;
    USE SIGNAL ;
    PORT
      LAYER M5 ;
        RECT  41.616 69.036 41.64 69.12 ;
    END
  END cfg_data[5]
  PIN cfg_data[60]
    DIRECTION INPUT ;
    USE SIGNAL ;
    PORT
      LAYER M5 ;
        RECT  34.608 69.036 34.632 69.12 ;
    END
  END cfg_data[60]
  PIN cfg_data[61]
    DIRECTION INPUT ;
    USE SIGNAL ;
    PORT
      LAYER M5 ;
        RECT  34.704 69.036 34.728 69.12 ;
    END
  END cfg_data[61]
  PIN cfg_data[62]
    DIRECTION INPUT ;
    USE SIGNAL ;
    PORT
      LAYER M5 ;
        RECT  34.8 69.036 34.824 69.12 ;
    END
  END cfg_data[62]
  PIN cfg_data[63]
    DIRECTION INPUT ;
    USE SIGNAL ;
    PORT
      LAYER M5 ;
        RECT  34.896 69.036 34.92 69.12 ;
    END
  END cfg_data[63]
  PIN cfg_data[64]
    DIRECTION INPUT ;
    USE SIGNAL ;
    PORT
      LAYER M5 ;
        RECT  34.992 69.036 35.016 69.12 ;
    END
  END cfg_data[64]
  PIN cfg_data[65]
    DIRECTION INPUT ;
    USE SIGNAL ;
    PORT
      LAYER M5 ;
        RECT  35.088 69.036 35.112 69.12 ;
    END
  END cfg_data[65]
  PIN cfg_data[66]
    DIRECTION INPUT ;
    USE SIGNAL ;
    PORT
      LAYER M5 ;
        RECT  35.184 69.036 35.208 69.12 ;
    END
  END cfg_data[66]
  PIN cfg_data[67]
    DIRECTION INPUT ;
    USE SIGNAL ;
    PORT
      LAYER M5 ;
        RECT  35.28 69.036 35.304 69.12 ;
    END
  END cfg_data[67]
  PIN cfg_data[68]
    DIRECTION INPUT ;
    USE SIGNAL ;
    PORT
      LAYER M5 ;
        RECT  35.376 69.036 35.4 69.12 ;
    END
  END cfg_data[68]
  PIN cfg_data[69]
    DIRECTION INPUT ;
    USE SIGNAL ;
    PORT
      LAYER M5 ;
        RECT  35.472 69.036 35.496 69.12 ;
    END
  END cfg_data[69]
  PIN cfg_data[6]
    DIRECTION INPUT ;
    USE SIGNAL ;
    PORT
      LAYER M5 ;
        RECT  41.712 69.036 41.736 69.12 ;
    END
  END cfg_data[6]
  PIN cfg_data[70]
    DIRECTION INPUT ;
    USE SIGNAL ;
    PORT
      LAYER M5 ;
        RECT  35.568 69.036 35.592 69.12 ;
    END
  END cfg_data[70]
  PIN cfg_data[71]
    DIRECTION INPUT ;
    USE SIGNAL ;
    PORT
      LAYER M5 ;
        RECT  35.664 69.036 35.688 69.12 ;
    END
  END cfg_data[71]
  PIN cfg_data[72]
    DIRECTION INPUT ;
    USE SIGNAL ;
    PORT
      LAYER M5 ;
        RECT  35.76 69.036 35.784 69.12 ;
    END
  END cfg_data[72]
  PIN cfg_data[73]
    DIRECTION INPUT ;
    USE SIGNAL ;
    PORT
      LAYER M5 ;
        RECT  35.856 69.036 35.88 69.12 ;
    END
  END cfg_data[73]
  PIN cfg_data[74]
    DIRECTION INPUT ;
    USE SIGNAL ;
    PORT
      LAYER M5 ;
        RECT  35.952 69.036 35.976 69.12 ;
    END
  END cfg_data[74]
  PIN cfg_data[75]
    DIRECTION INPUT ;
    USE SIGNAL ;
    PORT
      LAYER M5 ;
        RECT  36.048 69.036 36.072 69.12 ;
    END
  END cfg_data[75]
  PIN cfg_data[76]
    DIRECTION INPUT ;
    USE SIGNAL ;
    PORT
      LAYER M5 ;
        RECT  36.144 69.036 36.168 69.12 ;
    END
  END cfg_data[76]
  PIN cfg_data[77]
    DIRECTION INPUT ;
    USE SIGNAL ;
    PORT
      LAYER M5 ;
        RECT  36.24 69.036 36.264 69.12 ;
    END
  END cfg_data[77]
  PIN cfg_data[78]
    DIRECTION INPUT ;
    USE SIGNAL ;
    PORT
      LAYER M5 ;
        RECT  36.336 69.036 36.36 69.12 ;
    END
  END cfg_data[78]
  PIN cfg_data[79]
    DIRECTION INPUT ;
    USE SIGNAL ;
    PORT
      LAYER M5 ;
        RECT  36.432 69.036 36.456 69.12 ;
    END
  END cfg_data[79]
  PIN cfg_data[7]
    DIRECTION INPUT ;
    USE SIGNAL ;
    PORT
      LAYER M5 ;
        RECT  41.808 69.036 41.832 69.12 ;
    END
  END cfg_data[7]
  PIN cfg_data[80]
    DIRECTION INPUT ;
    USE SIGNAL ;
    PORT
      LAYER M5 ;
        RECT  36.528 69.036 36.552 69.12 ;
    END
  END cfg_data[80]
  PIN cfg_data[81]
    DIRECTION INPUT ;
    USE SIGNAL ;
    PORT
      LAYER M5 ;
        RECT  36.624 69.036 36.648 69.12 ;
    END
  END cfg_data[81]
  PIN cfg_data[82]
    DIRECTION INPUT ;
    USE SIGNAL ;
    PORT
      LAYER M5 ;
        RECT  36.72 69.036 36.744 69.12 ;
    END
  END cfg_data[82]
  PIN cfg_data[83]
    DIRECTION INPUT ;
    USE SIGNAL ;
    PORT
      LAYER M5 ;
        RECT  36.816 69.036 36.84 69.12 ;
    END
  END cfg_data[83]
  PIN cfg_data[84]
    DIRECTION INPUT ;
    USE SIGNAL ;
    PORT
      LAYER M5 ;
        RECT  46.128 69.036 46.152 69.12 ;
    END
  END cfg_data[84]
  PIN cfg_data[85]
    DIRECTION INPUT ;
    USE SIGNAL ;
    PORT
      LAYER M5 ;
        RECT  46.224 69.036 46.248 69.12 ;
    END
  END cfg_data[85]
  PIN cfg_data[86]
    DIRECTION INPUT ;
    USE SIGNAL ;
    PORT
      LAYER M5 ;
        RECT  46.32 69.036 46.344 69.12 ;
    END
  END cfg_data[86]
  PIN cfg_data[87]
    DIRECTION INPUT ;
    USE SIGNAL ;
    PORT
      LAYER M5 ;
        RECT  46.416 69.036 46.44 69.12 ;
    END
  END cfg_data[87]
  PIN cfg_data[88]
    DIRECTION INPUT ;
    USE SIGNAL ;
    PORT
      LAYER M5 ;
        RECT  46.512 69.036 46.536 69.12 ;
    END
  END cfg_data[88]
  PIN cfg_data[89]
    DIRECTION INPUT ;
    USE SIGNAL ;
    PORT
      LAYER M5 ;
        RECT  46.608 69.036 46.632 69.12 ;
    END
  END cfg_data[89]
  PIN cfg_data[8]
    DIRECTION INPUT ;
    USE SIGNAL ;
    PORT
      LAYER M5 ;
        RECT  41.904 69.036 41.928 69.12 ;
    END
  END cfg_data[8]
  PIN cfg_data[90]
    DIRECTION INPUT ;
    USE SIGNAL ;
    PORT
      LAYER M5 ;
        RECT  46.704 69.036 46.728 69.12 ;
    END
  END cfg_data[90]
  PIN cfg_data[91]
    DIRECTION INPUT ;
    USE SIGNAL ;
    PORT
      LAYER M5 ;
        RECT  46.8 69.036 46.824 69.12 ;
    END
  END cfg_data[91]
  PIN cfg_data[92]
    DIRECTION INPUT ;
    USE SIGNAL ;
    PORT
      LAYER M5 ;
        RECT  46.896 69.036 46.92 69.12 ;
    END
  END cfg_data[92]
  PIN cfg_data[93]
    DIRECTION INPUT ;
    USE SIGNAL ;
    PORT
      LAYER M5 ;
        RECT  46.992 69.036 47.016 69.12 ;
    END
  END cfg_data[93]
  PIN cfg_data[94]
    DIRECTION INPUT ;
    USE SIGNAL ;
    PORT
      LAYER M5 ;
        RECT  47.088 69.036 47.112 69.12 ;
    END
  END cfg_data[94]
  PIN cfg_data[95]
    DIRECTION INPUT ;
    USE SIGNAL ;
    PORT
      LAYER M5 ;
        RECT  47.184 69.036 47.208 69.12 ;
    END
  END cfg_data[95]
  PIN cfg_data[96]
    DIRECTION INPUT ;
    USE SIGNAL ;
    PORT
      LAYER M5 ;
        RECT  47.28 69.036 47.304 69.12 ;
    END
  END cfg_data[96]
  PIN cfg_data[97]
    DIRECTION INPUT ;
    USE SIGNAL ;
    PORT
      LAYER M5 ;
        RECT  47.376 69.036 47.4 69.12 ;
    END
  END cfg_data[97]
  PIN cfg_data[98]
    DIRECTION INPUT ;
    USE SIGNAL ;
    PORT
      LAYER M5 ;
        RECT  47.472 69.036 47.496 69.12 ;
    END
  END cfg_data[98]
  PIN cfg_data[99]
    DIRECTION INPUT ;
    USE SIGNAL ;
    PORT
      LAYER M5 ;
        RECT  47.568 69.036 47.592 69.12 ;
    END
  END cfg_data[99]
  PIN cfg_data[9]
    DIRECTION INPUT ;
    USE SIGNAL ;
    PORT
      LAYER M5 ;
        RECT  42 69.036 42.024 69.12 ;
    END
  END cfg_data[9]
  PIN cfg_target[0]
    DIRECTION INPUT ;
    USE SIGNAL ;
    PORT
      LAYER M5 ;
        RECT  25.008 69.036 25.032 69.12 ;
    END
  END cfg_target[0]
  PIN cfg_target[1]
    DIRECTION INPUT ;
    USE SIGNAL ;
    PORT
      LAYER M5 ;
        RECT  25.104 69.036 25.128 69.12 ;
    END
  END cfg_target[1]
  PIN cfg_target[2]
    DIRECTION INPUT ;
    USE SIGNAL ;
    PORT
      LAYER M5 ;
        RECT  25.2 69.036 25.224 69.12 ;
    END
  END cfg_target[2]
  PIN cfg_target[3]
    DIRECTION INPUT ;
    USE SIGNAL ;
    PORT
      LAYER M5 ;
        RECT  25.296 69.036 25.32 69.12 ;
    END
  END cfg_target[3]
  PIN cfg_target[4]
    DIRECTION INPUT ;
    USE SIGNAL ;
    PORT
      LAYER M5 ;
        RECT  25.392 69.036 25.416 69.12 ;
    END
  END cfg_target[4]
  PIN cfg_target[5]
    DIRECTION INPUT ;
    USE SIGNAL ;
    PORT
      LAYER M5 ;
        RECT  25.488 69.036 25.512 69.12 ;
    END
  END cfg_target[5]
  PIN cfg_target[6]
    DIRECTION INPUT ;
    USE SIGNAL ;
    PORT
      LAYER M5 ;
        RECT  25.584 69.036 25.608 69.12 ;
    END
  END cfg_target[6]
  PIN cfg_target[7]
    DIRECTION INPUT ;
    USE SIGNAL ;
    PORT
      LAYER M5 ;
        RECT  25.68 69.036 25.704 69.12 ;
    END
  END cfg_target[7]
  PIN cfg_v
    DIRECTION INPUT ;
    USE SIGNAL ;
    PORT
      LAYER M5 ;
        RECT  25.776 69.036 25.8 69.12 ;
    END
  END cfg_v
  PIN clk
    DIRECTION INPUT ;
    USE SIGNAL ;
    PORT
      LAYER M5 ;
        RECT  25.872 69.036 25.896 69.12 ;
    END
  END clk
  PIN desc_base[0]
    DIRECTION INPUT ;
    USE SIGNAL ;
    PORT
      LAYER M5 ;
        RECT  25.968 69.036 25.992 69.12 ;
    END
  END desc_base[0]
  PIN desc_base[10]
    DIRECTION INPUT ;
    USE SIGNAL ;
    PORT
      LAYER M5 ;
        RECT  20.784 69.036 20.808 69.12 ;
    END
  END desc_base[10]
  PIN desc_base[11]
    DIRECTION INPUT ;
    USE SIGNAL ;
    PORT
      LAYER M5 ;
        RECT  20.88 69.036 20.904 69.12 ;
    END
  END desc_base[11]
  PIN desc_base[1]
    DIRECTION INPUT ;
    USE SIGNAL ;
    PORT
      LAYER M5 ;
        RECT  26.064 69.036 26.088 69.12 ;
    END
  END desc_base[1]
  PIN desc_base[2]
    DIRECTION INPUT ;
    USE SIGNAL ;
    PORT
      LAYER M5 ;
        RECT  26.16 69.036 26.184 69.12 ;
    END
  END desc_base[2]
  PIN desc_base[3]
    DIRECTION INPUT ;
    USE SIGNAL ;
    PORT
      LAYER M5 ;
        RECT  26.256 69.036 26.28 69.12 ;
    END
  END desc_base[3]
  PIN desc_base[4]
    DIRECTION INPUT ;
    USE SIGNAL ;
    PORT
      LAYER M5 ;
        RECT  26.352 69.036 26.376 69.12 ;
    END
  END desc_base[4]
  PIN desc_base[5]
    DIRECTION INPUT ;
    USE SIGNAL ;
    PORT
      LAYER M5 ;
        RECT  26.448 69.036 26.472 69.12 ;
    END
  END desc_base[5]
  PIN desc_base[6]
    DIRECTION INPUT ;
    USE SIGNAL ;
    PORT
      LAYER M5 ;
        RECT  26.544 69.036 26.568 69.12 ;
    END
  END desc_base[6]
  PIN desc_base[7]
    DIRECTION INPUT ;
    USE SIGNAL ;
    PORT
      LAYER M5 ;
        RECT  26.64 69.036 26.664 69.12 ;
    END
  END desc_base[7]
  PIN desc_base[8]
    DIRECTION INPUT ;
    USE SIGNAL ;
    PORT
      LAYER M5 ;
        RECT  26.736 69.036 26.76 69.12 ;
    END
  END desc_base[8]
  PIN desc_base[9]
    DIRECTION INPUT ;
    USE SIGNAL ;
    PORT
      LAYER M5 ;
        RECT  26.832 69.036 26.856 69.12 ;
    END
  END desc_base[9]
  PIN desc_limit[0]
    DIRECTION INPUT ;
    USE SIGNAL ;
    PORT
      LAYER M5 ;
        RECT  20.976 69.036 21 69.12 ;
    END
  END desc_limit[0]
  PIN desc_limit[10]
    DIRECTION INPUT ;
    USE SIGNAL ;
    PORT
      LAYER M5 ;
        RECT  21.936 69.036 21.96 69.12 ;
    END
  END desc_limit[10]
  PIN desc_limit[11]
    DIRECTION INPUT ;
    USE SIGNAL ;
    PORT
      LAYER M5 ;
        RECT  22.032 69.036 22.056 69.12 ;
    END
  END desc_limit[11]
  PIN desc_limit[12]
    DIRECTION INPUT ;
    USE SIGNAL ;
    PORT
      LAYER M5 ;
        RECT  22.128 69.036 22.152 69.12 ;
    END
  END desc_limit[12]
  PIN desc_limit[1]
    DIRECTION INPUT ;
    USE SIGNAL ;
    PORT
      LAYER M5 ;
        RECT  21.072 69.036 21.096 69.12 ;
    END
  END desc_limit[1]
  PIN desc_limit[2]
    DIRECTION INPUT ;
    USE SIGNAL ;
    PORT
      LAYER M5 ;
        RECT  21.168 69.036 21.192 69.12 ;
    END
  END desc_limit[2]
  PIN desc_limit[3]
    DIRECTION INPUT ;
    USE SIGNAL ;
    PORT
      LAYER M5 ;
        RECT  21.264 69.036 21.288 69.12 ;
    END
  END desc_limit[3]
  PIN desc_limit[4]
    DIRECTION INPUT ;
    USE SIGNAL ;
    PORT
      LAYER M5 ;
        RECT  21.36 69.036 21.384 69.12 ;
    END
  END desc_limit[4]
  PIN desc_limit[5]
    DIRECTION INPUT ;
    USE SIGNAL ;
    PORT
      LAYER M5 ;
        RECT  21.456 69.036 21.48 69.12 ;
    END
  END desc_limit[5]
  PIN desc_limit[6]
    DIRECTION INPUT ;
    USE SIGNAL ;
    PORT
      LAYER M5 ;
        RECT  21.552 69.036 21.576 69.12 ;
    END
  END desc_limit[6]
  PIN desc_limit[7]
    DIRECTION INPUT ;
    USE SIGNAL ;
    PORT
      LAYER M5 ;
        RECT  21.648 69.036 21.672 69.12 ;
    END
  END desc_limit[7]
  PIN desc_limit[8]
    DIRECTION INPUT ;
    USE SIGNAL ;
    PORT
      LAYER M5 ;
        RECT  21.744 69.036 21.768 69.12 ;
    END
  END desc_limit[8]
  PIN desc_limit[9]
    DIRECTION INPUT ;
    USE SIGNAL ;
    PORT
      LAYER M5 ;
        RECT  21.84 69.036 21.864 69.12 ;
    END
  END desc_limit[9]
  PIN desc_loops[0]
    DIRECTION INPUT ;
    USE SIGNAL ;
    PORT
      LAYER M5 ;
        RECT  22.224 69.036 22.248 69.12 ;
    END
  END desc_loops[0]
  PIN desc_loops[10]
    DIRECTION INPUT ;
    USE SIGNAL ;
    PORT
      LAYER M5 ;
        RECT  23.184 69.036 23.208 69.12 ;
    END
  END desc_loops[10]
  PIN desc_loops[11]
    DIRECTION INPUT ;
    USE SIGNAL ;
    PORT
      LAYER M5 ;
        RECT  23.28 69.036 23.304 69.12 ;
    END
  END desc_loops[11]
  PIN desc_loops[12]
    DIRECTION INPUT ;
    USE SIGNAL ;
    PORT
      LAYER M5 ;
        RECT  23.376 69.036 23.4 69.12 ;
    END
  END desc_loops[12]
  PIN desc_loops[13]
    DIRECTION INPUT ;
    USE SIGNAL ;
    PORT
      LAYER M5 ;
        RECT  23.472 69.036 23.496 69.12 ;
    END
  END desc_loops[13]
  PIN desc_loops[14]
    DIRECTION INPUT ;
    USE SIGNAL ;
    PORT
      LAYER M5 ;
        RECT  23.568 69.036 23.592 69.12 ;
    END
  END desc_loops[14]
  PIN desc_loops[15]
    DIRECTION INPUT ;
    USE SIGNAL ;
    PORT
      LAYER M5 ;
        RECT  23.664 69.036 23.688 69.12 ;
    END
  END desc_loops[15]
  PIN desc_loops[1]
    DIRECTION INPUT ;
    USE SIGNAL ;
    PORT
      LAYER M5 ;
        RECT  22.32 69.036 22.344 69.12 ;
    END
  END desc_loops[1]
  PIN desc_loops[2]
    DIRECTION INPUT ;
    USE SIGNAL ;
    PORT
      LAYER M5 ;
        RECT  22.416 69.036 22.44 69.12 ;
    END
  END desc_loops[2]
  PIN desc_loops[3]
    DIRECTION INPUT ;
    USE SIGNAL ;
    PORT
      LAYER M5 ;
        RECT  22.512 69.036 22.536 69.12 ;
    END
  END desc_loops[3]
  PIN desc_loops[4]
    DIRECTION INPUT ;
    USE SIGNAL ;
    PORT
      LAYER M5 ;
        RECT  22.608 69.036 22.632 69.12 ;
    END
  END desc_loops[4]
  PIN desc_loops[5]
    DIRECTION INPUT ;
    USE SIGNAL ;
    PORT
      LAYER M5 ;
        RECT  22.704 69.036 22.728 69.12 ;
    END
  END desc_loops[5]
  PIN desc_loops[6]
    DIRECTION INPUT ;
    USE SIGNAL ;
    PORT
      LAYER M5 ;
        RECT  22.8 69.036 22.824 69.12 ;
    END
  END desc_loops[6]
  PIN desc_loops[7]
    DIRECTION INPUT ;
    USE SIGNAL ;
    PORT
      LAYER M5 ;
        RECT  22.896 69.036 22.92 69.12 ;
    END
  END desc_loops[7]
  PIN desc_loops[8]
    DIRECTION INPUT ;
    USE SIGNAL ;
    PORT
      LAYER M5 ;
        RECT  22.992 69.036 23.016 69.12 ;
    END
  END desc_loops[8]
  PIN desc_loops[9]
    DIRECTION INPUT ;
    USE SIGNAL ;
    PORT
      LAYER M5 ;
        RECT  23.088 69.036 23.112 69.12 ;
    END
  END desc_loops[9]
  PIN desc_v
    DIRECTION INPUT ;
    USE SIGNAL ;
    PORT
      LAYER M5 ;
        RECT  23.76 69.036 23.784 69.12 ;
    END
  END desc_v
  PIN launch_v
    DIRECTION INPUT ;
    USE SIGNAL ;
    PORT
      LAYER M5 ;
        RECT  30.576 69.036 30.6 69.12 ;
    END
  END launch_v
  PIN rst_n
    DIRECTION INPUT ;
    USE SIGNAL ;
    PORT
      LAYER M5 ;
        RECT  30.672 69.036 30.696 69.12 ;
    END
  END rst_n
  PIN s_active[0]
    DIRECTION OUTPUT ;
    USE SIGNAL ;
    PORT
      LAYER M5 ;
        RECT  42.192 0 42.216 0.084 ;
    END
  END s_active[0]
  PIN s_active[10]
    DIRECTION OUTPUT ;
    USE SIGNAL ;
    PORT
      LAYER M5 ;
        RECT  43.152 0 43.176 0.084 ;
    END
  END s_active[10]
  PIN s_active[11]
    DIRECTION OUTPUT ;
    USE SIGNAL ;
    PORT
      LAYER M5 ;
        RECT  43.248 0 43.272 0.084 ;
    END
  END s_active[11]
  PIN s_active[12]
    DIRECTION OUTPUT ;
    USE SIGNAL ;
    PORT
      LAYER M5 ;
        RECT  43.344 0 43.368 0.084 ;
    END
  END s_active[12]
  PIN s_active[13]
    DIRECTION OUTPUT ;
    USE SIGNAL ;
    PORT
      LAYER M5 ;
        RECT  43.44 0 43.464 0.084 ;
    END
  END s_active[13]
  PIN s_active[14]
    DIRECTION OUTPUT ;
    USE SIGNAL ;
    PORT
      LAYER M5 ;
        RECT  43.536 0 43.56 0.084 ;
    END
  END s_active[14]
  PIN s_active[15]
    DIRECTION OUTPUT ;
    USE SIGNAL ;
    PORT
      LAYER M5 ;
        RECT  43.632 0 43.656 0.084 ;
    END
  END s_active[15]
  PIN s_active[16]
    DIRECTION OUTPUT ;
    USE SIGNAL ;
    PORT
      LAYER M5 ;
        RECT  43.728 0 43.752 0.084 ;
    END
  END s_active[16]
  PIN s_active[17]
    DIRECTION OUTPUT ;
    USE SIGNAL ;
    PORT
      LAYER M5 ;
        RECT  43.824 0 43.848 0.084 ;
    END
  END s_active[17]
  PIN s_active[18]
    DIRECTION OUTPUT ;
    USE SIGNAL ;
    PORT
      LAYER M5 ;
        RECT  43.92 0 43.944 0.084 ;
    END
  END s_active[18]
  PIN s_active[19]
    DIRECTION OUTPUT ;
    USE SIGNAL ;
    PORT
      LAYER M5 ;
        RECT  44.016 0 44.04 0.084 ;
    END
  END s_active[19]
  PIN s_active[1]
    DIRECTION OUTPUT ;
    USE SIGNAL ;
    PORT
      LAYER M5 ;
        RECT  42.288 0 42.312 0.084 ;
    END
  END s_active[1]
  PIN s_active[20]
    DIRECTION OUTPUT ;
    USE SIGNAL ;
    PORT
      LAYER M5 ;
        RECT  44.112 0 44.136 0.084 ;
    END
  END s_active[20]
  PIN s_active[2]
    DIRECTION OUTPUT ;
    USE SIGNAL ;
    PORT
      LAYER M5 ;
        RECT  42.384 0 42.408 0.084 ;
    END
  END s_active[2]
  PIN s_active[3]
    DIRECTION OUTPUT ;
    USE SIGNAL ;
    PORT
      LAYER M5 ;
        RECT  42.48 0 42.504 0.084 ;
    END
  END s_active[3]
  PIN s_active[4]
    DIRECTION OUTPUT ;
    USE SIGNAL ;
    PORT
      LAYER M5 ;
        RECT  42.576 0 42.6 0.084 ;
    END
  END s_active[4]
  PIN s_active[5]
    DIRECTION OUTPUT ;
    USE SIGNAL ;
    PORT
      LAYER M5 ;
        RECT  42.672 0 42.696 0.084 ;
    END
  END s_active[5]
  PIN s_active[6]
    DIRECTION OUTPUT ;
    USE SIGNAL ;
    PORT
      LAYER M5 ;
        RECT  42.768 0 42.792 0.084 ;
    END
  END s_active[6]
  PIN s_active[7]
    DIRECTION OUTPUT ;
    USE SIGNAL ;
    PORT
      LAYER M5 ;
        RECT  42.864 0 42.888 0.084 ;
    END
  END s_active[7]
  PIN s_active[8]
    DIRECTION OUTPUT ;
    USE SIGNAL ;
    PORT
      LAYER M5 ;
        RECT  42.96 0 42.984 0.084 ;
    END
  END s_active[8]
  PIN s_active[9]
    DIRECTION OUTPUT ;
    USE SIGNAL ;
    PORT
      LAYER M5 ;
        RECT  43.056 0 43.08 0.084 ;
    END
  END s_active[9]
  PIN s_fault[0]
    DIRECTION OUTPUT ;
    USE SIGNAL ;
    PORT
      LAYER M5 ;
        RECT  44.208 0 44.232 0.084 ;
    END
  END s_fault[0]
  PIN s_fault[10]
    DIRECTION OUTPUT ;
    USE SIGNAL ;
    PORT
      LAYER M5 ;
        RECT  45.168 0 45.192 0.084 ;
    END
  END s_fault[10]
  PIN s_fault[11]
    DIRECTION OUTPUT ;
    USE SIGNAL ;
    PORT
      LAYER M5 ;
        RECT  39.12 0 39.144 0.084 ;
    END
  END s_fault[11]
  PIN s_fault[12]
    DIRECTION OUTPUT ;
    USE SIGNAL ;
    PORT
      LAYER M5 ;
        RECT  39.216 0 39.24 0.084 ;
    END
  END s_fault[12]
  PIN s_fault[13]
    DIRECTION OUTPUT ;
    USE SIGNAL ;
    PORT
      LAYER M5 ;
        RECT  39.312 0 39.336 0.084 ;
    END
  END s_fault[13]
  PIN s_fault[14]
    DIRECTION OUTPUT ;
    USE SIGNAL ;
    PORT
      LAYER M5 ;
        RECT  39.408 0 39.432 0.084 ;
    END
  END s_fault[14]
  PIN s_fault[15]
    DIRECTION OUTPUT ;
    USE SIGNAL ;
    PORT
      LAYER M5 ;
        RECT  39.504 0 39.528 0.084 ;
    END
  END s_fault[15]
  PIN s_fault[16]
    DIRECTION OUTPUT ;
    USE SIGNAL ;
    PORT
      LAYER M5 ;
        RECT  39.6 0 39.624 0.084 ;
    END
  END s_fault[16]
  PIN s_fault[17]
    DIRECTION OUTPUT ;
    USE SIGNAL ;
    PORT
      LAYER M5 ;
        RECT  39.696 0 39.72 0.084 ;
    END
  END s_fault[17]
  PIN s_fault[18]
    DIRECTION OUTPUT ;
    USE SIGNAL ;
    PORT
      LAYER M5 ;
        RECT  39.792 0 39.816 0.084 ;
    END
  END s_fault[18]
  PIN s_fault[19]
    DIRECTION OUTPUT ;
    USE SIGNAL ;
    PORT
      LAYER M5 ;
        RECT  39.888 0 39.912 0.084 ;
    END
  END s_fault[19]
  PIN s_fault[1]
    DIRECTION OUTPUT ;
    USE SIGNAL ;
    PORT
      LAYER M5 ;
        RECT  44.304 0 44.328 0.084 ;
    END
  END s_fault[1]
  PIN s_fault[20]
    DIRECTION OUTPUT ;
    USE SIGNAL ;
    PORT
      LAYER M5 ;
        RECT  39.984 0 40.008 0.084 ;
    END
  END s_fault[20]
  PIN s_fault[21]
    DIRECTION OUTPUT ;
    USE SIGNAL ;
    PORT
      LAYER M5 ;
        RECT  40.08 0 40.104 0.084 ;
    END
  END s_fault[21]
  PIN s_fault[22]
    DIRECTION OUTPUT ;
    USE SIGNAL ;
    PORT
      LAYER M5 ;
        RECT  40.176 0 40.2 0.084 ;
    END
  END s_fault[22]
  PIN s_fault[23]
    DIRECTION OUTPUT ;
    USE SIGNAL ;
    PORT
      LAYER M5 ;
        RECT  40.272 0 40.296 0.084 ;
    END
  END s_fault[23]
  PIN s_fault[24]
    DIRECTION OUTPUT ;
    USE SIGNAL ;
    PORT
      LAYER M5 ;
        RECT  40.368 0 40.392 0.084 ;
    END
  END s_fault[24]
  PIN s_fault[25]
    DIRECTION OUTPUT ;
    USE SIGNAL ;
    PORT
      LAYER M5 ;
        RECT  40.464 0 40.488 0.084 ;
    END
  END s_fault[25]
  PIN s_fault[26]
    DIRECTION OUTPUT ;
    USE SIGNAL ;
    PORT
      LAYER M5 ;
        RECT  40.56 0 40.584 0.084 ;
    END
  END s_fault[26]
  PIN s_fault[27]
    DIRECTION OUTPUT ;
    USE SIGNAL ;
    PORT
      LAYER M5 ;
        RECT  40.656 0 40.68 0.084 ;
    END
  END s_fault[27]
  PIN s_fault[28]
    DIRECTION OUTPUT ;
    USE SIGNAL ;
    PORT
      LAYER M5 ;
        RECT  40.752 0 40.776 0.084 ;
    END
  END s_fault[28]
  PIN s_fault[29]
    DIRECTION OUTPUT ;
    USE SIGNAL ;
    PORT
      LAYER M5 ;
        RECT  40.848 0 40.872 0.084 ;
    END
  END s_fault[29]
  PIN s_fault[2]
    DIRECTION OUTPUT ;
    USE SIGNAL ;
    PORT
      LAYER M5 ;
        RECT  44.4 0 44.424 0.084 ;
    END
  END s_fault[2]
  PIN s_fault[3]
    DIRECTION OUTPUT ;
    USE SIGNAL ;
    PORT
      LAYER M5 ;
        RECT  44.496 0 44.52 0.084 ;
    END
  END s_fault[3]
  PIN s_fault[4]
    DIRECTION OUTPUT ;
    USE SIGNAL ;
    PORT
      LAYER M5 ;
        RECT  44.592 0 44.616 0.084 ;
    END
  END s_fault[4]
  PIN s_fault[5]
    DIRECTION OUTPUT ;
    USE SIGNAL ;
    PORT
      LAYER M5 ;
        RECT  44.688 0 44.712 0.084 ;
    END
  END s_fault[5]
  PIN s_fault[6]
    DIRECTION OUTPUT ;
    USE SIGNAL ;
    PORT
      LAYER M5 ;
        RECT  44.784 0 44.808 0.084 ;
    END
  END s_fault[6]
  PIN s_fault[7]
    DIRECTION OUTPUT ;
    USE SIGNAL ;
    PORT
      LAYER M5 ;
        RECT  44.88 0 44.904 0.084 ;
    END
  END s_fault[7]
  PIN s_fault[8]
    DIRECTION OUTPUT ;
    USE SIGNAL ;
    PORT
      LAYER M5 ;
        RECT  44.976 0 45 0.084 ;
    END
  END s_fault[8]
  PIN s_fault[9]
    DIRECTION OUTPUT ;
    USE SIGNAL ;
    PORT
      LAYER M5 ;
        RECT  45.072 0 45.096 0.084 ;
    END
  END s_fault[9]
  PIN s_ready[0]
    DIRECTION OUTPUT ;
    USE SIGNAL ;
    PORT
      LAYER M5 ;
        RECT  40.944 0 40.968 0.084 ;
    END
  END s_ready[0]
  PIN s_ready[10]
    DIRECTION OUTPUT ;
    USE SIGNAL ;
    PORT
      LAYER M5 ;
        RECT  41.904 0 41.928 0.084 ;
    END
  END s_ready[10]
  PIN s_ready[11]
    DIRECTION OUTPUT ;
    USE SIGNAL ;
    PORT
      LAYER M5 ;
        RECT  42 0 42.024 0.084 ;
    END
  END s_ready[11]
  PIN s_ready[12]
    DIRECTION OUTPUT ;
    USE SIGNAL ;
    PORT
      LAYER M5 ;
        RECT  42.096 0 42.12 0.084 ;
    END
  END s_ready[12]
  PIN s_ready[13]
    DIRECTION OUTPUT ;
    USE SIGNAL ;
    PORT
      LAYER M5 ;
        RECT  32.208 0 32.232 0.084 ;
    END
  END s_ready[13]
  PIN s_ready[14]
    DIRECTION OUTPUT ;
    USE SIGNAL ;
    PORT
      LAYER M5 ;
        RECT  32.304 0 32.328 0.084 ;
    END
  END s_ready[14]
  PIN s_ready[15]
    DIRECTION OUTPUT ;
    USE SIGNAL ;
    PORT
      LAYER M5 ;
        RECT  32.4 0 32.424 0.084 ;
    END
  END s_ready[15]
  PIN s_ready[16]
    DIRECTION OUTPUT ;
    USE SIGNAL ;
    PORT
      LAYER M5 ;
        RECT  32.496 0 32.52 0.084 ;
    END
  END s_ready[16]
  PIN s_ready[17]
    DIRECTION OUTPUT ;
    USE SIGNAL ;
    PORT
      LAYER M5 ;
        RECT  32.592 0 32.616 0.084 ;
    END
  END s_ready[17]
  PIN s_ready[18]
    DIRECTION OUTPUT ;
    USE SIGNAL ;
    PORT
      LAYER M5 ;
        RECT  32.688 0 32.712 0.084 ;
    END
  END s_ready[18]
  PIN s_ready[19]
    DIRECTION OUTPUT ;
    USE SIGNAL ;
    PORT
      LAYER M5 ;
        RECT  32.784 0 32.808 0.084 ;
    END
  END s_ready[19]
  PIN s_ready[1]
    DIRECTION OUTPUT ;
    USE SIGNAL ;
    PORT
      LAYER M5 ;
        RECT  41.04 0 41.064 0.084 ;
    END
  END s_ready[1]
  PIN s_ready[20]
    DIRECTION OUTPUT ;
    USE SIGNAL ;
    PORT
      LAYER M5 ;
        RECT  32.88 0 32.904 0.084 ;
    END
  END s_ready[20]
  PIN s_ready[2]
    DIRECTION OUTPUT ;
    USE SIGNAL ;
    PORT
      LAYER M5 ;
        RECT  41.136 0 41.16 0.084 ;
    END
  END s_ready[2]
  PIN s_ready[3]
    DIRECTION OUTPUT ;
    USE SIGNAL ;
    PORT
      LAYER M5 ;
        RECT  41.232 0 41.256 0.084 ;
    END
  END s_ready[3]
  PIN s_ready[4]
    DIRECTION OUTPUT ;
    USE SIGNAL ;
    PORT
      LAYER M5 ;
        RECT  41.328 0 41.352 0.084 ;
    END
  END s_ready[4]
  PIN s_ready[5]
    DIRECTION OUTPUT ;
    USE SIGNAL ;
    PORT
      LAYER M5 ;
        RECT  41.424 0 41.448 0.084 ;
    END
  END s_ready[5]
  PIN s_ready[6]
    DIRECTION OUTPUT ;
    USE SIGNAL ;
    PORT
      LAYER M5 ;
        RECT  41.52 0 41.544 0.084 ;
    END
  END s_ready[6]
  PIN s_ready[7]
    DIRECTION OUTPUT ;
    USE SIGNAL ;
    PORT
      LAYER M5 ;
        RECT  41.616 0 41.64 0.084 ;
    END
  END s_ready[7]
  PIN s_ready[8]
    DIRECTION OUTPUT ;
    USE SIGNAL ;
    PORT
      LAYER M5 ;
        RECT  41.712 0 41.736 0.084 ;
    END
  END s_ready[8]
  PIN s_ready[9]
    DIRECTION OUTPUT ;
    USE SIGNAL ;
    PORT
      LAYER M5 ;
        RECT  41.808 0 41.832 0.084 ;
    END
  END s_ready[9]
  PIN t_active[0]
    DIRECTION INPUT ;
    USE SIGNAL ;
    PORT
      LAYER M5 ;
        RECT  32.976 0 33 0.084 ;
    END
  END t_active[0]
  PIN t_active[10]
    DIRECTION INPUT ;
    USE SIGNAL ;
    PORT
      LAYER M5 ;
        RECT  33.936 0 33.96 0.084 ;
    END
  END t_active[10]
  PIN t_active[11]
    DIRECTION INPUT ;
    USE SIGNAL ;
    PORT
      LAYER M5 ;
        RECT  34.032 0 34.056 0.084 ;
    END
  END t_active[11]
  PIN t_active[12]
    DIRECTION INPUT ;
    USE SIGNAL ;
    PORT
      LAYER M5 ;
        RECT  34.128 0 34.152 0.084 ;
    END
  END t_active[12]
  PIN t_active[13]
    DIRECTION INPUT ;
    USE SIGNAL ;
    PORT
      LAYER M5 ;
        RECT  34.224 0 34.248 0.084 ;
    END
  END t_active[13]
  PIN t_active[14]
    DIRECTION INPUT ;
    USE SIGNAL ;
    PORT
      LAYER M5 ;
        RECT  34.32 0 34.344 0.084 ;
    END
  END t_active[14]
  PIN t_active[15]
    DIRECTION INPUT ;
    USE SIGNAL ;
    PORT
      LAYER M5 ;
        RECT  34.416 0 34.44 0.084 ;
    END
  END t_active[15]
  PIN t_active[16]
    DIRECTION INPUT ;
    USE SIGNAL ;
    PORT
      LAYER M5 ;
        RECT  34.512 0 34.536 0.084 ;
    END
  END t_active[16]
  PIN t_active[17]
    DIRECTION INPUT ;
    USE SIGNAL ;
    PORT
      LAYER M5 ;
        RECT  34.608 0 34.632 0.084 ;
    END
  END t_active[17]
  PIN t_active[18]
    DIRECTION INPUT ;
    USE SIGNAL ;
    PORT
      LAYER M5 ;
        RECT  34.704 0 34.728 0.084 ;
    END
  END t_active[18]
  PIN t_active[19]
    DIRECTION INPUT ;
    USE SIGNAL ;
    PORT
      LAYER M5 ;
        RECT  34.8 0 34.824 0.084 ;
    END
  END t_active[19]
  PIN t_active[1]
    DIRECTION INPUT ;
    USE SIGNAL ;
    PORT
      LAYER M5 ;
        RECT  33.072 0 33.096 0.084 ;
    END
  END t_active[1]
  PIN t_active[20]
    DIRECTION INPUT ;
    USE SIGNAL ;
    PORT
      LAYER M5 ;
        RECT  34.896 0 34.92 0.084 ;
    END
  END t_active[20]
  PIN t_active[2]
    DIRECTION INPUT ;
    USE SIGNAL ;
    PORT
      LAYER M5 ;
        RECT  33.168 0 33.192 0.084 ;
    END
  END t_active[2]
  PIN t_active[3]
    DIRECTION INPUT ;
    USE SIGNAL ;
    PORT
      LAYER M5 ;
        RECT  33.264 0 33.288 0.084 ;
    END
  END t_active[3]
  PIN t_active[4]
    DIRECTION INPUT ;
    USE SIGNAL ;
    PORT
      LAYER M5 ;
        RECT  33.36 0 33.384 0.084 ;
    END
  END t_active[4]
  PIN t_active[5]
    DIRECTION INPUT ;
    USE SIGNAL ;
    PORT
      LAYER M5 ;
        RECT  33.456 0 33.48 0.084 ;
    END
  END t_active[5]
  PIN t_active[6]
    DIRECTION INPUT ;
    USE SIGNAL ;
    PORT
      LAYER M5 ;
        RECT  33.552 0 33.576 0.084 ;
    END
  END t_active[6]
  PIN t_active[7]
    DIRECTION INPUT ;
    USE SIGNAL ;
    PORT
      LAYER M5 ;
        RECT  33.648 0 33.672 0.084 ;
    END
  END t_active[7]
  PIN t_active[8]
    DIRECTION INPUT ;
    USE SIGNAL ;
    PORT
      LAYER M5 ;
        RECT  33.744 0 33.768 0.084 ;
    END
  END t_active[8]
  PIN t_active[9]
    DIRECTION INPUT ;
    USE SIGNAL ;
    PORT
      LAYER M5 ;
        RECT  33.84 0 33.864 0.084 ;
    END
  END t_active[9]
  PIN t_fault[0]
    DIRECTION INPUT ;
    USE SIGNAL ;
    PORT
      LAYER M5 ;
        RECT  34.992 0 35.016 0.084 ;
    END
  END t_fault[0]
  PIN t_fault[10]
    DIRECTION INPUT ;
    USE SIGNAL ;
    PORT
      LAYER M5 ;
        RECT  35.952 0 35.976 0.084 ;
    END
  END t_fault[10]
  PIN t_fault[11]
    DIRECTION INPUT ;
    USE SIGNAL ;
    PORT
      LAYER M5 ;
        RECT  36.048 0 36.072 0.084 ;
    END
  END t_fault[11]
  PIN t_fault[12]
    DIRECTION INPUT ;
    USE SIGNAL ;
    PORT
      LAYER M5 ;
        RECT  36.144 0 36.168 0.084 ;
    END
  END t_fault[12]
  PIN t_fault[13]
    DIRECTION INPUT ;
    USE SIGNAL ;
    PORT
      LAYER M5 ;
        RECT  36.24 0 36.264 0.084 ;
    END
  END t_fault[13]
  PIN t_fault[14]
    DIRECTION INPUT ;
    USE SIGNAL ;
    PORT
      LAYER M5 ;
        RECT  36.336 0 36.36 0.084 ;
    END
  END t_fault[14]
  PIN t_fault[15]
    DIRECTION INPUT ;
    USE SIGNAL ;
    PORT
      LAYER M5 ;
        RECT  36.432 0 36.456 0.084 ;
    END
  END t_fault[15]
  PIN t_fault[16]
    DIRECTION INPUT ;
    USE SIGNAL ;
    PORT
      LAYER M5 ;
        RECT  36.528 0 36.552 0.084 ;
    END
  END t_fault[16]
  PIN t_fault[17]
    DIRECTION INPUT ;
    USE SIGNAL ;
    PORT
      LAYER M5 ;
        RECT  36.624 0 36.648 0.084 ;
    END
  END t_fault[17]
  PIN t_fault[18]
    DIRECTION INPUT ;
    USE SIGNAL ;
    PORT
      LAYER M5 ;
        RECT  36.72 0 36.744 0.084 ;
    END
  END t_fault[18]
  PIN t_fault[19]
    DIRECTION INPUT ;
    USE SIGNAL ;
    PORT
      LAYER M5 ;
        RECT  36.816 0 36.84 0.084 ;
    END
  END t_fault[19]
  PIN t_fault[1]
    DIRECTION INPUT ;
    USE SIGNAL ;
    PORT
      LAYER M5 ;
        RECT  35.088 0 35.112 0.084 ;
    END
  END t_fault[1]
  PIN t_fault[20]
    DIRECTION INPUT ;
    USE SIGNAL ;
    PORT
      LAYER M5 ;
        RECT  36.912 0 36.936 0.084 ;
    END
  END t_fault[20]
  PIN t_fault[21]
    DIRECTION INPUT ;
    USE SIGNAL ;
    PORT
      LAYER M5 ;
        RECT  37.008 0 37.032 0.084 ;
    END
  END t_fault[21]
  PIN t_fault[22]
    DIRECTION INPUT ;
    USE SIGNAL ;
    PORT
      LAYER M5 ;
        RECT  37.104 0 37.128 0.084 ;
    END
  END t_fault[22]
  PIN t_fault[23]
    DIRECTION INPUT ;
    USE SIGNAL ;
    PORT
      LAYER M5 ;
        RECT  37.2 0 37.224 0.084 ;
    END
  END t_fault[23]
  PIN t_fault[24]
    DIRECTION INPUT ;
    USE SIGNAL ;
    PORT
      LAYER M5 ;
        RECT  37.296 0 37.32 0.084 ;
    END
  END t_fault[24]
  PIN t_fault[25]
    DIRECTION INPUT ;
    USE SIGNAL ;
    PORT
      LAYER M5 ;
        RECT  37.392 0 37.416 0.084 ;
    END
  END t_fault[25]
  PIN t_fault[26]
    DIRECTION INPUT ;
    USE SIGNAL ;
    PORT
      LAYER M5 ;
        RECT  37.488 0 37.512 0.084 ;
    END
  END t_fault[26]
  PIN t_fault[27]
    DIRECTION INPUT ;
    USE SIGNAL ;
    PORT
      LAYER M5 ;
        RECT  37.584 0 37.608 0.084 ;
    END
  END t_fault[27]
  PIN t_fault[28]
    DIRECTION INPUT ;
    USE SIGNAL ;
    PORT
      LAYER M5 ;
        RECT  37.68 0 37.704 0.084 ;
    END
  END t_fault[28]
  PIN t_fault[29]
    DIRECTION INPUT ;
    USE SIGNAL ;
    PORT
      LAYER M5 ;
        RECT  37.776 0 37.8 0.084 ;
    END
  END t_fault[29]
  PIN t_fault[2]
    DIRECTION INPUT ;
    USE SIGNAL ;
    PORT
      LAYER M5 ;
        RECT  35.184 0 35.208 0.084 ;
    END
  END t_fault[2]
  PIN t_fault[3]
    DIRECTION INPUT ;
    USE SIGNAL ;
    PORT
      LAYER M5 ;
        RECT  35.28 0 35.304 0.084 ;
    END
  END t_fault[3]
  PIN t_fault[4]
    DIRECTION INPUT ;
    USE SIGNAL ;
    PORT
      LAYER M5 ;
        RECT  35.376 0 35.4 0.084 ;
    END
  END t_fault[4]
  PIN t_fault[5]
    DIRECTION INPUT ;
    USE SIGNAL ;
    PORT
      LAYER M5 ;
        RECT  35.472 0 35.496 0.084 ;
    END
  END t_fault[5]
  PIN t_fault[6]
    DIRECTION INPUT ;
    USE SIGNAL ;
    PORT
      LAYER M5 ;
        RECT  35.568 0 35.592 0.084 ;
    END
  END t_fault[6]
  PIN t_fault[7]
    DIRECTION INPUT ;
    USE SIGNAL ;
    PORT
      LAYER M5 ;
        RECT  35.664 0 35.688 0.084 ;
    END
  END t_fault[7]
  PIN t_fault[8]
    DIRECTION INPUT ;
    USE SIGNAL ;
    PORT
      LAYER M5 ;
        RECT  35.76 0 35.784 0.084 ;
    END
  END t_fault[8]
  PIN t_fault[9]
    DIRECTION INPUT ;
    USE SIGNAL ;
    PORT
      LAYER M5 ;
        RECT  35.856 0 35.88 0.084 ;
    END
  END t_fault[9]
  PIN t_ready[0]
    DIRECTION INPUT ;
    USE SIGNAL ;
    PORT
      LAYER M5 ;
        RECT  37.872 0 37.896 0.084 ;
    END
  END t_ready[0]
  PIN t_ready[10]
    DIRECTION INPUT ;
    USE SIGNAL ;
    PORT
      LAYER M5 ;
        RECT  29.616 0 29.64 0.084 ;
    END
  END t_ready[10]
  PIN t_ready[11]
    DIRECTION INPUT ;
    USE SIGNAL ;
    PORT
      LAYER M5 ;
        RECT  29.712 0 29.736 0.084 ;
    END
  END t_ready[11]
  PIN t_ready[12]
    DIRECTION INPUT ;
    USE SIGNAL ;
    PORT
      LAYER M5 ;
        RECT  29.808 0 29.832 0.084 ;
    END
  END t_ready[12]
  PIN t_ready[13]
    DIRECTION INPUT ;
    USE SIGNAL ;
    PORT
      LAYER M5 ;
        RECT  29.904 0 29.928 0.084 ;
    END
  END t_ready[13]
  PIN t_ready[14]
    DIRECTION INPUT ;
    USE SIGNAL ;
    PORT
      LAYER M5 ;
        RECT  30 0 30.024 0.084 ;
    END
  END t_ready[14]
  PIN t_ready[15]
    DIRECTION INPUT ;
    USE SIGNAL ;
    PORT
      LAYER M5 ;
        RECT  30.096 0 30.12 0.084 ;
    END
  END t_ready[15]
  PIN t_ready[16]
    DIRECTION INPUT ;
    USE SIGNAL ;
    PORT
      LAYER M5 ;
        RECT  30.192 0 30.216 0.084 ;
    END
  END t_ready[16]
  PIN t_ready[17]
    DIRECTION INPUT ;
    USE SIGNAL ;
    PORT
      LAYER M5 ;
        RECT  30.288 0 30.312 0.084 ;
    END
  END t_ready[17]
  PIN t_ready[18]
    DIRECTION INPUT ;
    USE SIGNAL ;
    PORT
      LAYER M5 ;
        RECT  30.384 0 30.408 0.084 ;
    END
  END t_ready[18]
  PIN t_ready[19]
    DIRECTION INPUT ;
    USE SIGNAL ;
    PORT
      LAYER M5 ;
        RECT  30.48 0 30.504 0.084 ;
    END
  END t_ready[19]
  PIN t_ready[1]
    DIRECTION INPUT ;
    USE SIGNAL ;
    PORT
      LAYER M5 ;
        RECT  37.968 0 37.992 0.084 ;
    END
  END t_ready[1]
  PIN t_ready[20]
    DIRECTION INPUT ;
    USE SIGNAL ;
    PORT
      LAYER M5 ;
        RECT  30.576 0 30.6 0.084 ;
    END
  END t_ready[20]
  PIN t_ready[2]
    DIRECTION INPUT ;
    USE SIGNAL ;
    PORT
      LAYER M5 ;
        RECT  38.064 0 38.088 0.084 ;
    END
  END t_ready[2]
  PIN t_ready[3]
    DIRECTION INPUT ;
    USE SIGNAL ;
    PORT
      LAYER M5 ;
        RECT  38.16 0 38.184 0.084 ;
    END
  END t_ready[3]
  PIN t_ready[4]
    DIRECTION INPUT ;
    USE SIGNAL ;
    PORT
      LAYER M5 ;
        RECT  38.256 0 38.28 0.084 ;
    END
  END t_ready[4]
  PIN t_ready[5]
    DIRECTION INPUT ;
    USE SIGNAL ;
    PORT
      LAYER M5 ;
        RECT  29.136 0 29.16 0.084 ;
    END
  END t_ready[5]
  PIN t_ready[6]
    DIRECTION INPUT ;
    USE SIGNAL ;
    PORT
      LAYER M5 ;
        RECT  29.232 0 29.256 0.084 ;
    END
  END t_ready[6]
  PIN t_ready[7]
    DIRECTION INPUT ;
    USE SIGNAL ;
    PORT
      LAYER M5 ;
        RECT  29.328 0 29.352 0.084 ;
    END
  END t_ready[7]
  PIN t_ready[8]
    DIRECTION INPUT ;
    USE SIGNAL ;
    PORT
      LAYER M5 ;
        RECT  29.424 0 29.448 0.084 ;
    END
  END t_ready[8]
  PIN t_ready[9]
    DIRECTION INPUT ;
    USE SIGNAL ;
    PORT
      LAYER M5 ;
        RECT  29.52 0 29.544 0.084 ;
    END
  END t_ready[9]
  PIN VDD
    DIRECTION INOUT ;
    USE POWER ;
    PORT
      LAYER M5 ;
        RECT  61.992 2.151 62.112 66.969 ;
        RECT  56.592 2.151 56.712 66.969 ;
        RECT  51.192 2.151 51.312 66.969 ;
        RECT  45.792 2.151 45.912 66.969 ;
        RECT  40.392 2.151 40.512 66.969 ;
        RECT  34.992 2.151 35.112 66.969 ;
        RECT  29.592 2.151 29.712 66.969 ;
        RECT  24.192 2.151 24.312 66.969 ;
        RECT  18.792 2.151 18.912 66.969 ;
        RECT  13.392 2.151 13.512 66.969 ;
        RECT  7.992 2.151 8.112 66.969 ;
        RECT  2.592 2.151 2.712 66.969 ;
    END
  END VDD
  PIN VSS
    DIRECTION INOUT ;
    USE GROUND ;
    PORT
      LAYER M5 ;
        RECT  61.8 2.137 61.92 66.983 ;
        RECT  56.4 2.137 56.52 66.983 ;
        RECT  51 2.137 51.12 66.983 ;
        RECT  45.6 2.137 45.72 66.983 ;
        RECT  40.2 2.137 40.32 66.983 ;
        RECT  34.8 2.137 34.92 66.983 ;
        RECT  29.4 2.137 29.52 66.983 ;
        RECT  24 2.137 24.12 66.983 ;
        RECT  18.6 2.137 18.72 66.983 ;
        RECT  13.2 2.137 13.32 66.983 ;
        RECT  7.8 2.137 7.92 66.983 ;
        RECT  2.4 2.137 2.52 66.983 ;
    END
  END VSS
  OBS
    LAYER RVTN ;
     RECT  2.16 2.16 66.96 2.295 ;
     RECT  2.16 2.565 66.96 2.835 ;
     RECT  2.16 3.105 66.96 3.375 ;
     RECT  2.16 3.645 66.96 3.915 ;
     RECT  2.16 4.185 66.96 4.455 ;
     RECT  2.16 4.725 66.96 4.995 ;
     RECT  2.16 5.265 66.96 5.535 ;
     RECT  2.16 5.805 66.96 6.075 ;
     RECT  2.16 6.345 66.96 6.615 ;
     RECT  2.16 6.885 66.96 7.155 ;
     RECT  2.16 7.425 66.96 7.695 ;
     RECT  2.16 7.965 66.96 8.235 ;
     RECT  2.16 8.505 66.96 8.775 ;
     RECT  2.16 9.045 66.96 9.315 ;
     RECT  2.16 9.585 66.96 9.855 ;
     RECT  2.16 10.125 66.96 10.395 ;
     RECT  2.16 10.665 66.96 10.935 ;
     RECT  2.16 11.205 66.96 11.475 ;
     RECT  2.16 11.745 66.96 12.015 ;
     RECT  2.16 12.285 66.96 12.555 ;
     RECT  2.16 12.825 66.96 13.095 ;
     RECT  2.16 13.365 66.96 13.635 ;
     RECT  2.16 13.905 66.96 14.175 ;
     RECT  2.16 14.445 66.96 14.715 ;
     RECT  2.16 14.985 66.96 15.255 ;
     RECT  2.16 15.525 66.96 15.795 ;
     RECT  2.16 16.065 66.96 16.335 ;
     RECT  2.16 16.605 66.96 16.875 ;
     RECT  2.16 17.145 66.96 17.415 ;
     RECT  2.16 17.685 66.96 17.955 ;
     RECT  2.16 18.225 66.96 18.495 ;
     RECT  2.16 18.765 66.96 19.035 ;
     RECT  2.16 19.305 66.96 19.575 ;
     RECT  2.16 19.845 66.96 20.115 ;
     RECT  2.16 20.385 66.96 20.655 ;
     RECT  2.16 20.925 66.96 21.195 ;
     RECT  2.16 21.465 66.96 21.735 ;
     RECT  2.16 22.005 66.96 22.275 ;
     RECT  2.16 22.545 66.96 22.815 ;
     RECT  2.16 23.085 66.96 23.355 ;
     RECT  2.16 23.625 66.96 23.895 ;
     RECT  2.16 24.165 66.96 24.435 ;
     RECT  2.16 24.705 66.96 24.975 ;
     RECT  2.16 25.245 66.96 25.515 ;
     RECT  2.16 25.785 66.96 26.055 ;
     RECT  2.16 26.325 66.96 26.595 ;
     RECT  2.16 26.865 66.96 27.135 ;
     RECT  2.16 27.405 66.96 27.675 ;
     RECT  2.16 27.945 66.96 28.215 ;
     RECT  2.16 28.485 66.96 28.755 ;
     RECT  2.16 29.025 66.96 29.295 ;
     RECT  2.16 29.565 66.96 29.835 ;
     RECT  2.16 30.105 66.96 30.375 ;
     RECT  2.16 30.645 66.96 30.915 ;
     RECT  2.16 31.185 66.96 31.455 ;
     RECT  2.16 31.725 66.96 31.995 ;
     RECT  2.16 32.265 66.96 32.535 ;
     RECT  2.16 32.805 66.96 33.075 ;
     RECT  2.16 33.345 66.96 33.615 ;
     RECT  2.16 33.885 66.96 34.155 ;
     RECT  2.16 34.425 66.96 34.695 ;
     RECT  2.16 34.965 66.96 35.235 ;
     RECT  2.16 35.505 66.96 35.775 ;
     RECT  2.16 36.045 66.96 36.315 ;
     RECT  2.16 36.585 66.96 36.855 ;
     RECT  2.16 37.125 66.96 37.395 ;
     RECT  2.16 37.665 66.96 37.935 ;
     RECT  2.16 38.205 66.96 38.475 ;
     RECT  2.16 38.745 66.96 39.015 ;
     RECT  2.16 39.285 66.96 39.555 ;
     RECT  2.16 39.825 66.96 40.095 ;
     RECT  2.16 40.365 66.96 40.635 ;
     RECT  2.16 40.905 66.96 41.175 ;
     RECT  2.16 41.445 66.96 41.715 ;
     RECT  2.16 41.985 66.96 42.255 ;
     RECT  2.16 42.525 66.96 42.795 ;
     RECT  2.16 43.065 66.96 43.335 ;
     RECT  2.16 43.605 66.96 43.875 ;
     RECT  2.16 44.145 66.96 44.415 ;
     RECT  2.16 44.685 66.96 44.955 ;
     RECT  2.16 45.225 66.96 45.495 ;
     RECT  2.16 45.765 66.96 46.035 ;
     RECT  2.16 46.305 66.96 46.575 ;
     RECT  2.16 46.845 66.96 47.115 ;
     RECT  2.16 47.385 66.96 47.655 ;
     RECT  2.16 47.925 66.96 48.195 ;
     RECT  2.16 48.465 66.96 48.735 ;
     RECT  2.16 49.005 66.96 49.275 ;
     RECT  2.16 49.545 66.96 49.815 ;
     RECT  2.16 50.085 66.96 50.355 ;
     RECT  2.16 50.625 66.96 50.895 ;
     RECT  2.16 51.165 66.96 51.435 ;
     RECT  2.16 51.705 66.96 51.975 ;
     RECT  2.16 52.245 66.96 52.515 ;
     RECT  2.16 52.785 66.96 53.055 ;
     RECT  2.16 53.325 66.96 53.595 ;
     RECT  2.16 53.865 66.96 54.135 ;
     RECT  2.16 54.405 66.96 54.675 ;
     RECT  2.16 54.945 66.96 55.215 ;
     RECT  2.16 55.485 66.96 55.755 ;
     RECT  2.16 56.025 66.96 56.295 ;
     RECT  2.16 56.565 66.96 56.835 ;
     RECT  2.16 57.105 66.96 57.375 ;
     RECT  2.16 57.645 66.96 57.915 ;
     RECT  2.16 58.185 66.96 58.455 ;
     RECT  2.16 58.725 66.96 58.995 ;
     RECT  2.16 59.265 66.96 59.535 ;
     RECT  2.16 59.805 66.96 60.075 ;
     RECT  2.16 60.345 66.96 60.615 ;
     RECT  2.16 60.885 66.96 61.155 ;
     RECT  2.16 61.425 66.96 61.695 ;
     RECT  2.16 61.965 66.96 62.235 ;
     RECT  2.16 62.505 66.96 62.775 ;
     RECT  2.16 63.045 66.96 63.315 ;
     RECT  2.16 63.585 66.96 63.855 ;
     RECT  2.16 64.125 66.96 64.395 ;
     RECT  2.16 64.665 66.96 64.935 ;
     RECT  2.16 65.205 66.96 65.475 ;
     RECT  2.16 65.745 66.96 66.015 ;
     RECT  2.16 66.285 66.96 66.555 ;
     RECT  2.16 66.825 66.96 66.96 ;
    LAYER RVTP ;
     RECT  2.16 2.295 66.96 2.565 ;
     RECT  2.16 2.835 66.96 3.105 ;
     RECT  2.16 3.375 66.96 3.645 ;
     RECT  2.16 3.915 66.96 4.185 ;
     RECT  2.16 4.455 66.96 4.725 ;
     RECT  2.16 4.995 66.96 5.265 ;
     RECT  2.16 5.535 66.96 5.805 ;
     RECT  2.16 6.075 66.96 6.345 ;
     RECT  2.16 6.615 66.96 6.885 ;
     RECT  2.16 7.155 66.96 7.425 ;
     RECT  2.16 7.695 66.96 7.965 ;
     RECT  2.16 8.235 66.96 8.505 ;
     RECT  2.16 8.775 66.96 9.045 ;
     RECT  2.16 9.315 66.96 9.585 ;
     RECT  2.16 9.855 66.96 10.125 ;
     RECT  2.16 10.395 66.96 10.665 ;
     RECT  2.16 10.935 66.96 11.205 ;
     RECT  2.16 11.475 66.96 11.745 ;
     RECT  2.16 12.015 66.96 12.285 ;
     RECT  2.16 12.555 66.96 12.825 ;
     RECT  2.16 13.095 66.96 13.365 ;
     RECT  2.16 13.635 66.96 13.905 ;
     RECT  2.16 14.175 66.96 14.445 ;
     RECT  2.16 14.715 66.96 14.985 ;
     RECT  2.16 15.255 66.96 15.525 ;
     RECT  2.16 15.795 66.96 16.065 ;
     RECT  2.16 16.335 66.96 16.605 ;
     RECT  2.16 16.875 66.96 17.145 ;
     RECT  2.16 17.415 66.96 17.685 ;
     RECT  2.16 17.955 66.96 18.225 ;
     RECT  2.16 18.495 66.96 18.765 ;
     RECT  2.16 19.035 66.96 19.305 ;
     RECT  2.16 19.575 66.96 19.845 ;
     RECT  2.16 20.115 66.96 20.385 ;
     RECT  2.16 20.655 66.96 20.925 ;
     RECT  2.16 21.195 66.96 21.465 ;
     RECT  2.16 21.735 66.96 22.005 ;
     RECT  2.16 22.275 66.96 22.545 ;
     RECT  2.16 22.815 66.96 23.085 ;
     RECT  2.16 23.355 66.96 23.625 ;
     RECT  2.16 23.895 66.96 24.165 ;
     RECT  2.16 24.435 66.96 24.705 ;
     RECT  2.16 24.975 66.96 25.245 ;
     RECT  2.16 25.515 66.96 25.785 ;
     RECT  2.16 26.055 66.96 26.325 ;
     RECT  2.16 26.595 66.96 26.865 ;
     RECT  2.16 27.135 66.96 27.405 ;
     RECT  2.16 27.675 66.96 27.945 ;
     RECT  2.16 28.215 66.96 28.485 ;
     RECT  2.16 28.755 66.96 29.025 ;
     RECT  2.16 29.295 66.96 29.565 ;
     RECT  2.16 29.835 66.96 30.105 ;
     RECT  2.16 30.375 66.96 30.645 ;
     RECT  2.16 30.915 66.96 31.185 ;
     RECT  2.16 31.455 66.96 31.725 ;
     RECT  2.16 31.995 66.96 32.265 ;
     RECT  2.16 32.535 66.96 32.805 ;
     RECT  2.16 33.075 66.96 33.345 ;
     RECT  2.16 33.615 66.96 33.885 ;
     RECT  2.16 34.155 66.96 34.425 ;
     RECT  2.16 34.695 66.96 34.965 ;
     RECT  2.16 35.235 66.96 35.505 ;
     RECT  2.16 35.775 66.96 36.045 ;
     RECT  2.16 36.315 66.96 36.585 ;
     RECT  2.16 36.855 66.96 37.125 ;
     RECT  2.16 37.395 66.96 37.665 ;
     RECT  2.16 37.935 66.96 38.205 ;
     RECT  2.16 38.475 66.96 38.745 ;
     RECT  2.16 39.015 66.96 39.285 ;
     RECT  2.16 39.555 66.96 39.825 ;
     RECT  2.16 40.095 66.96 40.365 ;
     RECT  2.16 40.635 66.96 40.905 ;
     RECT  2.16 41.175 66.96 41.445 ;
     RECT  2.16 41.715 66.96 41.985 ;
     RECT  2.16 42.255 66.96 42.525 ;
     RECT  2.16 42.795 66.96 43.065 ;
     RECT  2.16 43.335 66.96 43.605 ;
     RECT  2.16 43.875 66.96 44.145 ;
     RECT  2.16 44.415 66.96 44.685 ;
     RECT  2.16 44.955 66.96 45.225 ;
     RECT  2.16 45.495 66.96 45.765 ;
     RECT  2.16 46.035 66.96 46.305 ;
     RECT  2.16 46.575 66.96 46.845 ;
     RECT  2.16 47.115 66.96 47.385 ;
     RECT  2.16 47.655 66.96 47.925 ;
     RECT  2.16 48.195 66.96 48.465 ;
     RECT  2.16 48.735 66.96 49.005 ;
     RECT  2.16 49.275 66.96 49.545 ;
     RECT  2.16 49.815 66.96 50.085 ;
     RECT  2.16 50.355 66.96 50.625 ;
     RECT  2.16 50.895 66.96 51.165 ;
     RECT  2.16 51.435 66.96 51.705 ;
     RECT  2.16 51.975 66.96 52.245 ;
     RECT  2.16 52.515 66.96 52.785 ;
     RECT  2.16 53.055 66.96 53.325 ;
     RECT  2.16 53.595 66.96 53.865 ;
     RECT  2.16 54.135 66.96 54.405 ;
     RECT  2.16 54.675 66.96 54.945 ;
     RECT  2.16 55.215 66.96 55.485 ;
     RECT  2.16 55.755 66.96 56.025 ;
     RECT  2.16 56.295 66.96 56.565 ;
     RECT  2.16 56.835 66.96 57.105 ;
     RECT  2.16 57.375 66.96 57.645 ;
     RECT  2.16 57.915 66.96 58.185 ;
     RECT  2.16 58.455 66.96 58.725 ;
     RECT  2.16 58.995 66.96 59.265 ;
     RECT  2.16 59.535 66.96 59.805 ;
     RECT  2.16 60.075 66.96 60.345 ;
     RECT  2.16 60.615 66.96 60.885 ;
     RECT  2.16 61.155 66.96 61.425 ;
     RECT  2.16 61.695 66.96 61.965 ;
     RECT  2.16 62.235 66.96 62.505 ;
     RECT  2.16 62.775 66.96 63.045 ;
     RECT  2.16 63.315 66.96 63.585 ;
     RECT  2.16 63.855 66.96 64.125 ;
     RECT  2.16 64.395 66.96 64.665 ;
     RECT  2.16 64.935 66.96 65.205 ;
     RECT  2.16 65.475 66.96 65.745 ;
     RECT  2.16 66.015 66.96 66.285 ;
     RECT  2.16 66.555 66.96 66.825 ;
    LAYER M1 ;
     RECT  2.16 2.151 66.96 66.969 ;
    LAYER M2 ;
     RECT  0.103 44.856 0.139 44.874 ;
     RECT  0.103 20.898 0.203 21.15 ;
     RECT  0.103 24.174 0.203 24.192 ;
     RECT  0.103 27.261 0.203 27.279 ;
     RECT  0.103 28.26 0.203 28.278 ;
     RECT  0.103 34.092 0.203 34.416 ;
     RECT  0.103 35.712 0.203 35.73 ;
     RECT  0.103 38.412 0.203 38.43 ;
     RECT  0.103 41.22 0.203 42.714 ;
     RECT  0.139 44.496 0.203 44.874 ;
     RECT  0.103 48.366 0.203 49.104 ;
     RECT  0.103 19.548 0.239 19.566 ;
     RECT  0.203 44.496 0.239 44.514 ;
     RECT  0.319 39.096 0.419 39.114 ;
     RECT  0.103 22.176 0.535 22.194 ;
     RECT  0.103 31.356 0.535 31.374 ;
     RECT  0.203 42.696 0.535 42.714 ;
     RECT  0.535 17.586 2.16 17.604 ;
     RECT  0.535 18.774 2.16 18.792 ;
     RECT  0.535 22.176 2.16 22.5 ;
     RECT  0.535 26.766 2.16 26.784 ;
     RECT  0.535 27.846 2.16 27.864 ;
     RECT  0.535 29.61 2.16 29.628 ;
     RECT  0.535 31.356 2.16 32.292 ;
     RECT  0.535 37.566 2.16 37.584 ;
     RECT  0.535 42.696 2.16 43.326 ;
     RECT  0.535 46.116 2.16 46.134 ;
     RECT  2.16 2.151 29.911 66.969 ;
     RECT  29.911 2.106 32.071 66.969 ;
     RECT  32.071 2.106 32.251 67.014 ;
     RECT  32.251 2.07 32.603 67.014 ;
     RECT  32.603 2.106 33.431 66.969 ;
     RECT  33.431 2.151 34.195 66.969 ;
     RECT  34.195 2.106 34.375 66.969 ;
     RECT  34.375 2.07 34.951 66.969 ;
     RECT  34.951 2.034 37.435 66.969 ;
     RECT  37.435 1.881 38.515 66.969 ;
     RECT  38.515 1.836 39.415 66.969 ;
     RECT  39.415 1.152 39.703 66.969 ;
     RECT  39.703 1.152 40.163 67.014 ;
     RECT  40.163 1.836 40.775 67.014 ;
     RECT  40.775 1.836 40.991 66.969 ;
     RECT  40.991 1.962 43.871 66.969 ;
     RECT  43.871 2.151 45.247 66.969 ;
     RECT  45.247 2.106 46.399 66.969 ;
     RECT  46.399 2.07 47.651 66.969 ;
     RECT  47.651 2.106 47.831 66.969 ;
     RECT  47.831 2.151 66.96 66.969 ;
     RECT  66.96 19.746 67.811 51.534 ;
     RECT  67.811 23.976 67.847 51.534 ;
     RECT  67.847 23.976 67.883 27.864 ;
     RECT  67.847 43.686 67.883 49.374 ;
     RECT  67.847 28.692 68.351 33.138 ;
     RECT  67.811 19.746 68.387 23.004 ;
     RECT  67.883 23.976 68.387 27.234 ;
     RECT  68.351 28.836 68.387 30.132 ;
     RECT  68.351 30.996 68.387 33.138 ;
     RECT  67.847 34.434 68.387 38.43 ;
     RECT  67.883 43.776 68.387 49.374 ;
     RECT  67.847 50.364 68.387 51.534 ;
     RECT  68.387 19.746 68.423 21.15 ;
     RECT  68.387 22.014 68.423 22.644 ;
     RECT  68.387 23.976 68.423 25.308 ;
     RECT  68.387 33.12 68.423 33.138 ;
     RECT  68.387 34.434 68.423 34.794 ;
     RECT  68.387 35.586 68.423 38.43 ;
     RECT  67.847 39.33 68.423 42.822 ;
     RECT  68.387 45.468 68.423 49.374 ;
     RECT  68.387 50.364 68.423 51.426 ;
     RECT  68.423 24.948 68.459 25.308 ;
     RECT  68.423 45.468 68.459 46.53 ;
     RECT  68.387 43.92 68.495 44.442 ;
     RECT  68.387 28.998 68.999 30.132 ;
     RECT  68.423 34.704 68.999 34.794 ;
     RECT  68.423 38.286 68.999 38.43 ;
     RECT  68.423 40.104 68.999 42.624 ;
     RECT  68.495 44.19 68.999 44.442 ;
     RECT  68.459 45.846 68.999 46.53 ;
     RECT  68.423 47.862 68.999 49.374 ;
     RECT  68.423 20.466 69.035 21.15 ;
     RECT  68.423 22.212 69.035 22.23 ;
     RECT  68.423 23.976 69.035 23.994 ;
     RECT  68.459 25.29 69.035 25.308 ;
     RECT  68.387 26.334 69.035 27.126 ;
     RECT  68.999 29.034 69.035 30.132 ;
     RECT  68.387 30.996 69.035 32.292 ;
     RECT  68.999 34.704 69.035 34.722 ;
     RECT  68.423 35.586 69.035 36.072 ;
     RECT  68.999 38.286 69.035 38.304 ;
     RECT  68.423 39.33 69.035 39.348 ;
     RECT  68.999 40.104 69.035 41.976 ;
     RECT  68.999 44.424 69.035 44.442 ;
     RECT  68.999 45.846 69.035 46.404 ;
     RECT  68.999 47.862 69.035 47.88 ;
     RECT  68.999 48.708 69.035 49.374 ;
     RECT  68.423 50.598 69.035 51.426 ;
    LAYER M3 ;
     RECT  31.86 0.091 31.878 0.139 ;
     RECT  37.26 0.091 37.278 0.221 ;
     RECT  35.244 0.091 35.262 0.413 ;
     RECT  31.86 0.139 32.022 0.523 ;
     RECT  32.976 0.475 32.994 0.523 ;
     RECT  39.492 0.091 39.51 0.523 ;
     RECT  30.24 0.571 30.258 1.147 ;
     RECT  34.848 0.523 34.866 1.147 ;
     RECT  39.492 0.523 40.086 1.147 ;
     RECT  37.548 1.147 37.566 1.325 ;
     RECT  29.016 1.099 29.034 1.675 ;
     RECT  28.98 1.675 29.034 1.723 ;
     RECT  29.772 1.147 30.258 1.723 ;
     RECT  31.86 0.523 33.462 1.723 ;
     RECT  34.776 1.147 34.866 1.723 ;
     RECT  41.688 1.627 41.706 1.723 ;
     RECT  28.98 1.723 30.582 1.771 ;
     RECT  39.384 1.147 40.158 1.771 ;
     RECT  46.008 1.723 46.026 1.771 ;
     RECT  46.872 0.811 46.89 1.771 ;
     RECT  39.384 1.771 40.842 1.831 ;
     RECT  41.688 1.723 41.742 1.831 ;
     RECT  43.38 0.571 43.398 1.957 ;
     RECT  46.008 1.771 46.89 1.963 ;
     RECT  45.504 1.963 46.89 2.011 ;
     RECT  38.52 1.831 38.538 2.029 ;
     RECT  39.384 1.831 41.742 2.029 ;
     RECT  42.48 0.571 42.498 2.029 ;
     RECT  31.86 1.723 35.262 2.101 ;
     RECT  38.52 2.029 42.498 2.101 ;
     RECT  47.628 2.065 47.646 2.101 ;
     RECT  38.304 2.101 42.498 2.107 ;
     RECT  43.38 1.957 43.866 2.107 ;
     RECT  31.86 2.101 35.406 2.191 ;
     RECT  38.304 2.107 43.866 2.191 ;
     RECT  36.936 1.723 37.494 2.227 ;
     RECT  38.304 2.191 43.974 2.227 ;
     RECT  31.86 2.191 36.162 2.251 ;
     RECT  45 2.011 46.89 2.251 ;
     RECT  47.628 2.101 47.826 2.251 ;
     RECT  36.936 2.227 43.974 2.293 ;
     RECT  45 2.251 47.826 2.293 ;
     RECT  28.98 1.771 30.69 2.299 ;
     RECT  31.86 2.251 36.198 2.299 ;
     RECT  36.936 2.293 47.826 2.299 ;
     RECT  28.98 2.299 30.942 2.335 ;
     RECT  31.86 2.299 47.826 2.335 ;
     RECT  2.415 2.143 2.505 2.413 ;
     RECT  7.815 2.143 7.905 2.413 ;
     RECT  13.215 2.143 13.305 2.413 ;
     RECT  18.615 2.143 18.705 2.413 ;
     RECT  24.015 2.143 24.105 2.413 ;
     RECT  51.015 2.143 51.105 2.413 ;
     RECT  56.415 2.143 56.505 2.413 ;
     RECT  61.815 2.143 61.905 2.413 ;
     RECT  28.98 2.335 47.826 2.587 ;
     RECT  28.98 2.587 48.006 3.029 ;
     RECT  28.98 3.029 47.61 3.875 ;
     RECT  29.088 3.875 47.61 4.145 ;
     RECT  29.34 4.145 47.61 5.341 ;
     RECT  28.656 5.341 47.61 5.495 ;
     RECT  28.656 5.495 46.746 5.603 ;
     RECT  28.656 5.603 28.674 5.693 ;
     RECT  29.415 5.603 46.746 6.143 ;
     RECT  30.456 6.143 46.746 6.539 ;
     RECT  47.592 5.495 47.61 6.809 ;
     RECT  30.456 6.539 46.422 6.845 ;
     RECT  30.456 6.845 46.206 6.941 ;
     RECT  30.456 6.941 45.897 7.151 ;
     RECT  31.608 7.151 45.897 7.349 ;
     RECT  31.608 7.349 31.842 7.421 ;
     RECT  32.616 7.349 45.897 7.655 ;
     RECT  33.264 7.655 45.897 7.799 ;
     RECT  33.768 7.799 45.897 7.889 ;
     RECT  30.456 7.151 30.798 7.925 ;
     RECT  33.768 7.889 44.55 7.925 ;
     RECT  33.768 7.925 44.478 7.961 ;
     RECT  33.768 7.961 33.786 7.997 ;
     RECT  34.815 7.961 44.478 8.303 ;
     RECT  34.815 8.303 35.874 8.429 ;
     RECT  34.815 8.429 35.766 8.435 ;
     RECT  36.684 8.303 44.478 8.465 ;
     RECT  36.684 8.465 37.17 8.501 ;
     RECT  36.684 8.501 36.81 8.573 ;
     RECT  38.052 8.465 44.478 8.843 ;
     RECT  38.664 8.843 44.478 8.851 ;
     RECT  36.72 8.573 36.81 8.969 ;
     RECT  38.664 8.851 44.622 8.969 ;
     RECT  39.456 8.969 42.498 9.005 ;
     RECT  43.416 8.969 44.082 9.005 ;
     RECT  38.664 8.969 38.682 9.077 ;
     RECT  39.888 9.005 42.498 9.077 ;
     RECT  40.215 9.077 42.498 9.275 ;
     RECT  41.76 9.275 42.498 9.347 ;
     RECT  40.215 9.275 40.95 9.419 ;
     RECT  41.832 9.347 42.498 9.419 ;
     RECT  36.792 8.969 36.81 9.509 ;
     RECT  42.48 9.419 42.498 10.355 ;
     RECT  4.356 17.419 4.374 17.491 ;
     RECT  3.816 17.491 4.554 17.581 ;
     RECT  5.4 17.419 5.418 17.581 ;
     RECT  6.156 17.491 6.174 17.581 ;
     RECT  7.056 17.491 7.074 17.581 ;
     RECT  3.816 17.581 6.174 17.645 ;
     RECT  4.356 17.645 6.174 17.689 ;
     RECT  6.912 17.581 7.074 17.689 ;
     RECT  7.815 2.413 8.097 17.689 ;
     RECT  24.015 2.413 24.297 17.725 ;
     RECT  0.54 17.581 0.558 17.741 ;
     RECT  2.415 2.413 2.697 17.761 ;
     RECT  24.015 17.725 24.534 17.761 ;
     RECT  25.38 17.491 25.398 17.761 ;
     RECT  4.356 17.689 8.097 17.887 ;
     RECT  24.015 17.761 25.398 17.959 ;
     RECT  22.86 17.887 22.878 17.987 ;
     RECT  4.356 17.887 8.478 18.031 ;
     RECT  24.015 17.959 25.434 18.031 ;
     RECT  3.528 17.851 3.546 18.121 ;
     RECT  24.015 18.031 25.614 18.121 ;
     RECT  10.8 17.689 10.818 18.149 ;
     RECT  22.824 18.031 22.842 18.149 ;
     RECT  2.304 17.761 2.697 18.187 ;
     RECT  3.456 18.121 3.546 18.187 ;
     RECT  24.015 18.121 25.794 18.265 ;
     RECT  2.304 18.187 3.546 18.283 ;
     RECT  24.015 18.265 25.938 18.301 ;
     RECT  2.268 18.283 3.546 18.329 ;
     RECT  4.356 18.031 9.09 18.391 ;
     RECT  0.144 18.235 0.234 18.413 ;
     RECT  4.356 18.391 9.126 18.523 ;
     RECT  2.304 18.329 3.546 18.571 ;
     RECT  4.32 18.523 9.126 18.571 ;
     RECT  0.216 18.413 0.234 18.605 ;
     RECT  2.304 18.571 9.126 18.697 ;
     RECT  24.015 18.301 25.974 18.805 ;
     RECT  0.54 18.769 0.558 18.989 ;
     RECT  2.304 18.697 9.27 19.067 ;
     RECT  2.376 19.067 9.27 19.229 ;
     RECT  9.144 19.229 9.27 19.243 ;
     RECT  24.015 18.805 26.226 19.309 ;
     RECT  9.144 19.243 9.414 19.337 ;
     RECT  13.215 2.413 13.497 19.471 ;
     RECT  61.815 2.413 62.097 19.471 ;
     RECT  23.112 19.471 23.13 19.483 ;
     RECT  28.08 18.841 28.098 19.507 ;
     RECT  13.104 19.471 13.497 19.517 ;
     RECT  0.324 19.435 0.342 19.531 ;
     RECT  24.015 19.309 26.514 19.543 ;
     RECT  27.396 19.507 28.098 19.543 ;
     RECT  0.108 19.531 0.342 19.565 ;
     RECT  0.108 19.565 0.234 19.571 ;
     RECT  10.836 19.471 10.854 19.571 ;
     RECT  0.216 19.571 0.234 19.613 ;
     RECT  22.824 19.483 23.13 19.613 ;
     RECT  48.42 19.531 48.438 19.643 ;
     RECT  23.112 19.613 23.13 19.805 ;
     RECT  50.112 19.651 50.13 19.805 ;
     RECT  48.564 19.771 48.582 19.811 ;
     RECT  10.764 19.651 10.782 19.841 ;
     RECT  29.415 6.143 29.697 19.849 ;
     RECT  21.42 19.777 21.438 19.901 ;
     RECT  2.376 19.229 8.19 19.912 ;
     RECT  68.4 19.741 68.418 19.915 ;
     RECT  61.815 19.471 62.73 19.921 ;
     RECT  64.728 19.543 64.746 19.921 ;
     RECT  65.52 19.651 65.538 19.921 ;
     RECT  9.144 19.337 9.162 20.011 ;
     RECT  61.815 19.921 63.414 20.011 ;
     RECT  9 20.011 9.162 20.059 ;
     RECT  2.304 19.912 8.19 20.083 ;
     RECT  8.964 20.059 9.162 20.083 ;
     RECT  24.015 19.543 28.386 20.083 ;
     RECT  29.34 19.849 29.697 20.083 ;
     RECT  67.788 19.915 68.418 20.107 ;
     RECT  61.272 20.011 63.522 20.155 ;
     RECT  64.44 19.921 65.538 20.155 ;
     RECT  64.44 20.155 65.826 20.191 ;
     RECT  67.752 20.107 68.418 20.203 ;
     RECT  2.304 20.083 9.162 20.299 ;
     RECT  2.268 20.299 9.162 20.353 ;
     RECT  64.404 20.191 65.934 20.381 ;
     RECT  61.02 20.155 63.522 20.389 ;
     RECT  67.752 20.203 69.03 20.417 ;
     RECT  61.02 20.389 63.594 20.425 ;
     RECT  64.62 20.381 65.934 20.425 ;
     RECT  2.268 20.353 9.594 20.525 ;
     RECT  2.304 20.525 9.594 20.579 ;
     RECT  61.02 20.425 63.882 20.615 ;
     RECT  64.62 20.425 66.186 20.623 ;
     RECT  0.108 20.587 0.126 20.635 ;
     RECT  61.02 20.615 63.594 20.695 ;
     RECT  2.304 20.579 9.522 20.759 ;
     RECT  24.015 20.083 29.697 20.929 ;
     RECT  10.8 20.821 10.89 20.957 ;
     RECT  60.12 20.821 60.138 21.001 ;
     RECT  60.984 20.695 63.594 21.001 ;
     RECT  45.615 7.889 45.897 21.091 ;
     RECT  64.62 20.623 66.618 21.127 ;
     RECT  67.788 20.417 69.03 21.155 ;
     RECT  24.015 20.929 29.934 21.199 ;
     RECT  45.576 21.091 45.897 21.235 ;
     RECT  64.404 21.127 66.618 21.259 ;
     RECT  67.788 21.155 68.382 21.259 ;
     RECT  44.712 20.965 44.73 21.271 ;
     RECT  0.108 20.635 0.198 21.389 ;
     RECT  0.18 21.389 0.198 21.437 ;
     RECT  44.388 21.271 44.73 21.469 ;
     RECT  45.468 21.235 45.897 21.469 ;
     RECT  58.716 19.741 58.734 21.533 ;
     RECT  60.12 21.001 63.594 21.547 ;
     RECT  64.404 21.259 68.382 21.547 ;
     RECT  24.015 21.199 30.222 21.703 ;
     RECT  24.015 21.703 30.474 21.775 ;
     RECT  31.608 7.421 31.626 21.775 ;
     RECT  10.908 21.433 10.926 21.979 ;
     RECT  22.5 20.929 22.518 21.979 ;
     RECT  2.304 20.759 9.414 22.001 ;
     RECT  44.388 21.469 45.897 22.009 ;
     RECT  46.62 21.979 46.638 22.009 ;
     RECT  60.12 21.547 68.382 22.009 ;
     RECT  6.624 22.001 9.414 22.037 ;
     RECT  60.12 22.009 68.418 22.081 ;
     RECT  10.836 21.979 10.926 22.109 ;
     RECT  22.5 21.979 22.842 22.109 ;
     RECT  42.768 21.979 42.786 22.109 ;
     RECT  59.868 22.081 68.418 22.123 ;
     RECT  59.868 22.123 69.03 22.235 ;
     RECT  44.388 22.009 46.638 22.243 ;
     RECT  0.108 22.171 0.126 22.445 ;
     RECT  2.304 22.001 5.886 22.603 ;
     RECT  58.788 22.441 58.806 22.621 ;
     RECT  2.268 22.603 5.886 22.649 ;
     RECT  2.304 22.649 5.886 22.741 ;
     RECT  6.624 22.037 9.378 22.741 ;
     RECT  0.144 22.477 0.558 22.795 ;
     RECT  59.868 22.235 66.042 22.891 ;
     RECT  0.144 22.795 0.666 22.925 ;
     RECT  44.388 22.243 46.674 22.981 ;
     RECT  47.52 22.855 47.538 22.981 ;
     RECT  59.724 22.891 66.042 22.981 ;
     RECT  67.284 22.235 68.418 22.981 ;
     RECT  2.304 22.741 9.378 23.053 ;
     RECT  42.768 22.981 42.786 23.053 ;
     RECT  24.015 21.775 31.626 23.083 ;
     RECT  59.724 22.981 68.418 23.117 ;
     RECT  42.768 23.053 42.894 23.125 ;
     RECT  2.304 23.053 9.45 23.153 ;
     RECT  42.768 23.125 43.002 23.189 ;
     RECT  44.388 22.981 47.538 23.251 ;
     RECT  10.836 23.161 10.854 23.279 ;
     RECT  43.956 23.251 47.538 23.287 ;
     RECT  42.984 23.189 43.002 23.315 ;
     RECT  22.5 22.109 22.518 23.701 ;
     RECT  58.716 22.621 58.806 23.701 ;
     RECT  21.924 23.701 22.518 23.863 ;
     RECT  59.868 23.117 68.382 23.935 ;
     RECT  59.724 23.935 68.382 23.947 ;
     RECT  59.724 23.947 69.03 23.999 ;
     RECT  10.908 24.061 10.926 24.133 ;
     RECT  13.215 19.517 13.497 24.133 ;
     RECT  0.144 22.925 0.162 24.139 ;
     RECT  0.108 24.139 0.162 24.169 ;
     RECT  10.836 24.133 10.926 24.187 ;
     RECT  0.108 24.169 0.198 24.197 ;
     RECT  59.724 23.999 68.418 24.197 ;
     RECT  21.924 23.863 22.554 24.205 ;
     RECT  58.716 23.701 58.842 24.205 ;
     RECT  2.304 23.153 9.306 24.241 ;
     RECT  13.215 24.133 13.554 24.269 ;
     RECT  34.815 8.435 35.097 24.325 ;
     RECT  13.215 24.269 13.497 24.331 ;
     RECT  21.924 24.205 23.094 24.331 ;
     RECT  24.015 23.083 31.698 24.331 ;
     RECT  56.415 2.413 56.697 24.331 ;
     RECT  10.8 24.187 10.926 24.359 ;
     RECT  58.716 24.205 58.878 24.359 ;
     RECT  10.8 24.359 10.818 24.365 ;
     RECT  34.704 24.325 35.097 24.365 ;
     RECT  13.104 24.331 13.497 24.368 ;
     RECT  56.304 24.331 56.697 24.368 ;
     RECT  2.304 24.241 9.45 24.395 ;
     RECT  0.144 24.197 0.198 24.413 ;
     RECT  9 24.395 9.45 24.673 ;
     RECT  0.216 24.523 0.234 24.701 ;
     RECT  60.012 24.197 68.418 24.701 ;
     RECT  2.304 24.395 8.19 24.808 ;
     RECT  2.268 24.808 8.19 24.899 ;
     RECT  9 24.673 9.558 24.935 ;
     RECT  68.364 24.701 68.418 24.943 ;
     RECT  60.012 24.701 67.338 25.003 ;
     RECT  59.868 25.003 67.338 25.043 ;
     RECT  60.048 25.043 67.338 25.079 ;
     RECT  68.364 24.943 68.454 25.099 ;
     RECT  2.304 24.899 8.19 25.141 ;
     RECT  9 24.935 9.45 25.141 ;
     RECT  68.364 25.099 69.03 25.313 ;
     RECT  21.924 24.331 31.698 25.321 ;
     RECT  10.836 25.213 10.854 25.349 ;
     RECT  43.956 23.287 47.97 25.447 ;
     RECT  60.12 25.079 67.338 25.517 ;
     RECT  60.12 25.517 66.726 25.583 ;
     RECT  43.956 25.447 48.042 25.591 ;
     RECT  2.304 25.141 9.45 25.619 ;
     RECT  68.364 25.313 68.454 25.675 ;
     RECT  51.015 2.413 51.297 25.753 ;
     RECT  58.716 24.359 58.806 25.817 ;
     RECT  50.616 25.753 51.297 25.889 ;
     RECT  64.512 25.583 66.726 25.979 ;
     RECT  67.752 25.675 68.454 25.997 ;
     RECT  58.788 25.817 58.806 26.051 ;
     RECT  60.12 25.583 63.666 26.095 ;
     RECT  59.868 26.095 63.666 26.141 ;
     RECT  10.728 25.987 10.818 26.159 ;
     RECT  67.752 25.997 67.806 26.251 ;
     RECT  18.615 2.413 18.897 26.293 ;
     RECT  60.12 26.141 63.666 26.329 ;
     RECT  60.12 26.329 63.738 26.365 ;
     RECT  64.512 25.979 66.402 26.365 ;
     RECT  34.815 24.365 35.097 26.392 ;
     RECT  56.415 24.368 56.697 26.392 ;
     RECT  18.504 26.293 18.897 26.395 ;
     RECT  2.304 25.619 9.378 26.401 ;
     RECT  34.704 26.392 35.097 26.429 ;
     RECT  56.304 26.392 56.697 26.429 ;
     RECT  0.144 26.299 0.162 26.477 ;
     RECT  2.304 26.401 9.486 26.519 ;
     RECT  18.504 26.395 19.134 26.527 ;
     RECT  18.504 26.527 19.17 26.539 ;
     RECT  67.248 26.251 67.806 26.573 ;
     RECT  2.304 26.519 9.378 26.627 ;
     RECT  18.504 26.539 19.278 26.635 ;
     RECT  2.304 26.627 8.838 26.663 ;
     RECT  67.788 26.573 67.806 26.731 ;
     RECT  69.012 26.155 69.03 26.731 ;
     RECT  42.768 26.599 42.786 26.789 ;
     RECT  18.504 26.635 19.89 26.797 ;
     RECT  58.716 26.671 58.734 26.941 ;
     RECT  0.54 26.761 0.558 26.957 ;
     RECT  42.84 26.797 42.858 26.969 ;
     RECT  60.12 26.365 66.402 27.103 ;
     RECT  10.8 26.941 10.818 27.131 ;
     RECT  67.788 26.731 69.03 27.131 ;
     RECT  60.12 27.103 66.69 27.203 ;
     RECT  67.788 27.131 68.382 27.239 ;
     RECT  60.12 27.203 66.366 27.301 ;
     RECT  67.788 27.239 67.878 27.403 ;
     RECT  2.304 26.663 8.514 27.445 ;
     RECT  18.504 26.797 20.286 27.571 ;
     RECT  2.304 27.445 8.586 27.595 ;
     RECT  2.304 27.595 8.658 27.635 ;
     RECT  18.504 27.571 20.466 27.643 ;
     RECT  58.716 26.941 58.806 27.643 ;
     RECT  18.504 27.643 20.79 27.739 ;
     RECT  9.396 27.409 9.414 27.751 ;
     RECT  0.108 27.244 0.198 27.841 ;
     RECT  59.868 27.301 66.366 27.905 ;
     RECT  9.36 27.751 9.414 27.941 ;
     RECT  10.764 27.751 10.782 27.949 ;
     RECT  58.716 27.643 58.842 27.949 ;
     RECT  58.716 27.949 58.914 28.049 ;
     RECT  34.815 26.429 35.097 28.111 ;
     RECT  56.415 26.429 56.697 28.111 ;
     RECT  59.904 27.905 66.366 28.147 ;
     RECT  67.248 27.403 67.878 28.147 ;
     RECT  10.728 27.949 10.782 28.148 ;
     RECT  34.704 28.111 35.097 28.157 ;
     RECT  56.304 28.111 56.697 28.157 ;
     RECT  0.108 27.841 0.558 28.205 ;
     RECT  59.904 28.147 67.878 28.267 ;
     RECT  10.764 28.148 10.782 28.319 ;
     RECT  58.716 28.049 58.878 28.319 ;
     RECT  18.504 27.739 20.862 28.381 ;
     RECT  21.924 25.321 32.13 28.381 ;
     RECT  0.108 28.205 0.198 28.397 ;
     RECT  9.396 27.941 9.414 28.409 ;
     RECT  0.18 28.397 0.198 28.445 ;
     RECT  59.904 28.267 68.382 28.481 ;
     RECT  60.84 28.481 68.382 28.553 ;
     RECT  60.84 28.553 66.366 28.589 ;
     RECT  59.904 28.481 60.066 28.651 ;
     RECT  67.248 28.553 68.382 28.651 ;
     RECT  9.432 28.489 9.45 28.679 ;
     RECT  59.724 28.651 60.066 28.747 ;
     RECT  60.84 28.589 66.33 28.751 ;
     RECT  59.688 28.747 60.066 28.781 ;
     RECT  59.688 28.781 59.922 28.787 ;
     RECT  67.248 28.651 69.03 28.787 ;
     RECT  2.304 27.635 8.622 28.921 ;
     RECT  59.868 28.787 59.922 28.985 ;
     RECT  59.904 28.985 59.922 29.021 ;
     RECT  2.304 28.921 8.694 29.057 ;
     RECT  2.304 29.057 8.586 29.165 ;
     RECT  10.764 29.101 10.782 29.219 ;
     RECT  61.02 28.751 66.33 29.255 ;
     RECT  2.34 29.165 8.586 29.261 ;
     RECT  58.716 28.319 58.806 29.371 ;
     RECT  61.164 29.255 66.33 29.371 ;
     RECT  67.284 28.787 69.03 29.549 ;
     RECT  18.504 28.381 32.13 29.569 ;
     RECT  58.716 29.371 58.878 29.597 ;
     RECT  61.164 29.371 66.402 29.641 ;
     RECT  0.54 29.605 0.558 29.741 ;
     RECT  10.8 29.641 10.818 29.795 ;
     RECT  18.504 29.569 32.31 29.803 ;
     RECT  2.415 29.261 8.586 29.867 ;
     RECT  4.032 29.867 8.586 30.001 ;
     RECT  59.868 29.875 59.886 30.001 ;
     RECT  61.164 29.641 66.726 30.001 ;
     RECT  2.415 29.867 3.294 30.065 ;
     RECT  4.032 30.001 8.838 30.065 ;
     RECT  6.732 30.065 8.838 30.091 ;
     RECT  4.032 30.065 5.706 30.137 ;
     RECT  6.732 30.091 8.874 30.137 ;
     RECT  18.504 29.803 32.454 30.145 ;
     RECT  4.032 30.137 4.698 30.173 ;
     RECT  18.504 30.145 32.526 30.181 ;
     RECT  59.868 30.001 66.726 30.209 ;
     RECT  60.048 30.209 66.726 30.299 ;
     RECT  18.504 30.181 32.778 30.343 ;
     RECT  34.815 28.157 35.097 30.379 ;
     RECT  18.504 30.343 33.066 30.415 ;
     RECT  58.716 29.597 58.842 30.415 ;
     RECT  5.58 30.137 5.706 30.479 ;
     RECT  18.504 30.415 33.426 30.613 ;
     RECT  58.716 30.415 58.914 30.641 ;
     RECT  60.048 30.299 61.074 30.641 ;
     RECT  61.815 30.299 66.726 30.641 ;
     RECT  18.504 30.613 33.498 30.649 ;
     RECT  67.788 29.549 69.03 30.667 ;
     RECT  10.8 30.541 10.818 30.713 ;
     RECT  4.032 30.173 4.518 30.721 ;
     RECT  6.732 30.137 8.838 30.811 ;
     RECT  34.776 30.379 35.097 30.883 ;
     RECT  2.415 30.065 2.697 30.907 ;
     RECT  3.996 30.721 4.518 30.911 ;
     RECT  34.488 30.883 35.097 30.919 ;
     RECT  0.144 30.763 0.162 30.941 ;
     RECT  5.58 30.479 5.598 30.955 ;
     RECT  58.716 30.641 58.878 30.983 ;
     RECT  60.048 30.641 61.038 30.991 ;
     RECT  4.032 30.911 4.518 31.019 ;
     RECT  58.716 30.983 58.806 31.019 ;
     RECT  4.104 31.019 4.518 31.081 ;
     RECT  5.508 30.955 5.598 31.081 ;
     RECT  61.815 30.641 66.402 31.081 ;
     RECT  34.488 30.919 35.334 31.099 ;
     RECT  61.776 31.081 66.402 31.109 ;
     RECT  6.552 30.811 8.838 31.117 ;
     RECT  18.504 30.649 33.606 31.189 ;
     RECT  34.416 31.099 35.334 31.189 ;
     RECT  2.304 30.907 2.697 31.217 ;
     RECT  59.976 30.991 61.038 31.217 ;
     RECT  18.504 31.189 35.334 31.261 ;
     RECT  61.776 31.109 66.078 31.289 ;
     RECT  4.104 31.081 5.598 31.339 ;
     RECT  0.108 31.339 0.126 31.379 ;
     RECT  2.415 31.217 2.697 31.387 ;
     RECT  18.504 31.261 35.442 31.387 ;
     RECT  36.252 30.685 36.27 31.387 ;
     RECT  4.104 31.339 5.634 31.423 ;
     RECT  6.516 31.117 8.838 31.423 ;
     RECT  18.504 31.387 36.27 31.423 ;
     RECT  6.516 31.423 9.594 31.469 ;
     RECT  4.104 31.423 5.706 31.495 ;
     RECT  6.516 31.469 9.522 31.495 ;
     RECT  4.104 31.495 9.522 31.757 ;
     RECT  9.324 31.757 9.522 31.793 ;
     RECT  59.976 31.217 60.174 31.801 ;
     RECT  0.144 31.675 0.162 31.853 ;
     RECT  61.815 31.289 66.078 31.891 ;
     RECT  59.868 31.801 60.174 31.901 ;
     RECT  59.976 31.901 60.174 31.963 ;
     RECT  60.912 31.217 61.038 31.963 ;
     RECT  61.815 31.891 66.438 32.035 ;
     RECT  67.284 30.667 69.03 32.035 ;
     RECT  37.332 31.999 37.35 32.071 ;
     RECT  9.324 31.793 9.486 32.099 ;
     RECT  59.976 31.963 61.038 32.161 ;
     RECT  61.815 32.035 69.03 32.161 ;
     RECT  4.104 31.757 8.334 32.189 ;
     RECT  59.976 32.161 69.03 32.189 ;
     RECT  2.415 31.387 3.294 32.251 ;
     RECT  4.104 32.189 5.67 32.251 ;
     RECT  18.504 31.423 36.594 32.269 ;
     RECT  37.332 32.071 37.602 32.269 ;
     RECT  60.732 32.189 69.03 32.297 ;
     RECT  2.415 32.251 5.67 32.299 ;
     RECT  2.376 32.299 5.67 32.341 ;
     RECT  9.324 32.099 9.378 32.459 ;
     RECT  0.54 31.891 0.558 32.813 ;
     RECT  9.108 32.779 9.126 32.837 ;
     RECT  60.732 32.297 68.382 32.909 ;
     RECT  2.304 32.341 5.67 32.971 ;
     RECT  6.48 32.189 8.334 32.971 ;
     RECT  56.415 28.157 56.697 32.971 ;
     RECT  42.768 32.845 42.786 32.999 ;
     RECT  54.72 32.845 54.738 32.999 ;
     RECT  60.804 32.909 68.382 32.999 ;
     RECT  2.304 32.971 8.334 33.007 ;
     RECT  2.304 33.007 8.802 33.008 ;
     RECT  56.304 32.971 56.697 33.008 ;
     RECT  59.976 32.189 59.994 33.035 ;
     RECT  58.716 31.019 58.734 33.071 ;
     RECT  18.504 32.269 37.602 33.079 ;
     RECT  60.948 32.999 68.382 33.115 ;
     RECT  6.552 33.008 8.802 33.269 ;
     RECT  18.504 33.079 38.322 33.313 ;
     RECT  10.836 32.701 10.854 33.421 ;
     RECT  6.552 33.269 8.73 33.449 ;
     RECT  60.948 33.115 68.418 33.539 ;
     RECT  10.836 33.421 10.926 33.575 ;
     RECT  40.215 9.419 40.497 33.817 ;
     RECT  41.328 33.781 41.346 33.817 ;
     RECT  2.304 33.008 5.814 33.889 ;
     RECT  6.552 33.449 8.658 33.889 ;
     RECT  10.764 33.781 10.782 33.917 ;
     RECT  60.012 33.853 60.03 33.961 ;
     RECT  18.504 33.313 38.754 33.989 ;
     RECT  40.215 33.817 41.346 34.075 ;
     RECT  2.304 33.889 8.658 34.079 ;
     RECT  0.144 33.883 0.162 34.087 ;
     RECT  59.868 33.961 60.03 34.115 ;
     RECT  64.224 33.539 68.418 34.219 ;
     RECT  6.48 34.079 8.658 34.231 ;
     RECT  60.012 34.115 60.03 34.231 ;
     RECT  60.948 33.539 63.45 34.231 ;
     RECT  40.215 34.075 41.886 34.321 ;
     RECT  6.48 34.231 8.766 34.349 ;
     RECT  58.788 33.349 58.806 34.357 ;
     RECT  2.304 34.079 5.742 34.429 ;
     RECT  0.108 34.087 0.198 34.493 ;
     RECT  64.224 34.219 69.03 34.493 ;
     RECT  64.224 34.493 66.15 34.529 ;
     RECT  0.108 34.493 0.126 34.541 ;
     RECT  58.788 34.357 58.842 34.655 ;
     RECT  6.48 34.349 8.442 34.685 ;
     RECT  9.216 34.591 9.234 34.691 ;
     RECT  60.012 34.231 63.45 34.735 ;
     RECT  64.224 34.529 65.826 34.735 ;
     RECT  58.788 34.655 58.806 34.771 ;
     RECT  60.012 34.735 65.826 34.897 ;
     RECT  10.836 34.627 10.854 34.969 ;
     RECT  40.215 34.321 42.39 34.969 ;
     RECT  40.215 34.969 42.822 34.987 ;
     RECT  59.904 34.897 65.826 34.987 ;
     RECT  54.792 34.969 54.81 35.005 ;
     RECT  56.415 33.008 56.697 35.005 ;
     RECT  56.415 35.005 56.754 35.032 ;
     RECT  59.796 34.987 65.826 35.033 ;
     RECT  2.268 34.429 5.742 35.041 ;
     RECT  6.48 34.685 8.226 35.041 ;
     RECT  54.72 35.005 54.81 35.069 ;
     RECT  56.304 35.032 56.754 35.069 ;
     RECT  59.868 35.033 65.826 35.069 ;
     RECT  59.868 35.069 63.738 35.117 ;
     RECT  13.215 24.368 13.497 35.131 ;
     RECT  2.268 35.041 8.226 35.159 ;
     RECT  54.72 35.069 54.738 35.159 ;
     RECT  56.415 35.069 56.754 35.159 ;
     RECT  9.468 35.005 9.558 35.167 ;
     RECT  13.104 35.131 13.497 35.168 ;
     RECT  60.66 35.117 63.738 35.231 ;
     RECT  18.504 33.989 38.466 35.239 ;
     RECT  39.996 34.987 42.822 35.261 ;
     RECT  64.512 35.069 65.826 35.275 ;
     RECT  2.268 35.159 3.186 35.339 ;
     RECT  9.468 35.167 9.594 35.339 ;
     RECT  10.8 34.969 10.854 35.401 ;
     RECT  40.215 35.261 42.822 35.401 ;
     RECT  43.956 25.591 48.078 35.401 ;
     RECT  64.512 35.275 66.402 35.465 ;
     RECT  9.468 35.339 9.486 35.473 ;
     RECT  18.504 35.239 38.718 35.509 ;
     RECT  64.8 35.465 66.402 35.509 ;
     RECT  67.284 34.493 69.03 35.509 ;
     RECT  3.96 35.159 8.226 35.545 ;
     RECT  18.504 35.509 38.934 35.609 ;
     RECT  0.144 35.515 0.162 35.692 ;
     RECT  58.716 34.771 58.806 35.698 ;
     RECT  58.716 35.698 58.842 35.699 ;
     RECT  9.216 35.473 9.486 35.707 ;
     RECT  60.948 35.231 63.738 35.735 ;
     RECT  3.96 35.545 8.37 35.741 ;
     RECT  9.144 35.707 9.486 35.743 ;
     RECT  18.504 35.609 38.862 35.771 ;
     RECT  18.504 35.771 38.79 35.78 ;
     RECT  0.108 35.692 0.198 35.837 ;
     RECT  58.788 35.699 58.842 35.879 ;
     RECT  0.108 35.837 0.126 35.885 ;
     RECT  2.304 35.339 3.186 35.941 ;
     RECT  3.96 35.741 5.958 35.941 ;
     RECT  6.696 35.741 8.37 35.941 ;
     RECT  9.108 35.743 9.486 35.941 ;
     RECT  10.8 35.401 10.926 36.049 ;
     RECT  64.8 35.509 69.03 36.077 ;
     RECT  59.868 35.117 59.886 36.085 ;
     RECT  2.304 35.941 5.958 36.149 ;
     RECT  10.728 36.049 10.926 36.149 ;
     RECT  61.704 35.735 63.738 36.247 ;
     RECT  61.704 36.247 63.99 36.269 ;
     RECT  58.788 35.879 58.806 36.311 ;
     RECT  10.8 36.149 10.926 36.347 ;
     RECT  64.8 36.077 68.418 36.383 ;
     RECT  59.868 36.085 59.958 36.391 ;
     RECT  6.696 35.941 9.486 36.419 ;
     RECT  67.248 36.383 68.418 36.419 ;
     RECT  18.504 35.78 38.754 36.517 ;
     RECT  59.868 36.391 60.102 36.553 ;
     RECT  60.948 35.735 60.966 36.553 ;
     RECT  61.815 36.269 63.99 36.553 ;
     RECT  64.8 36.383 66.51 36.553 ;
     RECT  18.504 36.517 38.862 36.589 ;
     RECT  18.504 36.589 38.934 36.625 ;
     RECT  13.215 35.168 13.497 36.751 ;
     RECT  13.104 36.751 13.497 36.797 ;
     RECT  18.504 36.625 38.97 36.851 ;
     RECT  18.504 36.851 38.898 36.887 ;
     RECT  0.144 36.715 0.162 36.893 ;
     RECT  6.804 36.419 9.486 36.895 ;
     RECT  2.304 36.149 3.438 36.907 ;
     RECT  4.248 36.149 5.958 36.907 ;
     RECT  61.815 36.553 66.51 36.959 ;
     RECT  6.804 36.895 9.522 36.989 ;
     RECT  61.815 36.959 63.63 37.037 ;
     RECT  6.804 36.989 9.45 37.049 ;
     RECT  10.8 36.347 10.818 37.049 ;
     RECT  59.868 36.553 60.966 37.093 ;
     RECT  59.868 37.093 61.038 37.165 ;
     RECT  61.815 37.037 63.522 37.165 ;
     RECT  6.804 37.049 8.406 37.201 ;
     RECT  58.716 36.931 58.734 37.291 ;
     RECT  9.216 37.049 9.45 37.319 ;
     RECT  64.44 36.959 66.51 37.325 ;
     RECT  64.512 37.325 66.51 37.355 ;
     RECT  6.732 37.201 8.406 37.363 ;
     RECT  58.716 37.291 58.842 37.391 ;
     RECT  2.304 36.907 5.958 37.399 ;
     RECT  6.696 37.363 8.406 37.399 ;
     RECT  64.656 37.355 66.51 37.471 ;
     RECT  0.324 37.483 0.342 37.561 ;
     RECT  9.396 37.319 9.45 37.589 ;
     RECT  9.396 37.589 9.414 37.625 ;
     RECT  58.716 37.391 58.77 37.625 ;
     RECT  64.656 37.471 66.546 37.669 ;
     RECT  67.284 36.419 68.418 37.669 ;
     RECT  0.324 37.561 0.558 37.709 ;
     RECT  64.656 37.669 68.418 37.733 ;
     RECT  10.836 37.627 10.854 37.757 ;
     RECT  2.304 37.399 8.406 37.903 ;
     RECT  59.868 37.165 63.522 37.903 ;
     RECT  64.908 37.733 68.418 37.931 ;
     RECT  64.908 37.931 67.806 38.003 ;
     RECT  2.304 37.903 8.442 38.039 ;
     RECT  66.096 38.003 67.806 38.093 ;
     RECT  59.868 37.903 63.666 38.129 ;
     RECT  67.788 38.093 67.806 38.129 ;
     RECT  59.868 38.129 63.522 38.201 ;
     RECT  68.976 38.155 69.03 38.309 ;
     RECT  13.215 36.797 13.497 38.395 ;
     RECT  2.34 38.039 8.442 38.399 ;
     RECT  64.908 38.003 65.034 38.399 ;
     RECT  0.144 38.203 0.198 38.407 ;
     RECT  14.796 38.371 14.814 38.429 ;
     RECT  68.976 38.309 68.994 38.435 ;
     RECT  10.728 38.281 10.818 38.471 ;
     RECT  13.215 38.395 13.734 38.641 ;
     RECT  0.108 38.407 0.198 38.669 ;
     RECT  59.868 38.201 60.102 38.669 ;
     RECT  66.096 38.093 66.69 38.669 ;
     RECT  13.215 38.641 13.806 38.741 ;
     RECT  2.34 38.399 8.37 38.827 ;
     RECT  61.128 38.201 63.522 38.911 ;
     RECT  0.18 38.669 0.198 38.923 ;
     RECT  10.836 38.641 10.854 38.939 ;
     RECT  13.215 38.741 13.734 38.939 ;
     RECT  2.304 38.827 8.37 39.011 ;
     RECT  0.18 38.923 0.342 39.067 ;
     RECT  9.216 38.551 9.234 39.091 ;
     RECT  61.128 38.911 63.738 39.091 ;
     RECT  64.692 38.821 64.818 39.091 ;
     RECT  67.824 38.821 67.842 39.091 ;
     RECT  0.18 39.067 0.414 39.119 ;
     RECT  0.18 39.119 0.342 39.149 ;
     RECT  61.128 39.091 64.818 39.181 ;
     RECT  65.844 39.091 66.042 39.181 ;
     RECT  9.144 39.091 9.234 39.209 ;
     RECT  13.215 38.939 13.662 39.245 ;
     RECT  61.128 39.181 65.034 39.307 ;
     RECT  9.18 39.209 9.234 39.325 ;
     RECT  60.948 39.307 65.034 39.325 ;
     RECT  65.772 39.181 66.042 39.325 ;
     RECT  60.948 39.325 66.042 39.341 ;
     RECT  67.284 39.091 67.842 39.361 ;
     RECT  69.012 39.307 69.03 39.361 ;
     RECT  13.215 39.245 13.497 39.451 ;
     RECT  61.815 39.341 66.042 39.451 ;
     RECT  67.284 39.361 69.03 39.451 ;
     RECT  13.104 39.451 13.497 39.488 ;
     RECT  59.868 38.669 59.886 39.515 ;
     RECT  9.18 39.325 9.27 39.659 ;
     RECT  9.18 39.659 9.234 39.749 ;
     RECT  60.948 39.341 60.966 39.785 ;
     RECT  9.216 39.749 9.234 39.821 ;
     RECT  60.012 39.631 60.03 39.821 ;
     RECT  61.815 39.451 69.03 39.857 ;
     RECT  61.815 39.857 66.69 39.869 ;
     RECT  2.376 39.011 8.37 39.901 ;
     RECT  63.216 39.869 66.69 39.917 ;
     RECT  2.304 39.901 8.37 40.013 ;
     RECT  6.624 40.013 8.37 40.019 ;
     RECT  2.304 40.013 5.814 40.055 ;
     RECT  2.304 40.055 3.474 40.091 ;
     RECT  63.216 39.917 64.782 40.091 ;
     RECT  65.556 39.917 66.69 40.109 ;
     RECT  66.6 40.109 66.69 40.127 ;
     RECT  58.716 37.625 58.734 40.199 ;
     RECT  64.44 40.091 64.782 40.199 ;
     RECT  66.6 40.127 66.618 40.199 ;
     RECT  0.144 39.403 0.162 40.267 ;
     RECT  4.212 40.055 5.814 40.289 ;
     RECT  63.216 40.091 63.702 40.289 ;
     RECT  18.504 36.887 38.754 40.297 ;
     RECT  2.304 40.091 3.294 40.301 ;
     RECT  0.144 40.267 0.342 40.397 ;
     RECT  18.504 40.297 39.078 40.405 ;
     RECT  40.215 35.401 48.078 40.405 ;
     RECT  10.8 40.261 10.818 40.433 ;
     RECT  54.72 40.333 54.738 40.667 ;
     RECT  9.468 40.531 9.486 40.711 ;
     RECT  58.752 40.567 58.842 40.739 ;
     RECT  59.868 40.297 59.886 40.795 ;
     RECT  60.84 40.795 60.858 40.801 ;
     RECT  64.62 40.199 64.782 40.801 ;
     RECT  65.556 40.109 65.79 40.801 ;
     RECT  59.796 40.795 59.886 40.838 ;
     RECT  64.62 40.801 65.79 40.843 ;
     RECT  5.436 40.289 5.814 40.891 ;
     RECT  6.624 40.019 8.262 40.891 ;
     RECT  59.832 40.838 59.85 40.937 ;
     RECT  5.436 40.891 8.262 40.981 ;
     RECT  60.84 40.801 61.074 40.981 ;
     RECT  61.815 39.869 62.226 40.981 ;
     RECT  4.212 40.289 4.59 41.071 ;
     RECT  5.436 40.981 8.442 41.071 ;
     RECT  9.432 40.711 9.486 41.071 ;
     RECT  4.212 41.071 9.486 41.107 ;
     RECT  67.788 39.857 69.03 41.107 ;
     RECT  2.34 40.301 3.294 41.131 ;
     RECT  64.62 40.843 66.186 41.143 ;
     RECT  67.284 41.107 69.03 41.143 ;
     RECT  10.764 41.071 10.782 41.171 ;
     RECT  2.304 41.131 3.294 41.179 ;
     RECT  4.212 41.107 9.558 41.179 ;
     RECT  63.216 40.289 63.666 41.179 ;
     RECT  64.62 41.143 69.03 41.179 ;
     RECT  0.144 40.397 0.162 41.212 ;
     RECT  2.304 41.179 9.558 41.213 ;
     RECT  60.696 40.981 61.074 41.251 ;
     RECT  61.815 40.981 62.262 41.251 ;
     RECT  63.216 41.179 69.03 41.251 ;
     RECT  60.696 41.251 62.262 41.341 ;
     RECT  63.144 41.251 69.03 41.341 ;
     RECT  2.304 41.213 9.486 41.513 ;
     RECT  10.908 41.341 10.926 41.549 ;
     RECT  56.415 35.159 56.697 41.611 ;
     RECT  58.752 40.739 58.77 41.611 ;
     RECT  58.716 41.611 58.77 41.647 ;
     RECT  2.304 41.513 9.234 41.648 ;
     RECT  60.696 41.341 69.03 41.683 ;
     RECT  60.156 41.683 69.03 41.981 ;
     RECT  2.415 41.648 9.234 42.089 ;
     RECT  56.304 41.611 56.697 42.089 ;
     RECT  2.415 42.089 9.162 42.179 ;
     RECT  60.156 41.981 68.994 42.187 ;
     RECT  58.716 41.647 58.806 42.295 ;
     RECT  58.716 42.295 58.842 42.331 ;
     RECT  60.084 42.187 68.994 42.331 ;
     RECT  2.415 42.179 9.126 42.359 ;
     RECT  2.415 42.359 8.226 42.379 ;
     RECT  58.716 42.331 68.994 42.449 ;
     RECT  9 42.359 9.126 42.521 ;
     RECT  59.832 42.449 68.994 42.521 ;
     RECT  59.832 42.521 60.102 42.593 ;
     RECT  60.84 42.521 68.994 42.629 ;
     RECT  59.832 42.593 60.066 42.719 ;
     RECT  58.716 42.449 59.022 42.749 ;
     RECT  60.84 42.629 68.418 42.755 ;
     RECT  0.108 41.212 0.198 42.797 ;
     RECT  10.8 42.799 10.818 42.871 ;
     RECT  0.18 42.797 0.198 42.989 ;
     RECT  9.108 42.521 9.126 43.069 ;
     RECT  10.656 42.871 10.818 43.133 ;
     RECT  9.108 43.069 9.234 43.169 ;
     RECT  59.832 42.719 60.03 43.181 ;
     RECT  2.304 42.379 8.226 43.231 ;
     RECT  2.16 43.231 8.226 43.277 ;
     RECT  9.216 43.169 9.234 43.303 ;
     RECT  58.716 42.749 58.878 43.325 ;
     RECT  60.84 42.755 66.294 43.325 ;
     RECT  10.764 43.133 10.818 43.34 ;
     RECT  67.284 42.755 68.418 43.531 ;
     RECT  59.868 43.181 60.03 43.537 ;
     RECT  60.84 43.325 63.558 43.537 ;
     RECT  0.54 43.303 0.558 43.565 ;
     RECT  9.216 43.303 9.414 43.609 ;
     RECT  67.248 43.531 68.418 43.627 ;
     RECT  56.415 42.089 56.697 43.672 ;
     RECT  2.304 43.277 8.226 43.681 ;
     RECT  56.304 43.672 56.697 43.709 ;
     RECT  64.332 43.325 66.294 43.771 ;
     RECT  18.504 40.405 48.078 43.807 ;
     RECT  18.504 43.807 48.474 43.879 ;
     RECT  2.304 43.681 8.406 43.951 ;
     RECT  9.216 43.609 9.45 43.951 ;
     RECT  58.716 43.325 58.842 44.069 ;
     RECT  59.868 43.537 63.558 44.104 ;
     RECT  64.332 43.771 66.474 44.104 ;
     RECT  10.764 43.34 10.782 44.149 ;
     RECT  59.868 44.104 66.474 44.221 ;
     RECT  67.248 43.627 69.03 44.221 ;
     RECT  54.72 44.107 54.738 44.237 ;
     RECT  2.304 43.951 9.45 44.299 ;
     RECT  2.268 44.299 9.45 44.311 ;
     RECT  2.268 44.311 9.63 44.339 ;
     RECT  18.504 43.879 48.726 44.347 ;
     RECT  0.144 44.011 0.27 44.381 ;
     RECT  59.868 44.221 69.03 44.411 ;
     RECT  67.284 44.411 69.03 44.447 ;
     RECT  0.144 44.381 0.234 44.519 ;
     RECT  51.015 25.889 51.297 44.653 ;
     RECT  18.504 44.347 48.942 44.689 ;
     RECT  59.868 44.411 66.33 44.717 ;
     RECT  0.144 44.519 0.198 44.779 ;
     RECT  67.284 44.447 68.49 44.813 ;
     RECT  0.108 44.779 0.198 44.879 ;
     RECT  18.504 44.689 49.374 44.887 ;
     RECT  10.728 44.149 10.818 44.915 ;
     RECT  59.868 44.717 59.886 44.915 ;
     RECT  2.304 44.339 9.63 44.923 ;
     RECT  60.84 44.717 66.33 44.951 ;
     RECT  2.304 44.923 9.702 45.005 ;
     RECT  2.304 45.005 7.002 45.149 ;
     RECT  58.716 44.069 58.806 45.157 ;
     RECT  60.948 44.951 66.33 45.197 ;
     RECT  18.504 44.887 49.446 45.229 ;
     RECT  64.404 45.197 66.33 45.229 ;
     RECT  58.716 45.157 58.842 45.293 ;
     RECT  64.404 45.229 66.402 45.301 ;
     RECT  10.764 44.915 10.818 45.329 ;
     RECT  3.996 45.149 4.374 45.419 ;
     RECT  50.436 44.653 51.297 45.427 ;
     RECT  18.504 45.229 49.554 45.463 ;
     RECT  50.4 45.427 51.297 45.463 ;
     RECT  67.752 44.813 68.49 45.547 ;
     RECT  2.304 45.149 3.186 45.769 ;
     RECT  60.948 45.197 63.594 45.769 ;
     RECT  7.815 45.005 9.702 45.821 ;
     RECT  56.415 43.709 56.697 45.832 ;
     RECT  10.908 45.661 10.926 45.833 ;
     RECT  2.268 45.769 3.186 45.869 ;
     RECT  54.72 45.769 54.738 45.869 ;
     RECT  56.304 45.832 56.697 45.869 ;
     RECT  60.84 45.769 63.594 45.931 ;
     RECT  5.148 45.149 7.002 45.995 ;
     RECT  5.148 45.995 5.922 46.031 ;
     RECT  7.815 45.821 8.55 46.031 ;
     RECT  4.104 45.419 4.374 46.075 ;
     RECT  5.148 46.031 5.706 46.075 ;
     RECT  67.752 45.547 69.03 46.139 ;
     RECT  6.948 45.995 7.002 46.201 ;
     RECT  7.815 46.031 8.406 46.201 ;
     RECT  60.84 45.931 63.666 46.201 ;
     RECT  64.404 45.301 66.69 46.201 ;
     RECT  2.304 45.869 3.186 46.237 ;
     RECT  60.84 46.201 66.69 46.237 ;
     RECT  0.54 46.111 0.558 46.253 ;
     RECT  2.304 46.237 3.294 46.315 ;
     RECT  4.104 46.075 5.706 46.315 ;
     RECT  58.716 45.293 58.806 46.345 ;
     RECT  68.328 46.139 69.03 46.409 ;
     RECT  14.832 46.237 14.85 46.507 ;
     RECT  60.84 46.237 67.338 46.535 ;
     RECT  68.328 46.409 68.994 46.535 ;
     RECT  10.8 46.471 10.818 46.543 ;
     RECT  14.832 46.507 14.886 46.543 ;
     RECT  60.84 46.535 66.366 46.603 ;
     RECT  10.728 46.543 10.818 46.679 ;
     RECT  2.304 46.315 5.706 46.685 ;
     RECT  58.716 46.345 58.914 46.813 ;
     RECT  59.868 45.805 59.886 46.849 ;
     RECT  6.948 46.201 8.406 46.885 ;
     RECT  9.396 45.821 9.702 46.885 ;
     RECT  59.724 46.849 59.886 46.885 ;
     RECT  2.304 46.685 2.862 46.921 ;
     RECT  6.948 46.885 9.702 46.921 ;
     RECT  59.724 46.885 59.994 46.925 ;
     RECT  2.268 46.921 2.862 47.021 ;
     RECT  6.444 46.921 9.702 47.111 ;
     RECT  67.248 46.535 67.338 47.179 ;
     RECT  68.328 46.535 68.418 47.179 ;
     RECT  3.6 46.685 5.706 47.191 ;
     RECT  6.444 47.111 8.838 47.191 ;
     RECT  58.716 46.813 58.95 47.309 ;
     RECT  14.832 46.543 14.958 47.353 ;
     RECT  9.684 47.111 9.702 47.381 ;
     RECT  18.504 45.463 51.297 47.381 ;
     RECT  0.144 46.555 0.162 47.419 ;
     RECT  10.764 46.679 10.818 47.425 ;
     RECT  14.832 47.353 15.03 47.453 ;
     RECT  2.304 47.021 2.862 47.461 ;
     RECT  3.6 47.191 8.838 47.461 ;
     RECT  60.732 46.603 66.366 47.461 ;
     RECT  67.248 47.179 68.418 47.461 ;
     RECT  0.144 47.419 0.234 47.597 ;
     RECT  14.832 47.453 14.958 47.651 ;
     RECT  14.94 47.651 14.958 47.687 ;
     RECT  60.732 47.461 68.418 47.755 ;
     RECT  60.732 47.755 69.03 47.759 ;
     RECT  10.764 47.425 10.926 47.849 ;
     RECT  2.304 47.461 8.838 47.893 ;
     RECT  2.304 47.893 8.91 47.993 ;
     RECT  58.716 47.309 58.806 48.043 ;
     RECT  10.836 47.849 10.926 48.155 ;
     RECT  58.716 48.043 58.878 48.155 ;
     RECT  58.716 48.155 58.806 48.191 ;
     RECT  10.908 48.155 10.926 48.199 ;
     RECT  2.304 47.993 8.874 48.227 ;
     RECT  59.976 46.925 59.994 48.271 ;
     RECT  10.908 48.199 10.998 48.299 ;
     RECT  0.144 47.597 0.162 48.361 ;
     RECT  60.804 47.759 69.03 48.461 ;
     RECT  59.976 48.271 60.03 48.505 ;
     RECT  59.796 48.505 60.03 48.523 ;
     RECT  60.804 48.461 66.762 48.523 ;
     RECT  59.796 48.523 66.762 48.557 ;
     RECT  59.868 48.557 66.762 48.569 ;
     RECT  6.48 48.227 8.874 48.763 ;
     RECT  6.48 48.763 9.126 48.775 ;
     RECT  2.304 48.227 5.706 48.848 ;
     RECT  2.415 48.848 5.706 48.929 ;
     RECT  6.48 48.775 9.342 48.941 ;
     RECT  4.14 48.929 5.67 49.001 ;
     RECT  9.252 48.941 9.342 49.001 ;
     RECT  10.836 48.907 10.89 49.009 ;
     RECT  59.868 48.569 60.138 49.037 ;
     RECT  10.728 49.009 10.89 49.081 ;
     RECT  59.868 49.037 59.994 49.085 ;
     RECT  0.108 48.361 0.198 49.109 ;
     RECT  0.108 49.109 0.126 49.133 ;
     RECT  5.076 49.001 5.67 49.199 ;
     RECT  6.48 48.941 8.478 49.199 ;
     RECT  10.656 49.081 10.89 49.207 ;
     RECT  4.14 49.001 4.158 49.235 ;
     RECT  2.415 48.929 2.862 49.271 ;
     RECT  10.656 49.207 10.926 49.271 ;
     RECT  6.66 49.199 8.478 49.325 ;
     RECT  5.508 49.199 5.67 49.379 ;
     RECT  10.908 49.271 10.926 49.379 ;
     RECT  67.788 48.461 69.03 49.379 ;
     RECT  67.788 49.379 68.418 49.421 ;
     RECT  60.876 48.569 66.762 49.441 ;
     RECT  5.544 49.379 5.562 49.469 ;
     RECT  6.66 49.325 6.75 49.469 ;
     RECT  7.815 49.325 8.478 49.469 ;
     RECT  9.252 49.001 9.27 49.469 ;
     RECT  60.84 49.441 66.762 49.483 ;
     RECT  67.788 49.421 67.842 49.483 ;
     RECT  59.868 49.085 59.886 49.505 ;
     RECT  58.716 48.191 58.734 49.621 ;
     RECT  60.84 49.483 67.842 49.805 ;
     RECT  58.716 49.621 58.878 49.811 ;
     RECT  60.84 49.805 66.294 49.919 ;
     RECT  64.296 49.919 66.294 50.189 ;
     RECT  67.248 49.805 67.842 50.359 ;
     RECT  69.012 50.155 69.03 50.359 ;
     RECT  67.248 50.359 69.03 50.381 ;
     RECT  64.296 50.189 65.682 50.585 ;
     RECT  59.868 50.395 59.886 50.683 ;
     RECT  60.84 49.919 63.558 50.791 ;
     RECT  64.296 50.585 65.286 50.791 ;
     RECT  58.716 49.811 58.806 50.827 ;
     RECT  66.6 50.593 66.618 50.971 ;
     RECT  58.716 50.827 58.842 51.061 ;
     RECT  59.868 50.683 60.102 51.061 ;
     RECT  60.84 50.791 65.286 51.061 ;
     RECT  66.024 50.971 66.618 51.115 ;
     RECT  67.752 50.381 69.03 51.115 ;
     RECT  59.868 51.061 65.286 51.125 ;
     RECT  66.024 51.115 69.03 51.161 ;
     RECT  58.716 51.061 58.95 51.233 ;
     RECT  18.576 47.381 51.297 51.241 ;
     RECT  58.716 51.233 58.914 51.269 ;
     RECT  60.084 51.125 65.286 51.269 ;
     RECT  18.504 51.241 51.297 51.293 ;
     RECT  64.764 51.269 65.286 51.293 ;
     RECT  66.024 51.161 66.69 51.359 ;
     RECT  67.788 51.161 69.03 51.359 ;
     RECT  60.084 51.269 63.774 51.395 ;
     RECT  66.132 51.359 66.69 51.395 ;
     RECT  68.364 51.359 69.03 51.431 ;
     RECT  68.364 51.431 68.382 51.539 ;
     RECT  58.716 51.269 58.734 51.629 ;
     RECT  60.804 51.395 63.774 51.629 ;
     RECT  64.764 51.293 65.106 51.629 ;
     RECT  60.804 51.629 61.038 51.665 ;
     RECT  64.764 51.629 64.962 51.665 ;
     RECT  61.815 51.629 63.414 51.737 ;
     RECT  66.672 51.395 66.69 51.737 ;
     RECT  61.815 51.737 62.73 51.809 ;
     RECT  64.944 51.665 64.962 51.809 ;
     RECT  61.815 51.809 62.514 51.899 ;
     RECT  60.804 51.665 60.822 51.935 ;
     RECT  13.215 39.488 13.497 57.001 ;
     RECT  14.292 56.683 14.31 57.001 ;
     RECT  13.215 57.001 14.31 57.053 ;
     RECT  17.712 63.751 17.73 63.823 ;
     RECT  18.576 51.293 51.297 63.823 ;
     RECT  17.712 63.823 51.297 65.245 ;
     RECT  17.532 65.245 51.297 65.515 ;
     RECT  17.46 65.515 51.297 66.653 ;
     RECT  2.415 49.271 2.697 66.707 ;
     RECT  7.815 49.469 8.097 66.707 ;
     RECT  13.215 57.053 13.497 66.707 ;
     RECT  28.296 66.653 51.297 66.707 ;
     RECT  56.415 45.869 56.697 66.707 ;
     RECT  61.815 51.899 62.097 66.707 ;
     RECT  28.296 66.707 51.105 66.749 ;
     RECT  17.46 66.653 27.306 66.785 ;
     RECT  28.368 66.749 38.322 66.797 ;
     RECT  39.132 66.749 51.105 66.797 ;
     RECT  42.048 66.797 51.105 66.857 ;
     RECT  17.46 66.785 27.126 66.929 ;
     RECT  36.756 66.797 38.322 66.929 ;
     RECT  2.415 66.707 2.505 66.977 ;
     RECT  7.815 66.707 7.905 66.977 ;
     RECT  13.215 66.707 13.305 66.977 ;
     RECT  51.015 66.857 51.105 66.977 ;
     RECT  56.415 66.707 56.505 66.977 ;
     RECT  61.815 66.707 61.905 66.977 ;
     RECT  39.132 66.797 41.094 66.989 ;
     RECT  28.368 66.797 35.982 67.085 ;
     RECT  39.276 66.989 41.094 67.181 ;
     RECT  17.46 66.929 26.946 67.229 ;
     RECT  42.048 66.857 50.274 67.229 ;
     RECT  17.46 67.229 22.59 67.277 ;
     RECT  23.328 67.229 26.946 67.277 ;
     RECT  28.368 67.085 28.71 67.277 ;
     RECT  29.556 67.085 35.982 67.277 ;
     RECT  36.756 66.929 38.106 67.277 ;
     RECT  39.276 67.181 39.798 67.277 ;
     RECT  40.572 67.181 41.094 67.277 ;
     RECT  42.048 67.229 49.59 67.277 ;
     RECT  26.82 67.277 26.946 67.325 ;
     RECT  29.628 67.277 30.654 67.325 ;
     RECT  32.688 67.277 32.706 67.325 ;
     RECT  41.076 67.277 41.094 67.325 ;
     RECT  44.388 67.277 44.622 67.325 ;
     RECT  17.46 67.277 19.098 67.373 ;
     RECT  26.856 67.325 26.946 67.373 ;
     RECT  23.652 67.277 24.39 67.757 ;
     RECT  30.492 67.325 30.654 67.805 ;
     RECT  17.46 67.373 17.694 67.853 ;
     RECT  20.484 67.277 20.898 67.853 ;
     RECT  23.832 67.757 24.39 67.853 ;
     RECT  30.636 67.805 30.654 67.853 ;
     RECT  31.716 67.277 31.914 67.853 ;
     RECT  34.092 67.277 34.542 67.853 ;
     RECT  38.088 67.277 38.106 67.853 ;
     RECT  17.532 67.853 17.694 67.901 ;
     RECT  20.88 67.853 20.898 67.901 ;
     RECT  17.532 67.901 17.586 67.949 ;
     RECT  23.868 67.853 23.886 67.949 ;
     RECT  17.568 67.949 17.586 68.429 ;
     RECT  18.432 67.373 19.098 68.429 ;
     RECT  22.428 67.277 22.446 68.429 ;
     RECT  26.856 67.373 26.874 68.429 ;
     RECT  38.304 68.635 38.322 68.731 ;
     RECT  31.896 67.853 31.914 68.861 ;
     RECT  27.612 68.827 27.63 68.875 ;
     RECT  29.628 67.325 29.646 68.875 ;
     RECT  41.4 68.827 41.418 68.875 ;
     RECT  38.268 68.731 38.322 68.909 ;
     RECT  27.612 68.875 27.738 68.957 ;
     RECT  22.932 68.875 22.95 69.005 ;
     RECT  26.712 68.875 26.73 69.005 ;
     RECT  27.72 68.957 27.738 69.005 ;
     RECT  28.764 68.875 29.646 69.005 ;
     RECT  31.032 68.779 31.05 69.005 ;
     RECT  35.316 68.875 35.334 69.005 ;
     RECT  38.304 68.909 38.322 69.005 ;
     RECT  39.24 68.875 39.834 69.005 ;
     RECT  40.68 68.875 41.418 69.005 ;
     RECT  45.144 68.827 45.162 69.005 ;
     RECT  45.972 68.875 45.99 69.005 ;
     RECT  48.924 67.277 48.942 69.005 ;
    LAYER M4 ;
     RECT  0.06 17.712 0.17 49.128 ;
     RECT  0.17 17.712 0.569 49.08 ;
     RECT  0.569 17.808 2.408 49.08 ;
     RECT  2.408 2.148 2.512 66.972 ;
     RECT  2.512 2.418 2.704 66.702 ;
     RECT  2.704 17.76 4.129 49.08 ;
     RECT  4.129 17.76 4.493 49.224 ;
     RECT  4.493 17.904 4.565 49.224 ;
     RECT  4.565 18 5.497 49.224 ;
     RECT  5.497 18 6.901 49.32 ;
     RECT  6.901 17.904 7.808 49.32 ;
     RECT  7.808 2.148 7.912 66.972 ;
     RECT  7.912 2.418 8.104 66.702 ;
     RECT  8.104 17.904 8.165 24.648 ;
     RECT  8.104 32.736 8.165 39.48 ;
     RECT  8.104 25.824 8.201 30.168 ;
     RECT  8.104 43.92 8.237 48.792 ;
     RECT  8.201 26.304 8.281 30.168 ;
     RECT  8.281 29.328 8.453 30.168 ;
     RECT  8.165 17.904 8.489 24.216 ;
     RECT  8.281 26.304 8.489 28.2 ;
     RECT  8.453 29.568 8.489 30.168 ;
     RECT  8.489 26.304 8.525 27.96 ;
     RECT  8.525 26.304 8.561 26.616 ;
     RECT  8.525 27.6 8.561 27.96 ;
     RECT  8.237 44.064 8.561 48.792 ;
     RECT  8.561 45.792 8.597 48.792 ;
     RECT  8.561 27.6 8.669 27.624 ;
     RECT  8.489 18.816 8.813 24.216 ;
     RECT  8.489 30.096 8.813 30.168 ;
     RECT  8.813 18.816 8.885 20.088 ;
     RECT  8.813 30.096 8.885 30.12 ;
     RECT  8.597 48.24 8.885 48.792 ;
     RECT  8.885 19.248 8.993 20.088 ;
     RECT  8.885 48.768 9.097 48.792 ;
     RECT  8.165 32.736 9.137 32.808 ;
     RECT  8.104 40.848 9.137 41.496 ;
     RECT  8.597 45.792 9.137 46.92 ;
     RECT  9.097 48.768 9.137 48.936 ;
     RECT  8.165 34.08 9.245 39.48 ;
     RECT  8.104 31.44 9.281 31.512 ;
     RECT  8.813 21.168 9.317 24.216 ;
     RECT  8.993 19.248 9.425 19.8 ;
     RECT  9.137 45.984 9.533 46.872 ;
     RECT  9.137 40.848 9.569 41.208 ;
     RECT  8.561 44.064 9.569 44.808 ;
     RECT  9.281 31.44 9.605 31.464 ;
     RECT  9.317 22.08 10.789 24.216 ;
     RECT  10.789 22.08 10.825 24.36 ;
     RECT  9.137 48.912 10.825 48.936 ;
     RECT  10.825 21.984 10.865 24.36 ;
     RECT  10.825 48.912 10.865 49.032 ;
     RECT  9.425 19.488 13.208 19.8 ;
     RECT  10.865 21.984 13.208 22.008 ;
     RECT  10.865 23.04 13.208 24.36 ;
     RECT  8.561 26.352 13.208 26.616 ;
     RECT  9.137 32.736 13.208 32.76 ;
     RECT  9.245 34.08 13.208 35.256 ;
     RECT  9.245 36.528 13.208 39.48 ;
     RECT  9.569 40.848 13.208 40.872 ;
     RECT  9.569 44.064 13.208 44.424 ;
     RECT  9.533 45.984 13.208 46.776 ;
     RECT  10.865 49.008 13.208 49.032 ;
     RECT  13.208 2.148 13.312 66.972 ;
     RECT  13.312 2.418 13.504 66.702 ;
     RECT  13.504 36.528 13.673 39.48 ;
     RECT  13.504 49.008 13.811 49.032 ;
     RECT  13.504 45.984 14.339 46.776 ;
     RECT  13.504 56.688 14.339 57.048 ;
     RECT  14.339 46.08 14.857 46.776 ;
     RECT  17.449 67.824 17.521 67.848 ;
     RECT  17.521 67.824 17.557 67.944 ;
     RECT  17.557 67.824 17.701 68.424 ;
     RECT  17.701 67.248 17.773 68.424 ;
     RECT  17.845 65.136 18.097 65.16 ;
     RECT  13.504 19.488 18.608 19.8 ;
     RECT  13.504 22.08 18.608 24.36 ;
     RECT  13.504 26.352 18.608 26.616 ;
     RECT  13.504 32.736 18.608 32.76 ;
     RECT  13.504 34.08 18.608 35.256 ;
     RECT  13.673 36.528 18.608 38.424 ;
     RECT  13.673 39.456 18.608 39.48 ;
     RECT  13.504 40.848 18.608 40.872 ;
     RECT  13.504 44.064 18.608 44.424 ;
     RECT  14.857 46.08 18.608 46.872 ;
     RECT  13.504 51.264 18.608 51.288 ;
     RECT  14.339 57.024 18.608 57.048 ;
     RECT  18.097 65.136 18.608 65.544 ;
     RECT  17.773 66.72 18.608 68.424 ;
     RECT  18.608 2.148 18.712 68.424 ;
     RECT  18.712 2.418 18.899 68.424 ;
     RECT  18.899 2.418 18.904 67.272 ;
     RECT  18.899 68.4 19.763 68.424 ;
     RECT  18.904 46.08 19.901 47.688 ;
     RECT  18.904 64.464 19.933 64.488 ;
     RECT  19.901 47.376 20.045 47.688 ;
     RECT  18.904 26.304 20.185 27.72 ;
     RECT  20.045 47.424 20.297 47.688 ;
     RECT  20.297 47.664 20.369 47.688 ;
     RECT  20.341 63.216 20.401 63.24 ;
     RECT  18.904 51.264 20.437 51.288 ;
     RECT  18.904 66.72 20.473 67.272 ;
     RECT  19.933 64.464 20.531 65.112 ;
     RECT  20.341 68.928 20.531 68.952 ;
     RECT  20.531 64.464 20.653 64.584 ;
     RECT  20.437 50.784 20.765 51.288 ;
     RECT  20.473 66.72 20.869 67.848 ;
     RECT  20.869 66.72 21.011 67.896 ;
     RECT  21.011 66.816 21.107 67.896 ;
     RECT  20.401 63.168 21.121 63.24 ;
     RECT  20.653 64.32 21.121 64.584 ;
     RECT  21.107 67.248 21.203 67.896 ;
     RECT  18.904 19.488 21.409 19.8 ;
     RECT  21.121 63.168 21.541 64.584 ;
     RECT  21.637 68.928 21.829 68.952 ;
     RECT  21.541 63.072 21.913 64.584 ;
     RECT  21.625 65.568 21.971 65.592 ;
     RECT  20.185 26.304 21.985 28.152 ;
     RECT  18.904 39.456 22.129 39.48 ;
     RECT  22.129 39.456 22.165 39.624 ;
     RECT  21.203 67.248 22.213 67.272 ;
     RECT  22.213 67.2 22.364 67.272 ;
     RECT  21.829 68.88 22.417 68.952 ;
     RECT  22.364 66.72 22.451 67.272 ;
     RECT  21.913 62.112 22.457 64.584 ;
     RECT  22.457 62.304 22.525 64.584 ;
     RECT  18.904 40.848 22.811 40.872 ;
     RECT  18.904 22.08 22.813 24.36 ;
     RECT  22.811 40.848 22.813 40.92 ;
     RECT  21.409 19.488 22.853 19.896 ;
     RECT  22.813 21.984 22.853 24.36 ;
     RECT  22.417 68.4 22.877 68.952 ;
     RECT  22.525 62.304 22.889 64.968 ;
     RECT  20.765 50.784 22.921 50.808 ;
     RECT  22.813 40.848 22.925 41.352 ;
     RECT  22.921 50.784 22.961 50.904 ;
     RECT  22.889 64.272 22.961 64.968 ;
     RECT  22.877 68.4 22.961 69 ;
     RECT  22.961 68.4 23.315 68.904 ;
     RECT  23.315 68.4 23.363 68.808 ;
     RECT  22.165 39.456 23.497 39.864 ;
     RECT  22.925 40.848 23.497 40.968 ;
     RECT  18.904 36.528 23.569 38.424 ;
     RECT  23.497 39.456 23.569 40.968 ;
     RECT  22.451 67.104 23.641 67.272 ;
     RECT  23.363 68.4 23.641 68.424 ;
     RECT  22.489 66.096 23.713 66.12 ;
     RECT  23.641 67.104 23.713 68.424 ;
     RECT  23.713 66.096 23.795 68.424 ;
     RECT  22.853 19.584 24.008 19.896 ;
     RECT  22.853 21.984 24.008 22.008 ;
     RECT  22.853 23.04 24.008 24.36 ;
     RECT  21.985 26.304 24.008 28.968 ;
     RECT  18.904 32.736 24.008 32.76 ;
     RECT  18.904 34.08 24.008 35.256 ;
     RECT  23.569 36.528 24.008 40.968 ;
     RECT  18.904 44.064 24.008 44.424 ;
     RECT  19.901 46.08 24.008 46.104 ;
     RECT  22.961 50.88 24.008 50.904 ;
     RECT  22.889 62.304 24.008 63.24 ;
     RECT  22.961 64.608 24.008 64.968 ;
     RECT  23.795 66.096 24.008 67.944 ;
     RECT  24.008 2.148 24.112 67.944 ;
     RECT  24.112 2.418 24.275 67.944 ;
     RECT  24.275 2.418 24.304 67.848 ;
     RECT  24.304 63.264 24.508 65.016 ;
     RECT  24.304 67.248 24.659 67.848 ;
     RECT  24.304 62.112 24.661 62.136 ;
     RECT  24.508 63.264 24.947 63.336 ;
     RECT  24.947 63.264 25.013 63.288 ;
     RECT  25.093 68.928 25.283 68.952 ;
     RECT  24.304 36.528 25.333 42.888 ;
     RECT  24.304 44.064 25.333 44.424 ;
     RECT  24.659 67.248 25.765 67.272 ;
     RECT  24.508 64.368 25.805 65.016 ;
     RECT  25.765 67.2 26.053 67.272 ;
     RECT  24.304 19.584 26.627 19.896 ;
     RECT  26.245 68.928 26.629 68.952 ;
     RECT  25.333 36.528 26.665 44.424 ;
     RECT  26.629 68.928 26.677 69 ;
     RECT  26.665 36.528 26.773 44.76 ;
     RECT  26.396 63.264 26.773 63.288 ;
     RECT  26.053 66.72 26.776 67.272 ;
     RECT  26.677 68.88 26.845 69 ;
     RECT  25.805 64.608 26.849 65.016 ;
     RECT  26.776 66.72 26.892 67.32 ;
     RECT  24.304 26.304 26.957 28.968 ;
     RECT  26.892 66.72 27.001 67.368 ;
     RECT  26.845 68.4 27.059 69 ;
     RECT  24.304 50.784 27.061 50.808 ;
     RECT  27.061 50.784 27.101 50.904 ;
     RECT  27.001 66.72 27.155 66.744 ;
     RECT  26.773 62.832 27.349 63.288 ;
     RECT  26.849 64.608 27.349 64.728 ;
     RECT  27.349 62.832 27.548 64.728 ;
     RECT  27.548 62.592 27.635 64.728 ;
     RECT  27.059 68.832 27.676 69 ;
     RECT  27.676 68.88 27.779 69 ;
     RECT  27.635 62.64 27.877 64.728 ;
     RECT  26.773 36.528 27.925 44.808 ;
     RECT  27.925 36.528 28.069 44.904 ;
     RECT  24.304 46.08 28.069 46.104 ;
     RECT  27.565 66.624 28.261 66.648 ;
     RECT  28.261 66.624 28.433 67.272 ;
     RECT  27.779 68.928 28.748 69 ;
     RECT  28.969 1.68 29.005 1.704 ;
     RECT  26.957 26.304 29.041 28.728 ;
     RECT  29.005 1.104 29.077 1.704 ;
     RECT  28.748 68.88 29.125 69 ;
     RECT  29.077 1.104 29.257 2.04 ;
     RECT  29.221 3.936 29.257 3.96 ;
     RECT  29.257 1.104 29.267 3.96 ;
     RECT  29.267 1.152 29.408 3.96 ;
     RECT  28.645 5.664 29.408 5.688 ;
     RECT  28.741 6.816 29.408 6.84 ;
     RECT  26.627 19.776 29.408 19.896 ;
     RECT  24.304 22.08 29.408 24.36 ;
     RECT  29.041 26.304 29.408 29.064 ;
     RECT  24.304 32.736 29.408 32.76 ;
     RECT  24.304 34.08 29.408 35.256 ;
     RECT  28.069 36.528 29.408 46.104 ;
     RECT  27.101 50.88 29.408 50.904 ;
     RECT  27.877 62.64 29.408 65.016 ;
     RECT  28.433 66.72 29.408 67.272 ;
     RECT  29.125 68.784 29.651 69 ;
     RECT  29.408 1.152 29.704 67.272 ;
     RECT  29.651 68.928 29.747 69 ;
     RECT  29.704 26.304 29.843 29.64 ;
     RECT  29.704 66.144 29.845 66.168 ;
     RECT  29.704 67.152 29.869 67.272 ;
     RECT  29.704 1.152 29.939 3.96 ;
     RECT  29.939 1.728 30.053 3.96 ;
     RECT  30.053 1.728 30.089 3.624 ;
     RECT  29.704 36.528 30.125 46.104 ;
     RECT  30.229 0.576 30.323 0.6 ;
     RECT  29.869 67.152 30.481 67.32 ;
     RECT  30.089 1.728 30.485 3.048 ;
     RECT  30.485 1.728 30.593 2.952 ;
     RECT  30.481 67.152 30.625 67.8 ;
     RECT  30.593 1.776 30.629 2.952 ;
     RECT  29.704 63.216 30.665 64.968 ;
     RECT  30.629 1.776 30.701 2.904 ;
     RECT  29.704 55.872 30.707 55.896 ;
     RECT  30.701 2.544 30.737 2.904 ;
     RECT  30.125 37.92 30.737 46.104 ;
     RECT  30.665 63.216 30.755 63.24 ;
     RECT  29.747 68.928 30.757 68.952 ;
     RECT  29.704 22.08 30.769 24.36 ;
     RECT  30.769 21.984 30.809 24.36 ;
     RECT  30.625 67.152 30.841 67.848 ;
     RECT  29.704 5.088 30.881 6.84 ;
     RECT  30.881 5.328 30.949 6.84 ;
     RECT  29.843 26.304 30.953 29.352 ;
     RECT  30.841 66.768 30.977 67.848 ;
     RECT  30.757 68.832 30.977 68.952 ;
     RECT  30.977 66.768 30.994 68.952 ;
     RECT  30.994 66.768 30.997 69 ;
     RECT  30.997 66.72 31.061 69 ;
     RECT  31.061 68.832 31.091 69 ;
     RECT  30.665 64.32 31.097 64.968 ;
     RECT  31.061 66.72 31.475 67.848 ;
     RECT  30.125 36.528 31.673 36.936 ;
     RECT  31.345 62.832 31.717 62.856 ;
     RECT  31.097 64.32 31.717 64.344 ;
     RECT  31.597 4.08 31.885 4.104 ;
     RECT  31.717 62.832 31.925 64.344 ;
     RECT  31.849 0.096 31.993 0.12 ;
     RECT  31.475 66.912 32.051 67.848 ;
     RECT  31.925 64.32 32.137 64.344 ;
     RECT  30.737 2.544 32.173 2.616 ;
     RECT  31.993 0.096 32.209 0.168 ;
     RECT  31.673 36.528 32.213 36.888 ;
     RECT  32.209 0.096 32.243 0.552 ;
     RECT  32.173 2.448 32.245 2.616 ;
     RECT  31.885 4.08 32.245 4.152 ;
     RECT  31.091 68.832 32.291 68.952 ;
     RECT  32.243 0.144 32.339 0.552 ;
     RECT  32.291 68.832 32.339 68.856 ;
     RECT  32.245 2.448 32.348 4.152 ;
     RECT  32.339 0.48 32.53 0.552 ;
     RECT  32.051 66.912 32.533 67.32 ;
     RECT  32.53 0.48 32.605 0.6 ;
     RECT  32.605 0.48 32.732 1.08 ;
     RECT  32.348 2.256 32.821 4.152 ;
     RECT  32.821 2.256 32.869 4.2 ;
     RECT  30.949 5.328 32.869 6.888 ;
     RECT  32.137 64.32 32.897 65.016 ;
     RECT  32.533 66.864 32.924 67.32 ;
     RECT  30.737 37.92 33.073 38.184 ;
     RECT  30.737 39.312 33.073 46.104 ;
     RECT  32.869 2.256 33.077 6.888 ;
     RECT  33.073 37.92 33.077 46.104 ;
     RECT  33.077 5.52 33.109 6.888 ;
     RECT  32.732 0.48 33.203 1.128 ;
     RECT  33.203 0.528 33.245 1.128 ;
     RECT  33.077 2.256 33.245 4.2 ;
     RECT  31.925 62.832 33.293 63.24 ;
     RECT  32.897 64.992 33.293 65.016 ;
     RECT  33.077 38.112 33.365 46.104 ;
     RECT  33.365 38.928 33.689 46.104 ;
     RECT  33.109 5.52 33.757 7.176 ;
     RECT  32.924 66.72 34.081 67.32 ;
     RECT  29.704 50.784 34.213 50.808 ;
     RECT  33.361 62.736 34.501 62.76 ;
     RECT  34.009 63.792 34.501 63.816 ;
     RECT  33.245 0.528 34.549 4.2 ;
     RECT  33.757 5.52 34.549 7.992 ;
     RECT  29.704 19.872 34.693 19.896 ;
     RECT  29.704 32.736 34.765 32.76 ;
     RECT  34.549 0.528 34.789 7.992 ;
     RECT  34.081 66.72 34.789 67.848 ;
     RECT  34.789 0.432 34.808 7.992 ;
     RECT  34.693 19.536 34.808 19.896 ;
     RECT  30.809 21.984 34.808 22.008 ;
     RECT  30.809 23.04 34.808 24.36 ;
     RECT  30.953 26.304 34.808 28.968 ;
     RECT  34.405 31.104 34.808 31.128 ;
     RECT  34.765 32.304 34.808 32.76 ;
     RECT  29.704 34.08 34.808 35.256 ;
     RECT  32.213 36.528 34.808 36.792 ;
     RECT  33.689 39.312 34.808 46.104 ;
     RECT  34.213 50.784 34.808 50.904 ;
     RECT  34.501 62.736 34.808 63.816 ;
     RECT  34.789 66.72 34.808 68.76 ;
     RECT  34.808 0.432 34.933 68.76 ;
     RECT  34.933 0.192 34.979 68.76 ;
     RECT  34.979 1.728 35.104 68.76 ;
     RECT  35.104 66.144 35.123 68.76 ;
     RECT  34.979 0.192 35.173 0.552 ;
     RECT  35.123 68.736 35.173 68.76 ;
     RECT  35.173 68.736 35.219 69 ;
     RECT  35.173 0.096 35.273 0.552 ;
     RECT  35.104 1.728 35.273 8.424 ;
     RECT  35.273 0.192 35.315 0.552 ;
     RECT  35.219 68.88 35.366 69 ;
     RECT  35.273 2.256 35.417 8.424 ;
     RECT  35.104 62.976 35.417 63.864 ;
     RECT  35.315 0.528 35.795 0.552 ;
     RECT  35.123 66.144 36.097 67.272 ;
     RECT  35.417 62.976 36.101 63.816 ;
     RECT  36.101 63.216 36.173 63.816 ;
     RECT  35.366 68.928 36.179 68.952 ;
     RECT  36.097 66.096 36.46 67.272 ;
     RECT  36.173 63.216 36.497 63.768 ;
     RECT  35.417 2.256 36.517 7.368 ;
     RECT  35.417 8.4 36.517 8.424 ;
     RECT  36.517 2.256 36.881 8.424 ;
     RECT  36.881 1.728 36.965 8.424 ;
     RECT  37.234 0.096 37.333 0.216 ;
     RECT  37.285 1.296 37.333 1.32 ;
     RECT  37.333 0.192 37.379 1.32 ;
     RECT  36.497 63.216 37.573 63.672 ;
     RECT  37.379 1.152 37.577 1.32 ;
     RECT  37.577 1.152 37.619 1.272 ;
     RECT  37.573 63.12 37.621 63.672 ;
     RECT  36.46 66.144 37.667 67.272 ;
     RECT  37.621 63.12 37.781 64.056 ;
     RECT  37.781 62.64 37.825 64.056 ;
     RECT  37.825 62.64 37.865 64.344 ;
     RECT  36.965 2.496 38.041 8.424 ;
     RECT  35.104 31.104 38.041 35.256 ;
     RECT  35.104 36.528 38.041 36.792 ;
     RECT  37.667 66.72 38.077 67.272 ;
     RECT  38.077 66.72 38.252 67.848 ;
     RECT  38.213 68.88 38.252 68.904 ;
     RECT  38.252 66.72 38.293 68.904 ;
     RECT  38.293 66.72 38.483 69 ;
     RECT  38.041 31.104 38.549 36.792 ;
     RECT  38.483 68.64 38.723 69 ;
     RECT  38.549 36.528 38.761 36.792 ;
     RECT  38.483 66.72 38.765 67.272 ;
     RECT  35.104 50.784 38.833 50.808 ;
     RECT  38.833 50.784 38.873 50.904 ;
     RECT  38.761 36.528 38.945 36.84 ;
     RECT  37.865 62.832 39.373 64.344 ;
     RECT  39.397 0.096 39.521 0.12 ;
     RECT  39.373 1.152 39.553 1.176 ;
     RECT  38.723 68.88 39.685 69 ;
     RECT  39.373 62.64 39.733 64.344 ;
     RECT  39.733 62.592 39.74 64.344 ;
     RECT  39.685 68.736 39.827 69 ;
     RECT  38.765 66.816 39.841 67.272 ;
     RECT  39.553 1.104 39.877 1.176 ;
     RECT  38.041 2.496 39.877 8.568 ;
     RECT  39.877 1.104 39.925 8.616 ;
     RECT  39.74 62.304 39.973 64.344 ;
     RECT  39.925 0.144 40.208 8.616 ;
     RECT  35.104 19.536 40.208 19.56 ;
     RECT  35.104 22.08 40.208 24.36 ;
     RECT  35.104 26.304 40.208 28.968 ;
     RECT  38.549 31.104 40.208 35.256 ;
     RECT  38.945 36.528 40.208 36.792 ;
     RECT  35.104 39.312 40.208 46.104 ;
     RECT  38.873 50.88 40.208 50.904 ;
     RECT  39.973 62.064 40.208 64.344 ;
     RECT  39.841 66.144 40.208 67.272 ;
     RECT  40.208 0.144 40.211 67.272 ;
     RECT  40.211 0.528 40.403 67.272 ;
     RECT  40.403 1.152 40.504 67.272 ;
     RECT  40.504 62.592 40.739 64.152 ;
     RECT  40.504 1.152 40.979 8.616 ;
     RECT  40.504 67.152 41.021 67.272 ;
     RECT  40.739 62.736 41.033 64.152 ;
     RECT  41.021 67.152 41.105 67.32 ;
     RECT  39.827 68.832 41.221 69 ;
     RECT  41.221 68.784 41.473 69 ;
     RECT  40.979 1.632 41.569 8.616 ;
     RECT  41.105 67.152 41.677 67.272 ;
     RECT  41.605 0.288 41.701 0.312 ;
     RECT  41.701 0.144 41.891 0.312 ;
     RECT  41.569 1.632 41.891 9 ;
     RECT  41.473 68.784 41.891 68.952 ;
     RECT  40.504 31.104 41.893 36.792 ;
     RECT  41.033 63.12 41.932 64.152 ;
     RECT  41.891 68.928 42.083 68.952 ;
     RECT  41.932 63.216 42.121 64.152 ;
     RECT  41.891 2.112 42.401 9 ;
     RECT  41.677 66.72 42.611 67.272 ;
     RECT  40.504 22.08 42.757 24.36 ;
     RECT  42.757 21.984 42.797 24.36 ;
     RECT  42.401 2.112 42.833 8.52 ;
     RECT  42.121 64.032 42.901 64.152 ;
     RECT  40.504 50.784 43.009 50.808 ;
     RECT  42.277 0.576 43.045 0.6 ;
     RECT  43.009 50.784 43.049 50.904 ;
     RECT  42.901 64.032 43.141 64.392 ;
     RECT  41.893 31.104 43.189 36.888 ;
     RECT  43.141 63.264 43.225 64.392 ;
     RECT  43.225 63.264 43.297 65.112 ;
     RECT  42.833 2.256 43.373 8.52 ;
     RECT  43.297 62.64 43.625 65.112 ;
     RECT  42.611 67.104 43.772 67.272 ;
     RECT  43.333 68.928 43.811 68.952 ;
     RECT  43.772 66.72 43.859 67.272 ;
     RECT  43.045 0.576 43.909 0.84 ;
     RECT  43.373 2.256 43.955 7.992 ;
     RECT  43.955 2.256 43.985 7.176 ;
     RECT  43.625 62.64 44.057 64.392 ;
     RECT  43.985 2.256 44.093 6.552 ;
     RECT  43.909 0.144 44.099 0.84 ;
     RECT  44.093 2.256 44.165 6.504 ;
     RECT  44.099 0.816 44.197 0.84 ;
     RECT  44.165 2.256 44.197 6.072 ;
     RECT  44.197 0.816 44.309 6.072 ;
     RECT  43.859 67.152 44.338 67.272 ;
     RECT  44.338 67.152 44.633 67.32 ;
     RECT  40.504 19.536 44.773 19.56 ;
     RECT  44.057 62.64 44.773 64.056 ;
     RECT  44.809 66.096 44.924 66.12 ;
     RECT  44.633 67.152 44.924 67.272 ;
     RECT  45.061 68.928 45.109 68.952 ;
     RECT  45.109 68.832 45.133 68.952 ;
     RECT  45.133 68.832 45.196 69 ;
     RECT  44.773 62.592 45.313 64.056 ;
     RECT  44.924 66.096 45.349 67.272 ;
     RECT  45.349 66.048 45.445 67.272 ;
     RECT  44.309 0.816 45.608 5.64 ;
     RECT  44.773 19.536 45.608 19.8 ;
     RECT  42.797 21.984 45.608 22.008 ;
     RECT  42.797 23.04 45.608 24.36 ;
     RECT  40.504 26.304 45.608 28.968 ;
     RECT  43.189 31.104 45.608 36.936 ;
     RECT  40.504 39.312 45.608 46.104 ;
     RECT  43.049 50.88 45.608 50.904 ;
     RECT  45.313 62.592 45.608 64.344 ;
     RECT  45.445 66 45.608 67.272 ;
     RECT  45.608 0.816 45.904 67.272 ;
     RECT  45.904 64.32 45.965 67.272 ;
     RECT  45.196 68.88 46.001 69 ;
     RECT  45.904 62.736 46.115 63.24 ;
     RECT  46.001 68.88 46.115 68.952 ;
     RECT  45.904 0.816 46.217 5.208 ;
     RECT  45.904 6.912 46.217 6.936 ;
     RECT  45.965 64.32 46.289 65.208 ;
     RECT  46.217 0.816 46.397 4.248 ;
     RECT  46.115 68.88 46.405 68.904 ;
     RECT  45.904 23.04 46.541 24.36 ;
     RECT  46.405 68.784 46.547 68.904 ;
     RECT  46.289 64.32 46.577 64.968 ;
     RECT  45.904 21.984 46.649 22.008 ;
     RECT  46.115 62.784 46.694 63.24 ;
     RECT  46.397 1.824 46.721 4.248 ;
     RECT  46.721 2.256 46.793 4.248 ;
     RECT  46.397 0.816 46.901 0.84 ;
     RECT  46.694 62.832 47.045 63.24 ;
     RECT  47.045 62.88 47.077 63.24 ;
     RECT  46.577 64.32 47.077 64.344 ;
     RECT  46.793 2.256 47.189 4.2 ;
     RECT  47.077 62.88 47.189 64.344 ;
     RECT  47.189 62.88 47.297 63.24 ;
     RECT  47.189 2.256 47.333 3.672 ;
     RECT  47.297 62.976 47.405 63.144 ;
     RECT  47.333 2.256 47.477 3.384 ;
     RECT  47.477 2.592 47.549 3.384 ;
     RECT  45.965 66.672 47.557 67.272 ;
     RECT  47.549 2.592 47.693 2.904 ;
     RECT  47.189 64.32 47.701 64.344 ;
     RECT  47.557 66.528 48.013 67.272 ;
     RECT  47.693 2.592 48.017 2.616 ;
     RECT  47.405 62.976 48.373 63 ;
     RECT  48.373 62.976 48.409 63.24 ;
     RECT  47.701 64.32 48.419 64.392 ;
     RECT  45.904 50.88 48.421 50.904 ;
     RECT  48.421 50.88 48.445 51 ;
     RECT  45.904 19.536 48.449 19.8 ;
     RECT  48.013 65.568 48.481 67.272 ;
     RECT  48.409 62.736 48.493 63.24 ;
     RECT  48.445 50.832 48.508 51 ;
     RECT  48.493 62.976 48.665 63.24 ;
     RECT  48.913 68.976 49.043 69 ;
     RECT  48.419 64.368 49.097 64.392 ;
     RECT  48.481 65.52 49.565 67.272 ;
     RECT  49.565 66.096 49.601 67.272 ;
     RECT  49.601 66.096 49.673 67.224 ;
     RECT  49.673 66.624 50.285 67.224 ;
     RECT  48.449 19.776 51.008 19.8 ;
     RECT  46.541 23.088 51.008 24.36 ;
     RECT  45.904 26.304 51.008 28.968 ;
     RECT  45.904 31.104 51.008 36.936 ;
     RECT  45.904 39.312 51.008 46.104 ;
     RECT  48.508 50.832 51.008 50.856 ;
     RECT  48.665 63.216 51.008 63.24 ;
     RECT  50.005 64.56 51.008 64.584 ;
     RECT  50.285 66.624 51.008 66.972 ;
     RECT  51.008 2.148 51.112 66.972 ;
     RECT  51.112 2.418 51.304 66.702 ;
     RECT  51.304 19.776 56.408 19.8 ;
     RECT  51.304 23.088 56.408 24.36 ;
     RECT  51.304 26.304 56.408 28.968 ;
     RECT  51.304 31.104 56.408 36.936 ;
     RECT  51.304 39.312 56.408 46.056 ;
     RECT  51.304 50.832 56.408 50.856 ;
     RECT  56.408 2.148 56.512 66.972 ;
     RECT  56.512 2.418 56.704 66.702 ;
     RECT  56.704 26.304 58.705 28.968 ;
     RECT  56.704 39.312 58.705 46.056 ;
     RECT  58.705 48.048 58.741 48.072 ;
     RECT  56.704 50.832 58.813 50.856 ;
     RECT  58.741 47.04 58.889 48.072 ;
     RECT  58.813 50.832 58.925 51.24 ;
     RECT  58.705 39.216 59.713 46.056 ;
     RECT  58.889 47.04 59.713 47.304 ;
     RECT  56.704 23.088 59.857 24.36 ;
     RECT  58.705 26.304 59.857 29.064 ;
     RECT  56.704 31.104 59.857 36.936 ;
     RECT  58.925 50.832 59.857 50.856 ;
     RECT  59.785 48.528 59.965 48.552 ;
     RECT  56.704 19.776 60.131 19.8 ;
     RECT  59.965 48.528 60.149 49.08 ;
     RECT  60.085 21.12 60.361 21.144 ;
     RECT  59.857 31.104 60.433 37.896 ;
     RECT  60.361 21.12 60.613 21.384 ;
     RECT  59.857 23.088 60.613 25.032 ;
     RECT  59.713 39.216 60.721 47.304 ;
     RECT  59.857 50.688 60.865 50.856 ;
     RECT  60.433 31.104 60.937 38.184 ;
     RECT  60.149 49.008 60.956 49.08 ;
     RECT  60.865 50.064 60.956 50.856 ;
     RECT  60.613 21.12 61.808 25.032 ;
     RECT  59.857 26.112 61.808 29.064 ;
     RECT  60.937 30.576 61.808 38.184 ;
     RECT  60.721 39.216 61.808 47.88 ;
     RECT  60.956 49.008 61.808 50.856 ;
     RECT  61.808 2.148 61.912 66.972 ;
     RECT  61.912 2.418 62.104 66.702 ;
     RECT  62.104 39.216 62.339 51.096 ;
     RECT  62.104 20.16 62.741 21.768 ;
     RECT  62.104 26.112 63.137 37.032 ;
     RECT  62.104 38.16 63.395 38.184 ;
     RECT  62.339 39.312 63.457 51.096 ;
     RECT  62.104 22.752 63.497 24.936 ;
     RECT  63.497 22.896 63.565 24.936 ;
     RECT  63.565 22.896 63.677 25.08 ;
     RECT  62.741 21.12 63.749 21.768 ;
     RECT  63.457 39.312 63.893 51.288 ;
     RECT  63.137 26.304 64.325 37.032 ;
     RECT  64.325 29.376 64.361 37.032 ;
     RECT  64.361 36.816 64.429 37.032 ;
     RECT  64.325 26.304 64.501 28.152 ;
     RECT  63.677 22.896 64.645 24.888 ;
     RECT  64.361 29.376 64.649 35.784 ;
     RECT  64.429 36.816 64.717 37.32 ;
     RECT  64.501 25.872 64.721 28.152 ;
     RECT  63.749 21.12 64.757 21.672 ;
     RECT  63.893 47.856 64.793 51.288 ;
     RECT  64.757 21.168 64.829 21.672 ;
     RECT  64.645 22.704 64.865 24.888 ;
     RECT  64.649 29.664 64.865 35.784 ;
     RECT  64.865 32.304 64.901 35.784 ;
     RECT  63.893 39.312 64.901 46.776 ;
     RECT  64.793 47.856 64.969 49.032 ;
     RECT  64.721 26.544 64.973 28.152 ;
     RECT  64.901 32.352 64.973 35.784 ;
     RECT  64.717 36.816 64.973 37.608 ;
     RECT  64.901 39.312 64.973 45.864 ;
     RECT  64.969 47.088 64.973 49.032 ;
     RECT  64.829 21.552 65.005 21.672 ;
     RECT  64.865 22.704 65.005 24.648 ;
     RECT  64.973 39.312 65.009 44.376 ;
     RECT  65.009 39.312 65.045 39.912 ;
     RECT  65.009 41.616 65.045 42.648 ;
     RECT  64.973 32.352 65.081 35.4 ;
     RECT  64.973 26.64 65.225 28.152 ;
     RECT  65.005 21.552 65.261 24.648 ;
     RECT  65.009 43.92 65.297 44.376 ;
     RECT  64.793 50.4 65.297 51.288 ;
     RECT  64.973 48.48 65.405 49.032 ;
     RECT  65.297 44.304 65.585 44.376 ;
     RECT  65.297 50.4 65.693 50.424 ;
     RECT  65.261 21.552 65.729 24.456 ;
     RECT  64.865 29.664 65.801 31.128 ;
     RECT  65.081 32.352 65.801 34.824 ;
     RECT  65.801 29.664 65.945 30.504 ;
     RECT  65.045 39.456 65.977 39.912 ;
     RECT  65.801 32.352 66.053 33.576 ;
     RECT  65.977 39.456 66.157 40.104 ;
     RECT  65.225 26.736 66.161 28.056 ;
     RECT  65.945 29.76 66.161 30.504 ;
     RECT  65.045 41.856 66.233 42.648 ;
     RECT  65.729 21.552 66.517 22.536 ;
     RECT  64.973 47.088 66.517 47.112 ;
     RECT  65.405 49.008 66.625 49.032 ;
     RECT  66.517 21.504 66.697 22.536 ;
     RECT  65.729 23.664 66.697 24.456 ;
     RECT  66.161 27.168 66.697 28.056 ;
     RECT  66.233 42 66.697 42.648 ;
     RECT  65.585 44.352 66.697 44.376 ;
     RECT  66.625 48.48 66.697 49.032 ;
     RECT  66.157 39.456 66.701 40.872 ;
     RECT  66.517 46.32 66.737 47.112 ;
     RECT  66.697 21.504 67.237 24.456 ;
     RECT  66.697 25.872 67.237 25.896 ;
     RECT  66.697 27.168 67.237 28.488 ;
     RECT  66.121 35.856 67.237 35.88 ;
     RECT  64.973 37.104 67.237 37.608 ;
     RECT  66.697 42 67.237 42.696 ;
     RECT  66.697 44.304 67.237 44.376 ;
     RECT  66.737 46.416 67.237 47.112 ;
     RECT  66.697 48.48 67.237 49.8 ;
     RECT  67.237 21.264 67.273 24.456 ;
     RECT  67.237 25.872 67.273 28.584 ;
     RECT  66.161 30.144 67.273 30.504 ;
     RECT  66.053 32.496 67.273 33.576 ;
     RECT  65.801 34.8 67.273 34.824 ;
     RECT  67.237 35.856 67.273 37.704 ;
     RECT  66.701 39.456 67.273 39.624 ;
     RECT  66.701 40.848 67.273 40.872 ;
     RECT  67.237 42 67.273 44.376 ;
     RECT  67.237 46.416 67.273 49.992 ;
     RECT  67.237 51.12 67.273 51.144 ;
     RECT  67.273 21.264 67.309 31.464 ;
     RECT  67.273 32.496 67.309 38.088 ;
     RECT  67.273 40.848 67.741 44.808 ;
     RECT  67.741 20.112 67.777 20.136 ;
     RECT  67.309 21.264 67.777 38.088 ;
     RECT  67.273 39.12 67.777 39.624 ;
     RECT  67.741 40.848 67.777 45.384 ;
     RECT  67.273 46.416 67.777 51.144 ;
     RECT  67.777 39.12 68.353 51.144 ;
     RECT  67.777 19.92 68.965 38.088 ;
     RECT  68.353 39.12 68.965 51.24 ;
     RECT  68.965 19.92 69.001 51.24 ;
     RECT  69.001 19.92 69.084 51.336 ;
    LAYER M5 ;
     RECT  32.208 0.016 45.192 0.131 ;
     RECT  32.304 0.131 45.192 0.179 ;
     RECT  29.136 0.016 30.6 1.763 ;
     RECT  29.4 1.763 30.6 1.811 ;
     RECT  32.4 0.179 45.192 2.137 ;
     RECT  2.4 2.137 2.52 2.151 ;
     RECT  7.8 2.137 7.92 2.151 ;
     RECT  13.2 2.137 13.32 2.151 ;
     RECT  18.6 2.137 18.72 2.151 ;
     RECT  24 2.137 24.12 2.151 ;
     RECT  32.4 2.137 45.72 2.151 ;
     RECT  51 2.137 51.12 2.151 ;
     RECT  56.4 2.137 56.52 2.151 ;
     RECT  61.8 2.137 61.92 2.151 ;
     RECT  29.4 1.811 30.504 2.291 ;
     RECT  32.4 2.151 45.912 2.291 ;
     RECT  32.688 2.291 45.912 2.867 ;
     RECT  29.4 2.291 29.832 3.395 ;
     RECT  32.688 2.867 44.088 3.395 ;
     RECT  32.88 3.395 44.088 4.453 ;
     RECT  45.168 2.867 45.912 4.453 ;
     RECT  32.88 4.453 45.912 4.883 ;
     RECT  33.744 4.883 45.912 5.363 ;
     RECT  33.744 5.363 42.888 5.603 ;
     RECT  29.4 3.395 29.712 5.653 ;
     RECT  28.752 5.653 29.712 5.701 ;
     RECT  33.744 5.603 42.504 5.843 ;
     RECT  33.936 5.843 42.504 5.987 ;
     RECT  28.752 5.701 30.648 6.323 ;
     RECT  43.92 5.363 45.912 6.757 ;
     RECT  33.936 5.987 42.024 6.947 ;
     RECT  36.528 6.947 41.736 7.139 ;
     RECT  43.344 6.757 45.912 7.283 ;
     RECT  36.528 7.139 41.256 7.331 ;
     RECT  33.936 6.947 35.352 7.475 ;
     RECT  36.528 7.331 37.608 7.475 ;
     RECT  38.688 7.331 41.256 7.475 ;
     RECT  34.8 7.475 35.256 7.523 ;
     RECT  36.816 7.475 37.032 7.523 ;
     RECT  39.312 7.475 41.256 7.523 ;
     RECT  43.92 7.283 45.912 8.003 ;
     RECT  39.648 7.523 41.256 8.099 ;
     RECT  37.008 7.523 37.032 8.291 ;
     RECT  39.888 8.099 41.256 8.579 ;
     RECT  39.888 8.579 40.512 8.627 ;
     RECT  7.8 2.151 8.112 18.421 ;
     RECT  2.4 2.151 2.712 18.709 ;
     RECT  2.4 18.709 3.432 19.427 ;
     RECT  4.464 18.613 4.488 19.427 ;
     RECT  6.96 18.421 8.112 19.523 ;
     RECT  34.8 7.523 35.112 19.525 ;
     RECT  28.752 6.323 29.712 19.811 ;
     RECT  44.784 8.003 45.912 19.811 ;
     RECT  34.704 19.525 35.112 19.861 ;
     RECT  4.32 20.485 4.344 22.069 ;
     RECT  7.8 19.523 8.112 22.165 ;
     RECT  4.32 22.069 4.536 22.835 ;
     RECT  7.8 22.165 8.52 22.835 ;
     RECT  2.4 19.427 2.712 23.413 ;
     RECT  60.096 19.765 60.12 23.413 ;
     RECT  61.8 2.151 62.112 23.413 ;
     RECT  2.4 23.413 2.808 23.749 ;
     RECT  45.6 19.811 45.912 23.797 ;
     RECT  7.8 22.835 8.112 23.845 ;
     RECT  4.32 22.835 4.344 23.893 ;
     RECT  4.32 23.893 4.776 24.323 ;
     RECT  4.416 24.323 4.776 24.469 ;
     RECT  4.416 24.469 5.736 24.563 ;
     RECT  2.4 23.749 3.336 24.659 ;
     RECT  7.536 23.845 8.112 24.659 ;
     RECT  60.096 23.413 62.112 25.043 ;
     RECT  5.712 24.563 5.736 25.139 ;
     RECT  61.8 25.043 62.112 26.101 ;
     RECT  60.096 25.043 60.12 26.243 ;
     RECT  0.144 25.861 0.168 26.627 ;
     RECT  6.24 26.149 6.264 26.677 ;
     RECT  7.8 24.659 8.112 26.677 ;
     RECT  6.24 26.677 8.112 27.347 ;
     RECT  61.248 26.101 62.112 27.445 ;
     RECT  28.032 27.397 28.056 27.587 ;
     RECT  61.248 27.445 62.328 27.683 ;
     RECT  2.4 24.659 2.712 27.733 ;
     RECT  4.416 24.563 4.44 27.781 ;
     RECT  29.4 19.811 29.712 27.781 ;
     RECT  61.248 27.683 62.232 27.827 ;
     RECT  4.272 27.781 4.44 27.877 ;
     RECT  2.4 27.733 2.808 27.923 ;
     RECT  0.288 27.781 0.312 28.019 ;
     RECT  61.248 27.827 62.112 28.405 ;
     RECT  29.184 27.781 29.712 28.693 ;
     RECT  29.184 28.693 29.832 28.789 ;
     RECT  7.8 27.347 8.112 29.029 ;
     RECT  4.176 27.877 4.44 29.365 ;
     RECT  6.24 27.347 6.264 29.413 ;
     RECT  5.712 29.413 6.264 29.603 ;
     RECT  4.176 29.365 4.488 29.699 ;
     RECT  4.272 29.699 4.488 29.747 ;
     RECT  7.8 29.029 8.232 29.891 ;
     RECT  6.24 29.603 6.264 32.101 ;
     RECT  6.24 32.101 6.6 32.291 ;
     RECT  4.464 29.747 4.488 33.107 ;
     RECT  61.008 28.405 62.112 33.395 ;
     RECT  2.4 27.923 2.712 33.541 ;
     RECT  2.4 33.541 3.288 34.115 ;
     RECT  26.592 19.573 26.616 34.645 ;
     RECT  63.36 34.501 63.384 35.363 ;
     RECT  6.24 32.291 6.264 37.477 ;
     RECT  0.144 37.429 0.168 37.619 ;
     RECT  29.088 28.789 29.832 38.149 ;
     RECT  63.264 36.421 63.288 38.149 ;
     RECT  63.264 38.149 63.384 38.195 ;
     RECT  6.096 37.477 6.264 38.389 ;
     RECT  7.8 29.891 8.112 38.389 ;
     RECT  6.096 38.389 8.112 38.435 ;
     RECT  0.144 39.013 0.168 39.203 ;
     RECT  61.8 33.395 62.112 39.205 ;
     RECT  61.8 39.205 62.328 39.347 ;
     RECT  63.36 38.195 63.384 39.923 ;
     RECT  28.224 38.149 29.832 40.115 ;
     RECT  2.4 34.115 2.712 40.117 ;
     RECT  2.304 40.117 2.712 40.307 ;
     RECT  0.144 40.213 0.168 40.403 ;
     RECT  6.24 38.435 8.112 40.883 ;
     RECT  2.4 40.307 2.712 43.093 ;
     RECT  61.8 39.347 62.112 43.093 ;
     RECT  63.312 40.165 63.336 43.093 ;
     RECT  2.304 43.093 2.712 43.283 ;
     RECT  61.8 43.093 63.336 43.331 ;
     RECT  25.872 34.645 26.616 43.715 ;
     RECT  63.312 43.331 63.336 43.861 ;
     RECT  4.896 43.285 4.92 43.907 ;
     RECT  63.312 43.861 63.576 43.907 ;
     RECT  0.192 44.245 0.216 44.435 ;
     RECT  13.2 2.151 13.512 45.973 ;
     RECT  6.864 40.883 8.112 48.899 ;
     RECT  63.552 43.907 63.576 48.899 ;
     RECT  61.8 43.331 62.112 49.381 ;
     RECT  61.008 49.381 62.112 50.867 ;
     RECT  34.224 19.861 35.112 50.915 ;
     RECT  29.088 40.115 29.832 55.861 ;
     RECT  13.2 45.973 14.328 56.723 ;
     RECT  18.6 2.151 18.912 57.013 ;
     RECT  13.2 56.723 13.8 57.059 ;
     RECT  40.2 8.627 40.512 62.053 ;
     RECT  24 2.151 24.312 62.101 ;
     RECT  24 62.101 24.648 62.293 ;
     RECT  39.984 62.053 40.512 62.293 ;
     RECT  39.792 62.293 40.512 62.581 ;
     RECT  45.024 23.797 45.912 62.581 ;
     RECT  27.6 62.581 27.624 62.629 ;
     RECT  29.088 55.861 30.696 62.629 ;
     RECT  39.744 62.581 40.728 62.629 ;
     RECT  44.784 62.581 45.912 62.629 ;
     RECT  23.184 62.293 24.648 62.677 ;
     RECT  43.92 62.629 45.912 62.725 ;
     RECT  48.432 50.965 48.456 62.771 ;
     RECT  22.944 62.677 24.648 62.821 ;
     RECT  25.872 43.715 25.896 62.821 ;
     RECT  27.6 62.629 30.696 62.821 ;
     RECT  37.824 62.629 37.848 62.821 ;
     RECT  39.408 62.629 40.728 62.821 ;
     RECT  43.92 62.725 46.104 62.821 ;
     RECT  43.92 62.821 46.728 62.869 ;
     RECT  34.8 50.915 35.112 62.965 ;
     RECT  22.032 62.821 24.648 63.061 ;
     RECT  34.656 62.965 35.112 63.109 ;
     RECT  37.824 62.821 38.184 63.109 ;
     RECT  39.312 62.821 40.728 63.109 ;
     RECT  43.92 62.869 47.016 63.109 ;
     RECT  20.496 51.253 20.52 63.157 ;
     RECT  21.552 63.061 24.648 63.157 ;
     RECT  20.448 63.157 24.648 63.205 ;
     RECT  25.872 62.821 30.696 63.205 ;
     RECT  34.656 63.109 35.208 63.205 ;
     RECT  37.584 63.109 41.88 63.205 ;
     RECT  43.728 63.109 47.016 63.205 ;
     RECT  51 2.151 51.312 63.205 ;
     RECT  20.352 63.205 24.648 63.253 ;
     RECT  34.512 63.205 35.304 63.253 ;
     RECT  36.432 63.205 42.072 63.253 ;
     RECT  43.488 63.205 47.208 63.253 ;
     RECT  20.352 63.253 24.84 63.301 ;
     RECT  25.872 63.205 30.744 63.301 ;
     RECT  31.824 63.205 32.28 63.781 ;
     RECT  43.152 63.253 47.208 64.357 ;
     RECT  48.384 63.205 48.408 64.357 ;
     RECT  50.016 63.205 51.312 64.595 ;
     RECT  17.856 57.013 18.912 65.171 ;
     RECT  43.152 64.357 48.408 65.509 ;
     RECT  43.152 65.509 49.08 66.227 ;
     RECT  34.512 63.253 42.072 66.701 ;
     RECT  18.384 65.171 18.912 66.709 ;
     RECT  20.352 63.301 30.744 66.709 ;
     RECT  31.728 63.781 32.28 66.709 ;
     RECT  34.512 66.701 42.12 66.709 ;
     RECT  43.152 66.227 48.84 66.709 ;
     RECT  2.4 43.283 2.712 66.969 ;
     RECT  7.8 48.899 8.112 66.969 ;
     RECT  13.2 57.059 13.512 66.969 ;
     RECT  51 64.595 51.312 66.969 ;
     RECT  56.4 2.151 56.712 66.969 ;
     RECT  61.8 50.867 62.112 66.969 ;
     RECT  2.4 66.969 2.52 66.983 ;
     RECT  7.8 66.969 7.92 66.983 ;
     RECT  13.2 66.969 13.32 66.983 ;
     RECT  51 66.969 51.12 66.983 ;
     RECT  56.4 66.969 56.52 66.983 ;
     RECT  61.8 66.969 61.92 66.983 ;
     RECT  18 66.709 48.84 67.189 ;
     RECT  18 67.189 48.936 67.237 ;
     RECT  17.712 67.237 49.128 69.072 ;
  END
END ot_hbm_host_cfg_leaf_se2
END LIBRARY
